VERSION 5.8 ;
BUSBITCHARS "[]" ;
DIVIDERCHAR "/" ;
UNITS
    DATABASE MICRONS 1000 ;
END UNITS

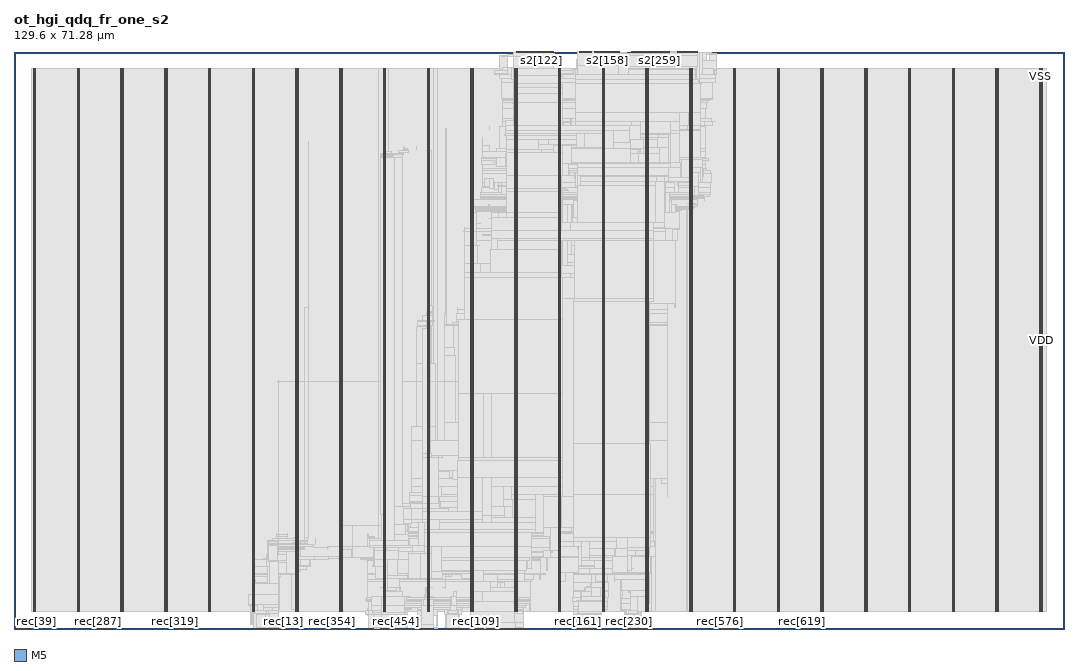
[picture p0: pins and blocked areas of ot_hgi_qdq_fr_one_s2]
MACRO ot_hgi_qdq_fr_one_s2
  FOREIGN ot_hgi_qdq_fr_one_s2 0 0 ;
  CLASS BLOCK ;
  SIZE 129.6 BY 71.28 ;
  PIN clk
    DIRECTION INPUT ;
    USE SIGNAL ;
    PORT
      LAYER M5 ;
        RECT  32.592 0 32.616 0.084 ;
    END
  END clk
  PIN nfault
    DIRECTION OUTPUT ;
    USE SIGNAL ;
    PORT
      LAYER M5 ;
        RECT  62.064 71.196 62.088 71.28 ;
    END
  END nfault
  PIN one
    DIRECTION OUTPUT ;
    USE SIGNAL ;
    PORT
      LAYER M5 ;
        RECT  62.112 71.196 62.136 71.28 ;
    END
  END one
  PIN one_s1
    DIRECTION OUTPUT ;
    USE SIGNAL ;
    PORT
      LAYER M5 ;
        RECT  62.16 71.196 62.184 71.28 ;
    END
  END one_s1
  PIN rec[0]
    DIRECTION INPUT ;
    USE SIGNAL ;
    PORT
      LAYER M5 ;
        RECT  32.64 0 32.664 0.084 ;
    END
  END rec[0]
  PIN rec[100]
    DIRECTION INPUT ;
    USE SIGNAL ;
    PORT
      LAYER M5 ;
        RECT  56.64 0 56.664 0.084 ;
    END
  END rec[100]
  PIN rec[101]
    DIRECTION INPUT ;
    USE SIGNAL ;
    PORT
      LAYER M5 ;
        RECT  56.688 0 56.712 0.084 ;
    END
  END rec[101]
  PIN rec[102]
    DIRECTION INPUT ;
    USE SIGNAL ;
    PORT
      LAYER M5 ;
        RECT  56.736 0 56.76 0.084 ;
    END
  END rec[102]
  PIN rec[103]
    DIRECTION INPUT ;
    USE SIGNAL ;
    PORT
      LAYER M5 ;
        RECT  56.784 0 56.808 0.084 ;
    END
  END rec[103]
  PIN rec[104]
    DIRECTION INPUT ;
    USE SIGNAL ;
    PORT
      LAYER M5 ;
        RECT  56.832 0 56.856 0.084 ;
    END
  END rec[104]
  PIN rec[105]
    DIRECTION INPUT ;
    USE SIGNAL ;
    PORT
      LAYER M5 ;
        RECT  56.88 0 56.904 0.084 ;
    END
  END rec[105]
  PIN rec[106]
    DIRECTION INPUT ;
    USE SIGNAL ;
    PORT
      LAYER M5 ;
        RECT  56.928 0 56.952 0.084 ;
    END
  END rec[106]
  PIN rec[107]
    DIRECTION INPUT ;
    USE SIGNAL ;
    PORT
      LAYER M5 ;
        RECT  56.976 0 57 0.084 ;
    END
  END rec[107]
  PIN rec[108]
    DIRECTION INPUT ;
    USE SIGNAL ;
    PORT
      LAYER M5 ;
        RECT  57.024 0 57.048 0.084 ;
    END
  END rec[108]
  PIN rec[109]
    DIRECTION INPUT ;
    USE SIGNAL ;
    PORT
      LAYER M5 ;
        RECT  57.072 0 57.096 0.084 ;
    END
  END rec[109]
  PIN rec[10]
    DIRECTION INPUT ;
    USE SIGNAL ;
    PORT
      LAYER M5 ;
        RECT  33.12 0 33.144 0.084 ;
    END
  END rec[10]
  PIN rec[110]
    DIRECTION INPUT ;
    USE SIGNAL ;
    PORT
      LAYER M5 ;
        RECT  57.12 0 57.144 0.084 ;
    END
  END rec[110]
  PIN rec[111]
    DIRECTION INPUT ;
    USE SIGNAL ;
    PORT
      LAYER M5 ;
        RECT  57.168 0 57.192 0.084 ;
    END
  END rec[111]
  PIN rec[112]
    DIRECTION INPUT ;
    USE SIGNAL ;
    PORT
      LAYER M5 ;
        RECT  57.216 0 57.24 0.084 ;
    END
  END rec[112]
  PIN rec[113]
    DIRECTION INPUT ;
    USE SIGNAL ;
    PORT
      LAYER M5 ;
        RECT  57.264 0 57.288 0.084 ;
    END
  END rec[113]
  PIN rec[114]
    DIRECTION INPUT ;
    USE SIGNAL ;
    PORT
      LAYER M5 ;
        RECT  57.312 0 57.336 0.084 ;
    END
  END rec[114]
  PIN rec[115]
    DIRECTION INPUT ;
    USE SIGNAL ;
    PORT
      LAYER M5 ;
        RECT  57.36 0 57.384 0.084 ;
    END
  END rec[115]
  PIN rec[116]
    DIRECTION INPUT ;
    USE SIGNAL ;
    PORT
      LAYER M5 ;
        RECT  57.408 0 57.432 0.084 ;
    END
  END rec[116]
  PIN rec[117]
    DIRECTION INPUT ;
    USE SIGNAL ;
    PORT
      LAYER M5 ;
        RECT  57.456 0 57.48 0.084 ;
    END
  END rec[117]
  PIN rec[118]
    DIRECTION INPUT ;
    USE SIGNAL ;
    PORT
      LAYER M5 ;
        RECT  57.504 0 57.528 0.084 ;
    END
  END rec[118]
  PIN rec[119]
    DIRECTION INPUT ;
    USE SIGNAL ;
    PORT
      LAYER M5 ;
        RECT  57.552 0 57.576 0.084 ;
    END
  END rec[119]
  PIN rec[11]
    DIRECTION INPUT ;
    USE SIGNAL ;
    PORT
      LAYER M5 ;
        RECT  33.168 0 33.192 0.084 ;
    END
  END rec[11]
  PIN rec[120]
    DIRECTION INPUT ;
    USE SIGNAL ;
    PORT
      LAYER M5 ;
        RECT  57.6 0 57.624 0.084 ;
    END
  END rec[120]
  PIN rec[121]
    DIRECTION INPUT ;
    USE SIGNAL ;
    PORT
      LAYER M5 ;
        RECT  57.648 0 57.672 0.084 ;
    END
  END rec[121]
  PIN rec[122]
    DIRECTION INPUT ;
    USE SIGNAL ;
    PORT
      LAYER M5 ;
        RECT  57.696 0 57.72 0.084 ;
    END
  END rec[122]
  PIN rec[123]
    DIRECTION INPUT ;
    USE SIGNAL ;
    PORT
      LAYER M5 ;
        RECT  57.744 0 57.768 0.084 ;
    END
  END rec[123]
  PIN rec[124]
    DIRECTION INPUT ;
    USE SIGNAL ;
    PORT
      LAYER M5 ;
        RECT  57.792 0 57.816 0.084 ;
    END
  END rec[124]
  PIN rec[125]
    DIRECTION INPUT ;
    USE SIGNAL ;
    PORT
      LAYER M5 ;
        RECT  57.84 0 57.864 0.084 ;
    END
  END rec[125]
  PIN rec[126]
    DIRECTION INPUT ;
    USE SIGNAL ;
    PORT
      LAYER M5 ;
        RECT  57.888 0 57.912 0.084 ;
    END
  END rec[126]
  PIN rec[127]
    DIRECTION INPUT ;
    USE SIGNAL ;
    PORT
      LAYER M5 ;
        RECT  59.856 0 59.88 0.084 ;
    END
  END rec[127]
  PIN rec[128]
    DIRECTION INPUT ;
    USE SIGNAL ;
    PORT
      LAYER M5 ;
        RECT  59.904 0 59.928 0.084 ;
    END
  END rec[128]
  PIN rec[129]
    DIRECTION INPUT ;
    USE SIGNAL ;
    PORT
      LAYER M5 ;
        RECT  59.952 0 59.976 0.084 ;
    END
  END rec[129]
  PIN rec[12]
    DIRECTION INPUT ;
    USE SIGNAL ;
    PORT
      LAYER M5 ;
        RECT  33.216 0 33.24 0.084 ;
    END
  END rec[12]
  PIN rec[130]
    DIRECTION INPUT ;
    USE SIGNAL ;
    PORT
      LAYER M5 ;
        RECT  60 0 60.024 0.084 ;
    END
  END rec[130]
  PIN rec[131]
    DIRECTION INPUT ;
    USE SIGNAL ;
    PORT
      LAYER M5 ;
        RECT  60.048 0 60.072 0.084 ;
    END
  END rec[131]
  PIN rec[132]
    DIRECTION INPUT ;
    USE SIGNAL ;
    PORT
      LAYER M5 ;
        RECT  60.096 0 60.12 0.084 ;
    END
  END rec[132]
  PIN rec[133]
    DIRECTION INPUT ;
    USE SIGNAL ;
    PORT
      LAYER M5 ;
        RECT  60.144 0 60.168 0.084 ;
    END
  END rec[133]
  PIN rec[134]
    DIRECTION INPUT ;
    USE SIGNAL ;
    PORT
      LAYER M5 ;
        RECT  60.192 0 60.216 0.084 ;
    END
  END rec[134]
  PIN rec[135]
    DIRECTION INPUT ;
    USE SIGNAL ;
    PORT
      LAYER M5 ;
        RECT  60.24 0 60.264 0.084 ;
    END
  END rec[135]
  PIN rec[136]
    DIRECTION INPUT ;
    USE SIGNAL ;
    PORT
      LAYER M5 ;
        RECT  60.288 0 60.312 0.084 ;
    END
  END rec[136]
  PIN rec[137]
    DIRECTION INPUT ;
    USE SIGNAL ;
    PORT
      LAYER M5 ;
        RECT  60.336 0 60.36 0.084 ;
    END
  END rec[137]
  PIN rec[138]
    DIRECTION INPUT ;
    USE SIGNAL ;
    PORT
      LAYER M5 ;
        RECT  60.384 0 60.408 0.084 ;
    END
  END rec[138]
  PIN rec[139]
    DIRECTION INPUT ;
    USE SIGNAL ;
    PORT
      LAYER M5 ;
        RECT  60.432 0 60.456 0.084 ;
    END
  END rec[139]
  PIN rec[13]
    DIRECTION INPUT ;
    USE SIGNAL ;
    PORT
      LAYER M5 ;
        RECT  33.264 0 33.288 0.084 ;
    END
  END rec[13]
  PIN rec[140]
    DIRECTION INPUT ;
    USE SIGNAL ;
    PORT
      LAYER M5 ;
        RECT  60.48 0 60.504 0.084 ;
    END
  END rec[140]
  PIN rec[141]
    DIRECTION INPUT ;
    USE SIGNAL ;
    PORT
      LAYER M5 ;
        RECT  60.528 0 60.552 0.084 ;
    END
  END rec[141]
  PIN rec[142]
    DIRECTION INPUT ;
    USE SIGNAL ;
    PORT
      LAYER M5 ;
        RECT  60.576 0 60.6 0.084 ;
    END
  END rec[142]
  PIN rec[143]
    DIRECTION INPUT ;
    USE SIGNAL ;
    PORT
      LAYER M5 ;
        RECT  60.624 0 60.648 0.084 ;
    END
  END rec[143]
  PIN rec[144]
    DIRECTION INPUT ;
    USE SIGNAL ;
    PORT
      LAYER M5 ;
        RECT  60.672 0 60.696 0.084 ;
    END
  END rec[144]
  PIN rec[145]
    DIRECTION INPUT ;
    USE SIGNAL ;
    PORT
      LAYER M5 ;
        RECT  60.72 0 60.744 0.084 ;
    END
  END rec[145]
  PIN rec[146]
    DIRECTION INPUT ;
    USE SIGNAL ;
    PORT
      LAYER M5 ;
        RECT  60.768 0 60.792 0.084 ;
    END
  END rec[146]
  PIN rec[147]
    DIRECTION INPUT ;
    USE SIGNAL ;
    PORT
      LAYER M5 ;
        RECT  60.816 0 60.84 0.084 ;
    END
  END rec[147]
  PIN rec[148]
    DIRECTION INPUT ;
    USE SIGNAL ;
    PORT
      LAYER M5 ;
        RECT  60.864 0 60.888 0.084 ;
    END
  END rec[148]
  PIN rec[149]
    DIRECTION INPUT ;
    USE SIGNAL ;
    PORT
      LAYER M5 ;
        RECT  60.912 0 60.936 0.084 ;
    END
  END rec[149]
  PIN rec[14]
    DIRECTION INPUT ;
    USE SIGNAL ;
    PORT
      LAYER M5 ;
        RECT  33.312 0 33.336 0.084 ;
    END
  END rec[14]
  PIN rec[150]
    DIRECTION INPUT ;
    USE SIGNAL ;
    PORT
      LAYER M5 ;
        RECT  60.96 0 60.984 0.084 ;
    END
  END rec[150]
  PIN rec[151]
    DIRECTION INPUT ;
    USE SIGNAL ;
    PORT
      LAYER M5 ;
        RECT  61.008 0 61.032 0.084 ;
    END
  END rec[151]
  PIN rec[152]
    DIRECTION INPUT ;
    USE SIGNAL ;
    PORT
      LAYER M5 ;
        RECT  61.056 0 61.08 0.084 ;
    END
  END rec[152]
  PIN rec[153]
    DIRECTION INPUT ;
    USE SIGNAL ;
    PORT
      LAYER M5 ;
        RECT  61.104 0 61.128 0.084 ;
    END
  END rec[153]
  PIN rec[154]
    DIRECTION INPUT ;
    USE SIGNAL ;
    PORT
      LAYER M5 ;
        RECT  61.152 0 61.176 0.084 ;
    END
  END rec[154]
  PIN rec[155]
    DIRECTION INPUT ;
    USE SIGNAL ;
    PORT
      LAYER M5 ;
        RECT  61.2 0 61.224 0.084 ;
    END
  END rec[155]
  PIN rec[156]
    DIRECTION INPUT ;
    USE SIGNAL ;
    PORT
      LAYER M5 ;
        RECT  61.248 0 61.272 0.084 ;
    END
  END rec[156]
  PIN rec[157]
    DIRECTION INPUT ;
    USE SIGNAL ;
    PORT
      LAYER M5 ;
        RECT  61.296 0 61.32 0.084 ;
    END
  END rec[157]
  PIN rec[158]
    DIRECTION INPUT ;
    USE SIGNAL ;
    PORT
      LAYER M5 ;
        RECT  61.344 0 61.368 0.084 ;
    END
  END rec[158]
  PIN rec[159]
    DIRECTION INPUT ;
    USE SIGNAL ;
    PORT
      LAYER M5 ;
        RECT  69.456 0 69.48 0.084 ;
    END
  END rec[159]
  PIN rec[15]
    DIRECTION INPUT ;
    USE SIGNAL ;
    PORT
      LAYER M5 ;
        RECT  33.36 0 33.384 0.084 ;
    END
  END rec[15]
  PIN rec[160]
    DIRECTION INPUT ;
    USE SIGNAL ;
    PORT
      LAYER M5 ;
        RECT  69.504 0 69.528 0.084 ;
    END
  END rec[160]
  PIN rec[161]
    DIRECTION INPUT ;
    USE SIGNAL ;
    PORT
      LAYER M5 ;
        RECT  69.552 0 69.576 0.084 ;
    END
  END rec[161]
  PIN rec[162]
    DIRECTION INPUT ;
    USE SIGNAL ;
    PORT
      LAYER M5 ;
        RECT  69.6 0 69.624 0.084 ;
    END
  END rec[162]
  PIN rec[163]
    DIRECTION INPUT ;
    USE SIGNAL ;
    PORT
      LAYER M5 ;
        RECT  69.648 0 69.672 0.084 ;
    END
  END rec[163]
  PIN rec[164]
    DIRECTION INPUT ;
    USE SIGNAL ;
    PORT
      LAYER M5 ;
        RECT  69.696 0 69.72 0.084 ;
    END
  END rec[164]
  PIN rec[165]
    DIRECTION INPUT ;
    USE SIGNAL ;
    PORT
      LAYER M5 ;
        RECT  69.744 0 69.768 0.084 ;
    END
  END rec[165]
  PIN rec[166]
    DIRECTION INPUT ;
    USE SIGNAL ;
    PORT
      LAYER M5 ;
        RECT  69.792 0 69.816 0.084 ;
    END
  END rec[166]
  PIN rec[167]
    DIRECTION INPUT ;
    USE SIGNAL ;
    PORT
      LAYER M5 ;
        RECT  69.84 0 69.864 0.084 ;
    END
  END rec[167]
  PIN rec[168]
    DIRECTION INPUT ;
    USE SIGNAL ;
    PORT
      LAYER M5 ;
        RECT  69.888 0 69.912 0.084 ;
    END
  END rec[168]
  PIN rec[169]
    DIRECTION INPUT ;
    USE SIGNAL ;
    PORT
      LAYER M5 ;
        RECT  69.936 0 69.96 0.084 ;
    END
  END rec[169]
  PIN rec[16]
    DIRECTION INPUT ;
    USE SIGNAL ;
    PORT
      LAYER M5 ;
        RECT  33.408 0 33.432 0.084 ;
    END
  END rec[16]
  PIN rec[170]
    DIRECTION INPUT ;
    USE SIGNAL ;
    PORT
      LAYER M5 ;
        RECT  69.984 0 70.008 0.084 ;
    END
  END rec[170]
  PIN rec[171]
    DIRECTION INPUT ;
    USE SIGNAL ;
    PORT
      LAYER M5 ;
        RECT  70.032 0 70.056 0.084 ;
    END
  END rec[171]
  PIN rec[172]
    DIRECTION INPUT ;
    USE SIGNAL ;
    PORT
      LAYER M5 ;
        RECT  70.08 0 70.104 0.084 ;
    END
  END rec[172]
  PIN rec[173]
    DIRECTION INPUT ;
    USE SIGNAL ;
    PORT
      LAYER M5 ;
        RECT  70.128 0 70.152 0.084 ;
    END
  END rec[173]
  PIN rec[174]
    DIRECTION INPUT ;
    USE SIGNAL ;
    PORT
      LAYER M5 ;
        RECT  70.176 0 70.2 0.084 ;
    END
  END rec[174]
  PIN rec[175]
    DIRECTION INPUT ;
    USE SIGNAL ;
    PORT
      LAYER M5 ;
        RECT  70.224 0 70.248 0.084 ;
    END
  END rec[175]
  PIN rec[176]
    DIRECTION INPUT ;
    USE SIGNAL ;
    PORT
      LAYER M5 ;
        RECT  70.272 0 70.296 0.084 ;
    END
  END rec[176]
  PIN rec[177]
    DIRECTION INPUT ;
    USE SIGNAL ;
    PORT
      LAYER M5 ;
        RECT  70.32 0 70.344 0.084 ;
    END
  END rec[177]
  PIN rec[178]
    DIRECTION INPUT ;
    USE SIGNAL ;
    PORT
      LAYER M5 ;
        RECT  70.368 0 70.392 0.084 ;
    END
  END rec[178]
  PIN rec[179]
    DIRECTION INPUT ;
    USE SIGNAL ;
    PORT
      LAYER M5 ;
        RECT  70.416 0 70.44 0.084 ;
    END
  END rec[179]
  PIN rec[17]
    DIRECTION INPUT ;
    USE SIGNAL ;
    PORT
      LAYER M5 ;
        RECT  33.456 0 33.48 0.084 ;
    END
  END rec[17]
  PIN rec[180]
    DIRECTION INPUT ;
    USE SIGNAL ;
    PORT
      LAYER M5 ;
        RECT  70.464 0 70.488 0.084 ;
    END
  END rec[180]
  PIN rec[181]
    DIRECTION INPUT ;
    USE SIGNAL ;
    PORT
      LAYER M5 ;
        RECT  70.512 0 70.536 0.084 ;
    END
  END rec[181]
  PIN rec[182]
    DIRECTION INPUT ;
    USE SIGNAL ;
    PORT
      LAYER M5 ;
        RECT  70.56 0 70.584 0.084 ;
    END
  END rec[182]
  PIN rec[183]
    DIRECTION INPUT ;
    USE SIGNAL ;
    PORT
      LAYER M5 ;
        RECT  70.608 0 70.632 0.084 ;
    END
  END rec[183]
  PIN rec[184]
    DIRECTION INPUT ;
    USE SIGNAL ;
    PORT
      LAYER M5 ;
        RECT  70.656 0 70.68 0.084 ;
    END
  END rec[184]
  PIN rec[185]
    DIRECTION INPUT ;
    USE SIGNAL ;
    PORT
      LAYER M5 ;
        RECT  70.704 0 70.728 0.084 ;
    END
  END rec[185]
  PIN rec[186]
    DIRECTION INPUT ;
    USE SIGNAL ;
    PORT
      LAYER M5 ;
        RECT  70.752 0 70.776 0.084 ;
    END
  END rec[186]
  PIN rec[187]
    DIRECTION INPUT ;
    USE SIGNAL ;
    PORT
      LAYER M5 ;
        RECT  70.8 0 70.824 0.084 ;
    END
  END rec[187]
  PIN rec[188]
    DIRECTION INPUT ;
    USE SIGNAL ;
    PORT
      LAYER M5 ;
        RECT  70.848 0 70.872 0.084 ;
    END
  END rec[188]
  PIN rec[189]
    DIRECTION INPUT ;
    USE SIGNAL ;
    PORT
      LAYER M5 ;
        RECT  70.896 0 70.92 0.084 ;
    END
  END rec[189]
  PIN rec[18]
    DIRECTION INPUT ;
    USE SIGNAL ;
    PORT
      LAYER M5 ;
        RECT  33.504 0 33.528 0.084 ;
    END
  END rec[18]
  PIN rec[190]
    DIRECTION INPUT ;
    USE SIGNAL ;
    PORT
      LAYER M5 ;
        RECT  70.944 0 70.968 0.084 ;
    END
  END rec[190]
  PIN rec[191]
    DIRECTION INPUT ;
    USE SIGNAL ;
    PORT
      LAYER M5 ;
        RECT  50.256 0 50.28 0.084 ;
    END
  END rec[191]
  PIN rec[192]
    DIRECTION INPUT ;
    USE SIGNAL ;
    PORT
      LAYER M5 ;
        RECT  50.304 0 50.328 0.084 ;
    END
  END rec[192]
  PIN rec[193]
    DIRECTION INPUT ;
    USE SIGNAL ;
    PORT
      LAYER M5 ;
        RECT  50.352 0 50.376 0.084 ;
    END
  END rec[193]
  PIN rec[194]
    DIRECTION INPUT ;
    USE SIGNAL ;
    PORT
      LAYER M5 ;
        RECT  50.4 0 50.424 0.084 ;
    END
  END rec[194]
  PIN rec[195]
    DIRECTION INPUT ;
    USE SIGNAL ;
    PORT
      LAYER M5 ;
        RECT  50.448 0 50.472 0.084 ;
    END
  END rec[195]
  PIN rec[196]
    DIRECTION INPUT ;
    USE SIGNAL ;
    PORT
      LAYER M5 ;
        RECT  50.496 0 50.52 0.084 ;
    END
  END rec[196]
  PIN rec[197]
    DIRECTION INPUT ;
    USE SIGNAL ;
    PORT
      LAYER M5 ;
        RECT  50.544 0 50.568 0.084 ;
    END
  END rec[197]
  PIN rec[198]
    DIRECTION INPUT ;
    USE SIGNAL ;
    PORT
      LAYER M5 ;
        RECT  50.592 0 50.616 0.084 ;
    END
  END rec[198]
  PIN rec[199]
    DIRECTION INPUT ;
    USE SIGNAL ;
    PORT
      LAYER M5 ;
        RECT  50.64 0 50.664 0.084 ;
    END
  END rec[199]
  PIN rec[19]
    DIRECTION INPUT ;
    USE SIGNAL ;
    PORT
      LAYER M5 ;
        RECT  33.552 0 33.576 0.084 ;
    END
  END rec[19]
  PIN rec[1]
    DIRECTION INPUT ;
    USE SIGNAL ;
    PORT
      LAYER M5 ;
        RECT  32.688 0 32.712 0.084 ;
    END
  END rec[1]
  PIN rec[200]
    DIRECTION INPUT ;
    USE SIGNAL ;
    PORT
      LAYER M5 ;
        RECT  50.688 0 50.712 0.084 ;
    END
  END rec[200]
  PIN rec[201]
    DIRECTION INPUT ;
    USE SIGNAL ;
    PORT
      LAYER M5 ;
        RECT  50.736 0 50.76 0.084 ;
    END
  END rec[201]
  PIN rec[202]
    DIRECTION INPUT ;
    USE SIGNAL ;
    PORT
      LAYER M5 ;
        RECT  50.784 0 50.808 0.084 ;
    END
  END rec[202]
  PIN rec[203]
    DIRECTION INPUT ;
    USE SIGNAL ;
    PORT
      LAYER M5 ;
        RECT  50.832 0 50.856 0.084 ;
    END
  END rec[203]
  PIN rec[204]
    DIRECTION INPUT ;
    USE SIGNAL ;
    PORT
      LAYER M5 ;
        RECT  50.88 0 50.904 0.084 ;
    END
  END rec[204]
  PIN rec[205]
    DIRECTION INPUT ;
    USE SIGNAL ;
    PORT
      LAYER M5 ;
        RECT  50.928 0 50.952 0.084 ;
    END
  END rec[205]
  PIN rec[206]
    DIRECTION INPUT ;
    USE SIGNAL ;
    PORT
      LAYER M5 ;
        RECT  50.976 0 51 0.084 ;
    END
  END rec[206]
  PIN rec[207]
    DIRECTION INPUT ;
    USE SIGNAL ;
    PORT
      LAYER M5 ;
        RECT  51.024 0 51.048 0.084 ;
    END
  END rec[207]
  PIN rec[208]
    DIRECTION INPUT ;
    USE SIGNAL ;
    PORT
      LAYER M5 ;
        RECT  51.072 0 51.096 0.084 ;
    END
  END rec[208]
  PIN rec[209]
    DIRECTION INPUT ;
    USE SIGNAL ;
    PORT
      LAYER M5 ;
        RECT  51.12 0 51.144 0.084 ;
    END
  END rec[209]
  PIN rec[20]
    DIRECTION INPUT ;
    USE SIGNAL ;
    PORT
      LAYER M5 ;
        RECT  33.6 0 33.624 0.084 ;
    END
  END rec[20]
  PIN rec[210]
    DIRECTION INPUT ;
    USE SIGNAL ;
    PORT
      LAYER M5 ;
        RECT  51.168 0 51.192 0.084 ;
    END
  END rec[210]
  PIN rec[211]
    DIRECTION INPUT ;
    USE SIGNAL ;
    PORT
      LAYER M5 ;
        RECT  51.216 0 51.24 0.084 ;
    END
  END rec[211]
  PIN rec[212]
    DIRECTION INPUT ;
    USE SIGNAL ;
    PORT
      LAYER M5 ;
        RECT  51.264 0 51.288 0.084 ;
    END
  END rec[212]
  PIN rec[213]
    DIRECTION INPUT ;
    USE SIGNAL ;
    PORT
      LAYER M5 ;
        RECT  51.312 0 51.336 0.084 ;
    END
  END rec[213]
  PIN rec[214]
    DIRECTION INPUT ;
    USE SIGNAL ;
    PORT
      LAYER M5 ;
        RECT  51.36 0 51.384 0.084 ;
    END
  END rec[214]
  PIN rec[215]
    DIRECTION INPUT ;
    USE SIGNAL ;
    PORT
      LAYER M5 ;
        RECT  51.408 0 51.432 0.084 ;
    END
  END rec[215]
  PIN rec[216]
    DIRECTION INPUT ;
    USE SIGNAL ;
    PORT
      LAYER M5 ;
        RECT  51.456 0 51.48 0.084 ;
    END
  END rec[216]
  PIN rec[217]
    DIRECTION INPUT ;
    USE SIGNAL ;
    PORT
      LAYER M5 ;
        RECT  51.504 0 51.528 0.084 ;
    END
  END rec[217]
  PIN rec[218]
    DIRECTION INPUT ;
    USE SIGNAL ;
    PORT
      LAYER M5 ;
        RECT  51.552 0 51.576 0.084 ;
    END
  END rec[218]
  PIN rec[219]
    DIRECTION INPUT ;
    USE SIGNAL ;
    PORT
      LAYER M5 ;
        RECT  51.6 0 51.624 0.084 ;
    END
  END rec[219]
  PIN rec[21]
    DIRECTION INPUT ;
    USE SIGNAL ;
    PORT
      LAYER M5 ;
        RECT  33.648 0 33.672 0.084 ;
    END
  END rec[21]
  PIN rec[220]
    DIRECTION INPUT ;
    USE SIGNAL ;
    PORT
      LAYER M5 ;
        RECT  51.648 0 51.672 0.084 ;
    END
  END rec[220]
  PIN rec[221]
    DIRECTION INPUT ;
    USE SIGNAL ;
    PORT
      LAYER M5 ;
        RECT  51.696 0 51.72 0.084 ;
    END
  END rec[221]
  PIN rec[222]
    DIRECTION INPUT ;
    USE SIGNAL ;
    PORT
      LAYER M5 ;
        RECT  51.744 0 51.768 0.084 ;
    END
  END rec[222]
  PIN rec[223]
    DIRECTION INPUT ;
    USE SIGNAL ;
    PORT
      LAYER M5 ;
        RECT  75.6 0 75.624 0.084 ;
    END
  END rec[223]
  PIN rec[224]
    DIRECTION INPUT ;
    USE SIGNAL ;
    PORT
      LAYER M5 ;
        RECT  75.648 0 75.672 0.084 ;
    END
  END rec[224]
  PIN rec[225]
    DIRECTION INPUT ;
    USE SIGNAL ;
    PORT
      LAYER M5 ;
        RECT  75.696 0 75.72 0.084 ;
    END
  END rec[225]
  PIN rec[226]
    DIRECTION INPUT ;
    USE SIGNAL ;
    PORT
      LAYER M5 ;
        RECT  75.744 0 75.768 0.084 ;
    END
  END rec[226]
  PIN rec[227]
    DIRECTION INPUT ;
    USE SIGNAL ;
    PORT
      LAYER M5 ;
        RECT  75.792 0 75.816 0.084 ;
    END
  END rec[227]
  PIN rec[228]
    DIRECTION INPUT ;
    USE SIGNAL ;
    PORT
      LAYER M5 ;
        RECT  75.84 0 75.864 0.084 ;
    END
  END rec[228]
  PIN rec[229]
    DIRECTION INPUT ;
    USE SIGNAL ;
    PORT
      LAYER M5 ;
        RECT  75.888 0 75.912 0.084 ;
    END
  END rec[229]
  PIN rec[22]
    DIRECTION INPUT ;
    USE SIGNAL ;
    PORT
      LAYER M5 ;
        RECT  33.696 0 33.72 0.084 ;
    END
  END rec[22]
  PIN rec[230]
    DIRECTION INPUT ;
    USE SIGNAL ;
    PORT
      LAYER M5 ;
        RECT  75.936 0 75.96 0.084 ;
    END
  END rec[230]
  PIN rec[231]
    DIRECTION INPUT ;
    USE SIGNAL ;
    PORT
      LAYER M5 ;
        RECT  75.984 0 76.008 0.084 ;
    END
  END rec[231]
  PIN rec[232]
    DIRECTION INPUT ;
    USE SIGNAL ;
    PORT
      LAYER M5 ;
        RECT  76.032 0 76.056 0.084 ;
    END
  END rec[232]
  PIN rec[233]
    DIRECTION INPUT ;
    USE SIGNAL ;
    PORT
      LAYER M5 ;
        RECT  76.08 0 76.104 0.084 ;
    END
  END rec[233]
  PIN rec[234]
    DIRECTION INPUT ;
    USE SIGNAL ;
    PORT
      LAYER M5 ;
        RECT  76.128 0 76.152 0.084 ;
    END
  END rec[234]
  PIN rec[235]
    DIRECTION INPUT ;
    USE SIGNAL ;
    PORT
      LAYER M5 ;
        RECT  76.176 0 76.2 0.084 ;
    END
  END rec[235]
  PIN rec[236]
    DIRECTION INPUT ;
    USE SIGNAL ;
    PORT
      LAYER M5 ;
        RECT  76.224 0 76.248 0.084 ;
    END
  END rec[236]
  PIN rec[237]
    DIRECTION INPUT ;
    USE SIGNAL ;
    PORT
      LAYER M5 ;
        RECT  76.272 0 76.296 0.084 ;
    END
  END rec[237]
  PIN rec[238]
    DIRECTION INPUT ;
    USE SIGNAL ;
    PORT
      LAYER M5 ;
        RECT  76.32 0 76.344 0.084 ;
    END
  END rec[238]
  PIN rec[239]
    DIRECTION INPUT ;
    USE SIGNAL ;
    PORT
      LAYER M5 ;
        RECT  76.368 0 76.392 0.084 ;
    END
  END rec[239]
  PIN rec[23]
    DIRECTION INPUT ;
    USE SIGNAL ;
    PORT
      LAYER M5 ;
        RECT  33.744 0 33.768 0.084 ;
    END
  END rec[23]
  PIN rec[240]
    DIRECTION INPUT ;
    USE SIGNAL ;
    PORT
      LAYER M5 ;
        RECT  76.416 0 76.44 0.084 ;
    END
  END rec[240]
  PIN rec[241]
    DIRECTION INPUT ;
    USE SIGNAL ;
    PORT
      LAYER M5 ;
        RECT  76.464 0 76.488 0.084 ;
    END
  END rec[241]
  PIN rec[242]
    DIRECTION INPUT ;
    USE SIGNAL ;
    PORT
      LAYER M5 ;
        RECT  76.512 0 76.536 0.084 ;
    END
  END rec[242]
  PIN rec[243]
    DIRECTION INPUT ;
    USE SIGNAL ;
    PORT
      LAYER M5 ;
        RECT  76.56 0 76.584 0.084 ;
    END
  END rec[243]
  PIN rec[244]
    DIRECTION INPUT ;
    USE SIGNAL ;
    PORT
      LAYER M5 ;
        RECT  76.608 0 76.632 0.084 ;
    END
  END rec[244]
  PIN rec[245]
    DIRECTION INPUT ;
    USE SIGNAL ;
    PORT
      LAYER M5 ;
        RECT  76.656 0 76.68 0.084 ;
    END
  END rec[245]
  PIN rec[246]
    DIRECTION INPUT ;
    USE SIGNAL ;
    PORT
      LAYER M5 ;
        RECT  76.704 0 76.728 0.084 ;
    END
  END rec[246]
  PIN rec[247]
    DIRECTION INPUT ;
    USE SIGNAL ;
    PORT
      LAYER M5 ;
        RECT  76.752 0 76.776 0.084 ;
    END
  END rec[247]
  PIN rec[248]
    DIRECTION INPUT ;
    USE SIGNAL ;
    PORT
      LAYER M5 ;
        RECT  76.8 0 76.824 0.084 ;
    END
  END rec[248]
  PIN rec[249]
    DIRECTION INPUT ;
    USE SIGNAL ;
    PORT
      LAYER M5 ;
        RECT  76.848 0 76.872 0.084 ;
    END
  END rec[249]
  PIN rec[24]
    DIRECTION INPUT ;
    USE SIGNAL ;
    PORT
      LAYER M5 ;
        RECT  33.792 0 33.816 0.084 ;
    END
  END rec[24]
  PIN rec[250]
    DIRECTION INPUT ;
    USE SIGNAL ;
    PORT
      LAYER M5 ;
        RECT  76.896 0 76.92 0.084 ;
    END
  END rec[250]
  PIN rec[251]
    DIRECTION INPUT ;
    USE SIGNAL ;
    PORT
      LAYER M5 ;
        RECT  76.944 0 76.968 0.084 ;
    END
  END rec[251]
  PIN rec[252]
    DIRECTION INPUT ;
    USE SIGNAL ;
    PORT
      LAYER M5 ;
        RECT  76.992 0 77.016 0.084 ;
    END
  END rec[252]
  PIN rec[253]
    DIRECTION INPUT ;
    USE SIGNAL ;
    PORT
      LAYER M5 ;
        RECT  77.04 0 77.064 0.084 ;
    END
  END rec[253]
  PIN rec[254]
    DIRECTION INPUT ;
    USE SIGNAL ;
    PORT
      LAYER M5 ;
        RECT  77.088 0 77.112 0.084 ;
    END
  END rec[254]
  PIN rec[255]
    DIRECTION INPUT ;
    USE SIGNAL ;
    PORT
      LAYER M5 ;
        RECT  29.52 0 29.544 0.084 ;
    END
  END rec[255]
  PIN rec[256]
    DIRECTION INPUT ;
    USE SIGNAL ;
    PORT
      LAYER M5 ;
        RECT  29.568 0 29.592 0.084 ;
    END
  END rec[256]
  PIN rec[257]
    DIRECTION INPUT ;
    USE SIGNAL ;
    PORT
      LAYER M5 ;
        RECT  29.616 0 29.64 0.084 ;
    END
  END rec[257]
  PIN rec[258]
    DIRECTION INPUT ;
    USE SIGNAL ;
    PORT
      LAYER M5 ;
        RECT  29.664 0 29.688 0.084 ;
    END
  END rec[258]
  PIN rec[259]
    DIRECTION INPUT ;
    USE SIGNAL ;
    PORT
      LAYER M5 ;
        RECT  29.712 0 29.736 0.084 ;
    END
  END rec[259]
  PIN rec[25]
    DIRECTION INPUT ;
    USE SIGNAL ;
    PORT
      LAYER M5 ;
        RECT  33.84 0 33.864 0.084 ;
    END
  END rec[25]
  PIN rec[260]
    DIRECTION INPUT ;
    USE SIGNAL ;
    PORT
      LAYER M5 ;
        RECT  29.76 0 29.784 0.084 ;
    END
  END rec[260]
  PIN rec[261]
    DIRECTION INPUT ;
    USE SIGNAL ;
    PORT
      LAYER M5 ;
        RECT  29.808 0 29.832 0.084 ;
    END
  END rec[261]
  PIN rec[262]
    DIRECTION INPUT ;
    USE SIGNAL ;
    PORT
      LAYER M5 ;
        RECT  29.856 0 29.88 0.084 ;
    END
  END rec[262]
  PIN rec[263]
    DIRECTION INPUT ;
    USE SIGNAL ;
    PORT
      LAYER M5 ;
        RECT  29.904 0 29.928 0.084 ;
    END
  END rec[263]
  PIN rec[264]
    DIRECTION INPUT ;
    USE SIGNAL ;
    PORT
      LAYER M5 ;
        RECT  29.952 0 29.976 0.084 ;
    END
  END rec[264]
  PIN rec[265]
    DIRECTION INPUT ;
    USE SIGNAL ;
    PORT
      LAYER M5 ;
        RECT  30 0 30.024 0.084 ;
    END
  END rec[265]
  PIN rec[266]
    DIRECTION INPUT ;
    USE SIGNAL ;
    PORT
      LAYER M5 ;
        RECT  30.048 0 30.072 0.084 ;
    END
  END rec[266]
  PIN rec[267]
    DIRECTION INPUT ;
    USE SIGNAL ;
    PORT
      LAYER M5 ;
        RECT  30.096 0 30.12 0.084 ;
    END
  END rec[267]
  PIN rec[268]
    DIRECTION INPUT ;
    USE SIGNAL ;
    PORT
      LAYER M5 ;
        RECT  30.144 0 30.168 0.084 ;
    END
  END rec[268]
  PIN rec[269]
    DIRECTION INPUT ;
    USE SIGNAL ;
    PORT
      LAYER M5 ;
        RECT  30.192 0 30.216 0.084 ;
    END
  END rec[269]
  PIN rec[26]
    DIRECTION INPUT ;
    USE SIGNAL ;
    PORT
      LAYER M5 ;
        RECT  33.888 0 33.912 0.084 ;
    END
  END rec[26]
  PIN rec[270]
    DIRECTION INPUT ;
    USE SIGNAL ;
    PORT
      LAYER M5 ;
        RECT  30.24 0 30.264 0.084 ;
    END
  END rec[270]
  PIN rec[271]
    DIRECTION INPUT ;
    USE SIGNAL ;
    PORT
      LAYER M5 ;
        RECT  30.288 0 30.312 0.084 ;
    END
  END rec[271]
  PIN rec[272]
    DIRECTION INPUT ;
    USE SIGNAL ;
    PORT
      LAYER M5 ;
        RECT  30.336 0 30.36 0.084 ;
    END
  END rec[272]
  PIN rec[273]
    DIRECTION INPUT ;
    USE SIGNAL ;
    PORT
      LAYER M5 ;
        RECT  30.384 0 30.408 0.084 ;
    END
  END rec[273]
  PIN rec[274]
    DIRECTION INPUT ;
    USE SIGNAL ;
    PORT
      LAYER M5 ;
        RECT  30.432 0 30.456 0.084 ;
    END
  END rec[274]
  PIN rec[275]
    DIRECTION INPUT ;
    USE SIGNAL ;
    PORT
      LAYER M5 ;
        RECT  30.48 0 30.504 0.084 ;
    END
  END rec[275]
  PIN rec[276]
    DIRECTION INPUT ;
    USE SIGNAL ;
    PORT
      LAYER M5 ;
        RECT  30.528 0 30.552 0.084 ;
    END
  END rec[276]
  PIN rec[277]
    DIRECTION INPUT ;
    USE SIGNAL ;
    PORT
      LAYER M5 ;
        RECT  30.576 0 30.6 0.084 ;
    END
  END rec[277]
  PIN rec[278]
    DIRECTION INPUT ;
    USE SIGNAL ;
    PORT
      LAYER M5 ;
        RECT  30.624 0 30.648 0.084 ;
    END
  END rec[278]
  PIN rec[279]
    DIRECTION INPUT ;
    USE SIGNAL ;
    PORT
      LAYER M5 ;
        RECT  30.672 0 30.696 0.084 ;
    END
  END rec[279]
  PIN rec[27]
    DIRECTION INPUT ;
    USE SIGNAL ;
    PORT
      LAYER M5 ;
        RECT  33.936 0 33.96 0.084 ;
    END
  END rec[27]
  PIN rec[280]
    DIRECTION INPUT ;
    USE SIGNAL ;
    PORT
      LAYER M5 ;
        RECT  30.72 0 30.744 0.084 ;
    END
  END rec[280]
  PIN rec[281]
    DIRECTION INPUT ;
    USE SIGNAL ;
    PORT
      LAYER M5 ;
        RECT  30.768 0 30.792 0.084 ;
    END
  END rec[281]
  PIN rec[282]
    DIRECTION INPUT ;
    USE SIGNAL ;
    PORT
      LAYER M5 ;
        RECT  30.816 0 30.84 0.084 ;
    END
  END rec[282]
  PIN rec[283]
    DIRECTION INPUT ;
    USE SIGNAL ;
    PORT
      LAYER M5 ;
        RECT  30.864 0 30.888 0.084 ;
    END
  END rec[283]
  PIN rec[284]
    DIRECTION INPUT ;
    USE SIGNAL ;
    PORT
      LAYER M5 ;
        RECT  30.912 0 30.936 0.084 ;
    END
  END rec[284]
  PIN rec[285]
    DIRECTION INPUT ;
    USE SIGNAL ;
    PORT
      LAYER M5 ;
        RECT  30.96 0 30.984 0.084 ;
    END
  END rec[285]
  PIN rec[286]
    DIRECTION INPUT ;
    USE SIGNAL ;
    PORT
      LAYER M5 ;
        RECT  31.008 0 31.032 0.084 ;
    END
  END rec[286]
  PIN rec[287]
    DIRECTION INPUT ;
    USE SIGNAL ;
    PORT
      LAYER M5 ;
        RECT  10.32 0 10.344 0.084 ;
    END
  END rec[287]
  PIN rec[288]
    DIRECTION INPUT ;
    USE SIGNAL ;
    PORT
      LAYER M5 ;
        RECT  10.368 0 10.392 0.084 ;
    END
  END rec[288]
  PIN rec[289]
    DIRECTION INPUT ;
    USE SIGNAL ;
    PORT
      LAYER M5 ;
        RECT  10.416 0 10.44 0.084 ;
    END
  END rec[289]
  PIN rec[28]
    DIRECTION INPUT ;
    USE SIGNAL ;
    PORT
      LAYER M5 ;
        RECT  33.984 0 34.008 0.084 ;
    END
  END rec[28]
  PIN rec[290]
    DIRECTION INPUT ;
    USE SIGNAL ;
    PORT
      LAYER M5 ;
        RECT  10.464 0 10.488 0.084 ;
    END
  END rec[290]
  PIN rec[291]
    DIRECTION INPUT ;
    USE SIGNAL ;
    PORT
      LAYER M5 ;
        RECT  10.512 0 10.536 0.084 ;
    END
  END rec[291]
  PIN rec[292]
    DIRECTION INPUT ;
    USE SIGNAL ;
    PORT
      LAYER M5 ;
        RECT  10.56 0 10.584 0.084 ;
    END
  END rec[292]
  PIN rec[293]
    DIRECTION INPUT ;
    USE SIGNAL ;
    PORT
      LAYER M5 ;
        RECT  10.608 0 10.632 0.084 ;
    END
  END rec[293]
  PIN rec[294]
    DIRECTION INPUT ;
    USE SIGNAL ;
    PORT
      LAYER M5 ;
        RECT  10.656 0 10.68 0.084 ;
    END
  END rec[294]
  PIN rec[295]
    DIRECTION INPUT ;
    USE SIGNAL ;
    PORT
      LAYER M5 ;
        RECT  10.704 0 10.728 0.084 ;
    END
  END rec[295]
  PIN rec[296]
    DIRECTION INPUT ;
    USE SIGNAL ;
    PORT
      LAYER M5 ;
        RECT  10.752 0 10.776 0.084 ;
    END
  END rec[296]
  PIN rec[297]
    DIRECTION INPUT ;
    USE SIGNAL ;
    PORT
      LAYER M5 ;
        RECT  10.8 0 10.824 0.084 ;
    END
  END rec[297]
  PIN rec[298]
    DIRECTION INPUT ;
    USE SIGNAL ;
    PORT
      LAYER M5 ;
        RECT  10.848 0 10.872 0.084 ;
    END
  END rec[298]
  PIN rec[299]
    DIRECTION INPUT ;
    USE SIGNAL ;
    PORT
      LAYER M5 ;
        RECT  10.896 0 10.92 0.084 ;
    END
  END rec[299]
  PIN rec[29]
    DIRECTION INPUT ;
    USE SIGNAL ;
    PORT
      LAYER M5 ;
        RECT  34.032 0 34.056 0.084 ;
    END
  END rec[29]
  PIN rec[2]
    DIRECTION INPUT ;
    USE SIGNAL ;
    PORT
      LAYER M5 ;
        RECT  32.736 0 32.76 0.084 ;
    END
  END rec[2]
  PIN rec[300]
    DIRECTION INPUT ;
    USE SIGNAL ;
    PORT
      LAYER M5 ;
        RECT  10.944 0 10.968 0.084 ;
    END
  END rec[300]
  PIN rec[301]
    DIRECTION INPUT ;
    USE SIGNAL ;
    PORT
      LAYER M5 ;
        RECT  10.992 0 11.016 0.084 ;
    END
  END rec[301]
  PIN rec[302]
    DIRECTION INPUT ;
    USE SIGNAL ;
    PORT
      LAYER M5 ;
        RECT  11.04 0 11.064 0.084 ;
    END
  END rec[302]
  PIN rec[303]
    DIRECTION INPUT ;
    USE SIGNAL ;
    PORT
      LAYER M5 ;
        RECT  11.088 0 11.112 0.084 ;
    END
  END rec[303]
  PIN rec[304]
    DIRECTION INPUT ;
    USE SIGNAL ;
    PORT
      LAYER M5 ;
        RECT  11.136 0 11.16 0.084 ;
    END
  END rec[304]
  PIN rec[305]
    DIRECTION INPUT ;
    USE SIGNAL ;
    PORT
      LAYER M5 ;
        RECT  11.184 0 11.208 0.084 ;
    END
  END rec[305]
  PIN rec[306]
    DIRECTION INPUT ;
    USE SIGNAL ;
    PORT
      LAYER M5 ;
        RECT  11.232 0 11.256 0.084 ;
    END
  END rec[306]
  PIN rec[307]
    DIRECTION INPUT ;
    USE SIGNAL ;
    PORT
      LAYER M5 ;
        RECT  11.28 0 11.304 0.084 ;
    END
  END rec[307]
  PIN rec[308]
    DIRECTION INPUT ;
    USE SIGNAL ;
    PORT
      LAYER M5 ;
        RECT  11.328 0 11.352 0.084 ;
    END
  END rec[308]
  PIN rec[309]
    DIRECTION INPUT ;
    USE SIGNAL ;
    PORT
      LAYER M5 ;
        RECT  11.376 0 11.4 0.084 ;
    END
  END rec[309]
  PIN rec[30]
    DIRECTION INPUT ;
    USE SIGNAL ;
    PORT
      LAYER M5 ;
        RECT  34.08 0 34.104 0.084 ;
    END
  END rec[30]
  PIN rec[310]
    DIRECTION INPUT ;
    USE SIGNAL ;
    PORT
      LAYER M5 ;
        RECT  11.424 0 11.448 0.084 ;
    END
  END rec[310]
  PIN rec[311]
    DIRECTION INPUT ;
    USE SIGNAL ;
    PORT
      LAYER M5 ;
        RECT  11.472 0 11.496 0.084 ;
    END
  END rec[311]
  PIN rec[312]
    DIRECTION INPUT ;
    USE SIGNAL ;
    PORT
      LAYER M5 ;
        RECT  11.52 0 11.544 0.084 ;
    END
  END rec[312]
  PIN rec[313]
    DIRECTION INPUT ;
    USE SIGNAL ;
    PORT
      LAYER M5 ;
        RECT  11.568 0 11.592 0.084 ;
    END
  END rec[313]
  PIN rec[314]
    DIRECTION INPUT ;
    USE SIGNAL ;
    PORT
      LAYER M5 ;
        RECT  11.616 0 11.64 0.084 ;
    END
  END rec[314]
  PIN rec[315]
    DIRECTION INPUT ;
    USE SIGNAL ;
    PORT
      LAYER M5 ;
        RECT  11.664 0 11.688 0.084 ;
    END
  END rec[315]
  PIN rec[316]
    DIRECTION INPUT ;
    USE SIGNAL ;
    PORT
      LAYER M5 ;
        RECT  11.712 0 11.736 0.084 ;
    END
  END rec[316]
  PIN rec[317]
    DIRECTION INPUT ;
    USE SIGNAL ;
    PORT
      LAYER M5 ;
        RECT  11.76 0 11.784 0.084 ;
    END
  END rec[317]
  PIN rec[318]
    DIRECTION INPUT ;
    USE SIGNAL ;
    PORT
      LAYER M5 ;
        RECT  11.808 0 11.832 0.084 ;
    END
  END rec[318]
  PIN rec[319]
    DIRECTION INPUT ;
    USE SIGNAL ;
    PORT
      LAYER M5 ;
        RECT  19.92 0 19.944 0.084 ;
    END
  END rec[319]
  PIN rec[31]
    DIRECTION INPUT ;
    USE SIGNAL ;
    PORT
      LAYER M5 ;
        RECT  0.72 0 0.744 0.084 ;
    END
  END rec[31]
  PIN rec[320]
    DIRECTION INPUT ;
    USE SIGNAL ;
    PORT
      LAYER M5 ;
        RECT  19.968 0 19.992 0.084 ;
    END
  END rec[320]
  PIN rec[321]
    DIRECTION INPUT ;
    USE SIGNAL ;
    PORT
      LAYER M5 ;
        RECT  20.016 0 20.04 0.084 ;
    END
  END rec[321]
  PIN rec[322]
    DIRECTION INPUT ;
    USE SIGNAL ;
    PORT
      LAYER M5 ;
        RECT  20.064 0 20.088 0.084 ;
    END
  END rec[322]
  PIN rec[323]
    DIRECTION INPUT ;
    USE SIGNAL ;
    PORT
      LAYER M5 ;
        RECT  20.112 0 20.136 0.084 ;
    END
  END rec[323]
  PIN rec[324]
    DIRECTION INPUT ;
    USE SIGNAL ;
    PORT
      LAYER M5 ;
        RECT  20.16 0 20.184 0.084 ;
    END
  END rec[324]
  PIN rec[325]
    DIRECTION INPUT ;
    USE SIGNAL ;
    PORT
      LAYER M5 ;
        RECT  20.208 0 20.232 0.084 ;
    END
  END rec[325]
  PIN rec[326]
    DIRECTION INPUT ;
    USE SIGNAL ;
    PORT
      LAYER M5 ;
        RECT  20.256 0 20.28 0.084 ;
    END
  END rec[326]
  PIN rec[327]
    DIRECTION INPUT ;
    USE SIGNAL ;
    PORT
      LAYER M5 ;
        RECT  20.304 0 20.328 0.084 ;
    END
  END rec[327]
  PIN rec[328]
    DIRECTION INPUT ;
    USE SIGNAL ;
    PORT
      LAYER M5 ;
        RECT  20.352 0 20.376 0.084 ;
    END
  END rec[328]
  PIN rec[329]
    DIRECTION INPUT ;
    USE SIGNAL ;
    PORT
      LAYER M5 ;
        RECT  20.4 0 20.424 0.084 ;
    END
  END rec[329]
  PIN rec[32]
    DIRECTION INPUT ;
    USE SIGNAL ;
    PORT
      LAYER M5 ;
        RECT  0.768 0 0.792 0.084 ;
    END
  END rec[32]
  PIN rec[330]
    DIRECTION INPUT ;
    USE SIGNAL ;
    PORT
      LAYER M5 ;
        RECT  20.448 0 20.472 0.084 ;
    END
  END rec[330]
  PIN rec[331]
    DIRECTION INPUT ;
    USE SIGNAL ;
    PORT
      LAYER M5 ;
        RECT  20.496 0 20.52 0.084 ;
    END
  END rec[331]
  PIN rec[332]
    DIRECTION INPUT ;
    USE SIGNAL ;
    PORT
      LAYER M5 ;
        RECT  20.544 0 20.568 0.084 ;
    END
  END rec[332]
  PIN rec[333]
    DIRECTION INPUT ;
    USE SIGNAL ;
    PORT
      LAYER M5 ;
        RECT  20.592 0 20.616 0.084 ;
    END
  END rec[333]
  PIN rec[334]
    DIRECTION INPUT ;
    USE SIGNAL ;
    PORT
      LAYER M5 ;
        RECT  20.64 0 20.664 0.084 ;
    END
  END rec[334]
  PIN rec[335]
    DIRECTION INPUT ;
    USE SIGNAL ;
    PORT
      LAYER M5 ;
        RECT  20.688 0 20.712 0.084 ;
    END
  END rec[335]
  PIN rec[336]
    DIRECTION INPUT ;
    USE SIGNAL ;
    PORT
      LAYER M5 ;
        RECT  20.736 0 20.76 0.084 ;
    END
  END rec[336]
  PIN rec[337]
    DIRECTION INPUT ;
    USE SIGNAL ;
    PORT
      LAYER M5 ;
        RECT  20.784 0 20.808 0.084 ;
    END
  END rec[337]
  PIN rec[338]
    DIRECTION INPUT ;
    USE SIGNAL ;
    PORT
      LAYER M5 ;
        RECT  20.832 0 20.856 0.084 ;
    END
  END rec[338]
  PIN rec[339]
    DIRECTION INPUT ;
    USE SIGNAL ;
    PORT
      LAYER M5 ;
        RECT  20.88 0 20.904 0.084 ;
    END
  END rec[339]
  PIN rec[33]
    DIRECTION INPUT ;
    USE SIGNAL ;
    PORT
      LAYER M5 ;
        RECT  0.816 0 0.84 0.084 ;
    END
  END rec[33]
  PIN rec[340]
    DIRECTION INPUT ;
    USE SIGNAL ;
    PORT
      LAYER M5 ;
        RECT  20.928 0 20.952 0.084 ;
    END
  END rec[340]
  PIN rec[341]
    DIRECTION INPUT ;
    USE SIGNAL ;
    PORT
      LAYER M5 ;
        RECT  20.976 0 21 0.084 ;
    END
  END rec[341]
  PIN rec[342]
    DIRECTION INPUT ;
    USE SIGNAL ;
    PORT
      LAYER M5 ;
        RECT  21.024 0 21.048 0.084 ;
    END
  END rec[342]
  PIN rec[343]
    DIRECTION INPUT ;
    USE SIGNAL ;
    PORT
      LAYER M5 ;
        RECT  21.072 0 21.096 0.084 ;
    END
  END rec[343]
  PIN rec[344]
    DIRECTION INPUT ;
    USE SIGNAL ;
    PORT
      LAYER M5 ;
        RECT  21.12 0 21.144 0.084 ;
    END
  END rec[344]
  PIN rec[345]
    DIRECTION INPUT ;
    USE SIGNAL ;
    PORT
      LAYER M5 ;
        RECT  21.168 0 21.192 0.084 ;
    END
  END rec[345]
  PIN rec[346]
    DIRECTION INPUT ;
    USE SIGNAL ;
    PORT
      LAYER M5 ;
        RECT  21.216 0 21.24 0.084 ;
    END
  END rec[346]
  PIN rec[347]
    DIRECTION INPUT ;
    USE SIGNAL ;
    PORT
      LAYER M5 ;
        RECT  21.264 0 21.288 0.084 ;
    END
  END rec[347]
  PIN rec[348]
    DIRECTION INPUT ;
    USE SIGNAL ;
    PORT
      LAYER M5 ;
        RECT  21.312 0 21.336 0.084 ;
    END
  END rec[348]
  PIN rec[349]
    DIRECTION INPUT ;
    USE SIGNAL ;
    PORT
      LAYER M5 ;
        RECT  21.36 0 21.384 0.084 ;
    END
  END rec[349]
  PIN rec[34]
    DIRECTION INPUT ;
    USE SIGNAL ;
    PORT
      LAYER M5 ;
        RECT  0.864 0 0.888 0.084 ;
    END
  END rec[34]
  PIN rec[350]
    DIRECTION INPUT ;
    USE SIGNAL ;
    PORT
      LAYER M5 ;
        RECT  21.408 0 21.432 0.084 ;
    END
  END rec[350]
  PIN rec[351]
    DIRECTION INPUT ;
    USE SIGNAL ;
    PORT
      LAYER M5 ;
        RECT  39.12 0 39.144 0.084 ;
    END
  END rec[351]
  PIN rec[352]
    DIRECTION INPUT ;
    USE SIGNAL ;
    PORT
      LAYER M5 ;
        RECT  39.168 0 39.192 0.084 ;
    END
  END rec[352]
  PIN rec[353]
    DIRECTION INPUT ;
    USE SIGNAL ;
    PORT
      LAYER M5 ;
        RECT  39.216 0 39.24 0.084 ;
    END
  END rec[353]
  PIN rec[354]
    DIRECTION INPUT ;
    USE SIGNAL ;
    PORT
      LAYER M5 ;
        RECT  39.264 0 39.288 0.084 ;
    END
  END rec[354]
  PIN rec[355]
    DIRECTION INPUT ;
    USE SIGNAL ;
    PORT
      LAYER M5 ;
        RECT  39.312 0 39.336 0.084 ;
    END
  END rec[355]
  PIN rec[356]
    DIRECTION INPUT ;
    USE SIGNAL ;
    PORT
      LAYER M5 ;
        RECT  39.36 0 39.384 0.084 ;
    END
  END rec[356]
  PIN rec[357]
    DIRECTION INPUT ;
    USE SIGNAL ;
    PORT
      LAYER M5 ;
        RECT  39.408 0 39.432 0.084 ;
    END
  END rec[357]
  PIN rec[358]
    DIRECTION INPUT ;
    USE SIGNAL ;
    PORT
      LAYER M5 ;
        RECT  39.456 0 39.48 0.084 ;
    END
  END rec[358]
  PIN rec[359]
    DIRECTION INPUT ;
    USE SIGNAL ;
    PORT
      LAYER M5 ;
        RECT  39.504 0 39.528 0.084 ;
    END
  END rec[359]
  PIN rec[35]
    DIRECTION INPUT ;
    USE SIGNAL ;
    PORT
      LAYER M5 ;
        RECT  0.912 0 0.936 0.084 ;
    END
  END rec[35]
  PIN rec[360]
    DIRECTION INPUT ;
    USE SIGNAL ;
    PORT
      LAYER M5 ;
        RECT  39.552 0 39.576 0.084 ;
    END
  END rec[360]
  PIN rec[361]
    DIRECTION INPUT ;
    USE SIGNAL ;
    PORT
      LAYER M5 ;
        RECT  39.6 0 39.624 0.084 ;
    END
  END rec[361]
  PIN rec[362]
    DIRECTION INPUT ;
    USE SIGNAL ;
    PORT
      LAYER M5 ;
        RECT  39.648 0 39.672 0.084 ;
    END
  END rec[362]
  PIN rec[363]
    DIRECTION INPUT ;
    USE SIGNAL ;
    PORT
      LAYER M5 ;
        RECT  39.696 0 39.72 0.084 ;
    END
  END rec[363]
  PIN rec[364]
    DIRECTION INPUT ;
    USE SIGNAL ;
    PORT
      LAYER M5 ;
        RECT  39.744 0 39.768 0.084 ;
    END
  END rec[364]
  PIN rec[365]
    DIRECTION INPUT ;
    USE SIGNAL ;
    PORT
      LAYER M5 ;
        RECT  39.792 0 39.816 0.084 ;
    END
  END rec[365]
  PIN rec[366]
    DIRECTION INPUT ;
    USE SIGNAL ;
    PORT
      LAYER M5 ;
        RECT  39.84 0 39.864 0.084 ;
    END
  END rec[366]
  PIN rec[367]
    DIRECTION INPUT ;
    USE SIGNAL ;
    PORT
      LAYER M5 ;
        RECT  39.888 0 39.912 0.084 ;
    END
  END rec[367]
  PIN rec[368]
    DIRECTION INPUT ;
    USE SIGNAL ;
    PORT
      LAYER M5 ;
        RECT  39.936 0 39.96 0.084 ;
    END
  END rec[368]
  PIN rec[369]
    DIRECTION INPUT ;
    USE SIGNAL ;
    PORT
      LAYER M5 ;
        RECT  39.984 0 40.008 0.084 ;
    END
  END rec[369]
  PIN rec[36]
    DIRECTION INPUT ;
    USE SIGNAL ;
    PORT
      LAYER M5 ;
        RECT  0.96 0 0.984 0.084 ;
    END
  END rec[36]
  PIN rec[370]
    DIRECTION INPUT ;
    USE SIGNAL ;
    PORT
      LAYER M5 ;
        RECT  40.032 0 40.056 0.084 ;
    END
  END rec[370]
  PIN rec[371]
    DIRECTION INPUT ;
    USE SIGNAL ;
    PORT
      LAYER M5 ;
        RECT  40.08 0 40.104 0.084 ;
    END
  END rec[371]
  PIN rec[372]
    DIRECTION INPUT ;
    USE SIGNAL ;
    PORT
      LAYER M5 ;
        RECT  40.128 0 40.152 0.084 ;
    END
  END rec[372]
  PIN rec[373]
    DIRECTION INPUT ;
    USE SIGNAL ;
    PORT
      LAYER M5 ;
        RECT  40.176 0 40.2 0.084 ;
    END
  END rec[373]
  PIN rec[374]
    DIRECTION INPUT ;
    USE SIGNAL ;
    PORT
      LAYER M5 ;
        RECT  40.224 0 40.248 0.084 ;
    END
  END rec[374]
  PIN rec[375]
    DIRECTION INPUT ;
    USE SIGNAL ;
    PORT
      LAYER M5 ;
        RECT  40.272 0 40.296 0.084 ;
    END
  END rec[375]
  PIN rec[376]
    DIRECTION INPUT ;
    USE SIGNAL ;
    PORT
      LAYER M5 ;
        RECT  40.32 0 40.344 0.084 ;
    END
  END rec[376]
  PIN rec[377]
    DIRECTION INPUT ;
    USE SIGNAL ;
    PORT
      LAYER M5 ;
        RECT  40.368 0 40.392 0.084 ;
    END
  END rec[377]
  PIN rec[378]
    DIRECTION INPUT ;
    USE SIGNAL ;
    PORT
      LAYER M5 ;
        RECT  40.416 0 40.44 0.084 ;
    END
  END rec[378]
  PIN rec[379]
    DIRECTION INPUT ;
    USE SIGNAL ;
    PORT
      LAYER M5 ;
        RECT  40.464 0 40.488 0.084 ;
    END
  END rec[379]
  PIN rec[37]
    DIRECTION INPUT ;
    USE SIGNAL ;
    PORT
      LAYER M5 ;
        RECT  1.008 0 1.032 0.084 ;
    END
  END rec[37]
  PIN rec[380]
    DIRECTION INPUT ;
    USE SIGNAL ;
    PORT
      LAYER M5 ;
        RECT  40.512 0 40.536 0.084 ;
    END
  END rec[380]
  PIN rec[381]
    DIRECTION INPUT ;
    USE SIGNAL ;
    PORT
      LAYER M5 ;
        RECT  40.56 0 40.584 0.084 ;
    END
  END rec[381]
  PIN rec[382]
    DIRECTION INPUT ;
    USE SIGNAL ;
    PORT
      LAYER M5 ;
        RECT  40.608 0 40.632 0.084 ;
    END
  END rec[382]
  PIN rec[383]
    DIRECTION INPUT ;
    USE SIGNAL ;
    PORT
      LAYER M5 ;
        RECT  53.328 0 53.352 0.084 ;
    END
  END rec[383]
  PIN rec[384]
    DIRECTION INPUT ;
    USE SIGNAL ;
    PORT
      LAYER M5 ;
        RECT  53.376 0 53.4 0.084 ;
    END
  END rec[384]
  PIN rec[385]
    DIRECTION INPUT ;
    USE SIGNAL ;
    PORT
      LAYER M5 ;
        RECT  53.424 0 53.448 0.084 ;
    END
  END rec[385]
  PIN rec[386]
    DIRECTION INPUT ;
    USE SIGNAL ;
    PORT
      LAYER M5 ;
        RECT  53.472 0 53.496 0.084 ;
    END
  END rec[386]
  PIN rec[387]
    DIRECTION INPUT ;
    USE SIGNAL ;
    PORT
      LAYER M5 ;
        RECT  53.52 0 53.544 0.084 ;
    END
  END rec[387]
  PIN rec[388]
    DIRECTION INPUT ;
    USE SIGNAL ;
    PORT
      LAYER M5 ;
        RECT  53.568 0 53.592 0.084 ;
    END
  END rec[388]
  PIN rec[389]
    DIRECTION INPUT ;
    USE SIGNAL ;
    PORT
      LAYER M5 ;
        RECT  53.616 0 53.64 0.084 ;
    END
  END rec[389]
  PIN rec[38]
    DIRECTION INPUT ;
    USE SIGNAL ;
    PORT
      LAYER M5 ;
        RECT  1.056 0 1.08 0.084 ;
    END
  END rec[38]
  PIN rec[390]
    DIRECTION INPUT ;
    USE SIGNAL ;
    PORT
      LAYER M5 ;
        RECT  53.664 0 53.688 0.084 ;
    END
  END rec[390]
  PIN rec[391]
    DIRECTION INPUT ;
    USE SIGNAL ;
    PORT
      LAYER M5 ;
        RECT  53.712 0 53.736 0.084 ;
    END
  END rec[391]
  PIN rec[392]
    DIRECTION INPUT ;
    USE SIGNAL ;
    PORT
      LAYER M5 ;
        RECT  53.76 0 53.784 0.084 ;
    END
  END rec[392]
  PIN rec[393]
    DIRECTION INPUT ;
    USE SIGNAL ;
    PORT
      LAYER M5 ;
        RECT  53.808 0 53.832 0.084 ;
    END
  END rec[393]
  PIN rec[394]
    DIRECTION INPUT ;
    USE SIGNAL ;
    PORT
      LAYER M5 ;
        RECT  53.856 0 53.88 0.084 ;
    END
  END rec[394]
  PIN rec[395]
    DIRECTION INPUT ;
    USE SIGNAL ;
    PORT
      LAYER M5 ;
        RECT  53.904 0 53.928 0.084 ;
    END
  END rec[395]
  PIN rec[396]
    DIRECTION INPUT ;
    USE SIGNAL ;
    PORT
      LAYER M5 ;
        RECT  53.952 0 53.976 0.084 ;
    END
  END rec[396]
  PIN rec[397]
    DIRECTION INPUT ;
    USE SIGNAL ;
    PORT
      LAYER M5 ;
        RECT  54 0 54.024 0.084 ;
    END
  END rec[397]
  PIN rec[398]
    DIRECTION INPUT ;
    USE SIGNAL ;
    PORT
      LAYER M5 ;
        RECT  54.048 0 54.072 0.084 ;
    END
  END rec[398]
  PIN rec[399]
    DIRECTION INPUT ;
    USE SIGNAL ;
    PORT
      LAYER M5 ;
        RECT  54.096 0 54.12 0.084 ;
    END
  END rec[399]
  PIN rec[39]
    DIRECTION INPUT ;
    USE SIGNAL ;
    PORT
      LAYER M5 ;
        RECT  1.104 0 1.128 0.084 ;
    END
  END rec[39]
  PIN rec[3]
    DIRECTION INPUT ;
    USE SIGNAL ;
    PORT
      LAYER M5 ;
        RECT  32.784 0 32.808 0.084 ;
    END
  END rec[3]
  PIN rec[400]
    DIRECTION INPUT ;
    USE SIGNAL ;
    PORT
      LAYER M5 ;
        RECT  54.144 0 54.168 0.084 ;
    END
  END rec[400]
  PIN rec[401]
    DIRECTION INPUT ;
    USE SIGNAL ;
    PORT
      LAYER M5 ;
        RECT  54.192 0 54.216 0.084 ;
    END
  END rec[401]
  PIN rec[402]
    DIRECTION INPUT ;
    USE SIGNAL ;
    PORT
      LAYER M5 ;
        RECT  54.24 0 54.264 0.084 ;
    END
  END rec[402]
  PIN rec[403]
    DIRECTION INPUT ;
    USE SIGNAL ;
    PORT
      LAYER M5 ;
        RECT  54.288 0 54.312 0.084 ;
    END
  END rec[403]
  PIN rec[404]
    DIRECTION INPUT ;
    USE SIGNAL ;
    PORT
      LAYER M5 ;
        RECT  54.336 0 54.36 0.084 ;
    END
  END rec[404]
  PIN rec[405]
    DIRECTION INPUT ;
    USE SIGNAL ;
    PORT
      LAYER M5 ;
        RECT  54.384 0 54.408 0.084 ;
    END
  END rec[405]
  PIN rec[406]
    DIRECTION INPUT ;
    USE SIGNAL ;
    PORT
      LAYER M5 ;
        RECT  54.432 0 54.456 0.084 ;
    END
  END rec[406]
  PIN rec[407]
    DIRECTION INPUT ;
    USE SIGNAL ;
    PORT
      LAYER M5 ;
        RECT  54.48 0 54.504 0.084 ;
    END
  END rec[407]
  PIN rec[408]
    DIRECTION INPUT ;
    USE SIGNAL ;
    PORT
      LAYER M5 ;
        RECT  54.528 0 54.552 0.084 ;
    END
  END rec[408]
  PIN rec[409]
    DIRECTION INPUT ;
    USE SIGNAL ;
    PORT
      LAYER M5 ;
        RECT  54.576 0 54.6 0.084 ;
    END
  END rec[409]
  PIN rec[40]
    DIRECTION INPUT ;
    USE SIGNAL ;
    PORT
      LAYER M5 ;
        RECT  1.152 0 1.176 0.084 ;
    END
  END rec[40]
  PIN rec[410]
    DIRECTION INPUT ;
    USE SIGNAL ;
    PORT
      LAYER M5 ;
        RECT  54.624 0 54.648 0.084 ;
    END
  END rec[410]
  PIN rec[411]
    DIRECTION INPUT ;
    USE SIGNAL ;
    PORT
      LAYER M5 ;
        RECT  54.672 0 54.696 0.084 ;
    END
  END rec[411]
  PIN rec[412]
    DIRECTION INPUT ;
    USE SIGNAL ;
    PORT
      LAYER M5 ;
        RECT  54.72 0 54.744 0.084 ;
    END
  END rec[412]
  PIN rec[413]
    DIRECTION INPUT ;
    USE SIGNAL ;
    PORT
      LAYER M5 ;
        RECT  54.768 0 54.792 0.084 ;
    END
  END rec[413]
  PIN rec[414]
    DIRECTION INPUT ;
    USE SIGNAL ;
    PORT
      LAYER M5 ;
        RECT  54.816 0 54.84 0.084 ;
    END
  END rec[414]
  PIN rec[415]
    DIRECTION INPUT ;
    USE SIGNAL ;
    PORT
      LAYER M5 ;
        RECT  58.32 0 58.344 0.084 ;
    END
  END rec[415]
  PIN rec[416]
    DIRECTION INPUT ;
    USE SIGNAL ;
    PORT
      LAYER M5 ;
        RECT  58.368 0 58.392 0.084 ;
    END
  END rec[416]
  PIN rec[417]
    DIRECTION INPUT ;
    USE SIGNAL ;
    PORT
      LAYER M5 ;
        RECT  58.416 0 58.44 0.084 ;
    END
  END rec[417]
  PIN rec[418]
    DIRECTION INPUT ;
    USE SIGNAL ;
    PORT
      LAYER M5 ;
        RECT  58.464 0 58.488 0.084 ;
    END
  END rec[418]
  PIN rec[419]
    DIRECTION INPUT ;
    USE SIGNAL ;
    PORT
      LAYER M5 ;
        RECT  58.512 0 58.536 0.084 ;
    END
  END rec[419]
  PIN rec[41]
    DIRECTION INPUT ;
    USE SIGNAL ;
    PORT
      LAYER M5 ;
        RECT  1.2 0 1.224 0.084 ;
    END
  END rec[41]
  PIN rec[420]
    DIRECTION INPUT ;
    USE SIGNAL ;
    PORT
      LAYER M5 ;
        RECT  58.56 0 58.584 0.084 ;
    END
  END rec[420]
  PIN rec[421]
    DIRECTION INPUT ;
    USE SIGNAL ;
    PORT
      LAYER M5 ;
        RECT  58.608 0 58.632 0.084 ;
    END
  END rec[421]
  PIN rec[422]
    DIRECTION INPUT ;
    USE SIGNAL ;
    PORT
      LAYER M5 ;
        RECT  58.656 0 58.68 0.084 ;
    END
  END rec[422]
  PIN rec[423]
    DIRECTION INPUT ;
    USE SIGNAL ;
    PORT
      LAYER M5 ;
        RECT  58.704 0 58.728 0.084 ;
    END
  END rec[423]
  PIN rec[424]
    DIRECTION INPUT ;
    USE SIGNAL ;
    PORT
      LAYER M5 ;
        RECT  58.752 0 58.776 0.084 ;
    END
  END rec[424]
  PIN rec[425]
    DIRECTION INPUT ;
    USE SIGNAL ;
    PORT
      LAYER M5 ;
        RECT  58.8 0 58.824 0.084 ;
    END
  END rec[425]
  PIN rec[426]
    DIRECTION INPUT ;
    USE SIGNAL ;
    PORT
      LAYER M5 ;
        RECT  58.848 0 58.872 0.084 ;
    END
  END rec[426]
  PIN rec[427]
    DIRECTION INPUT ;
    USE SIGNAL ;
    PORT
      LAYER M5 ;
        RECT  58.896 0 58.92 0.084 ;
    END
  END rec[427]
  PIN rec[428]
    DIRECTION INPUT ;
    USE SIGNAL ;
    PORT
      LAYER M5 ;
        RECT  58.944 0 58.968 0.084 ;
    END
  END rec[428]
  PIN rec[429]
    DIRECTION INPUT ;
    USE SIGNAL ;
    PORT
      LAYER M5 ;
        RECT  58.992 0 59.016 0.084 ;
    END
  END rec[429]
  PIN rec[42]
    DIRECTION INPUT ;
    USE SIGNAL ;
    PORT
      LAYER M5 ;
        RECT  1.248 0 1.272 0.084 ;
    END
  END rec[42]
  PIN rec[430]
    DIRECTION INPUT ;
    USE SIGNAL ;
    PORT
      LAYER M5 ;
        RECT  59.04 0 59.064 0.084 ;
    END
  END rec[430]
  PIN rec[431]
    DIRECTION INPUT ;
    USE SIGNAL ;
    PORT
      LAYER M5 ;
        RECT  59.088 0 59.112 0.084 ;
    END
  END rec[431]
  PIN rec[432]
    DIRECTION INPUT ;
    USE SIGNAL ;
    PORT
      LAYER M5 ;
        RECT  59.136 0 59.16 0.084 ;
    END
  END rec[432]
  PIN rec[433]
    DIRECTION INPUT ;
    USE SIGNAL ;
    PORT
      LAYER M5 ;
        RECT  59.184 0 59.208 0.084 ;
    END
  END rec[433]
  PIN rec[434]
    DIRECTION INPUT ;
    USE SIGNAL ;
    PORT
      LAYER M5 ;
        RECT  59.232 0 59.256 0.084 ;
    END
  END rec[434]
  PIN rec[435]
    DIRECTION INPUT ;
    USE SIGNAL ;
    PORT
      LAYER M5 ;
        RECT  59.28 0 59.304 0.084 ;
    END
  END rec[435]
  PIN rec[436]
    DIRECTION INPUT ;
    USE SIGNAL ;
    PORT
      LAYER M5 ;
        RECT  59.328 0 59.352 0.084 ;
    END
  END rec[436]
  PIN rec[437]
    DIRECTION INPUT ;
    USE SIGNAL ;
    PORT
      LAYER M5 ;
        RECT  59.376 0 59.4 0.084 ;
    END
  END rec[437]
  PIN rec[438]
    DIRECTION INPUT ;
    USE SIGNAL ;
    PORT
      LAYER M5 ;
        RECT  59.424 0 59.448 0.084 ;
    END
  END rec[438]
  PIN rec[439]
    DIRECTION INPUT ;
    USE SIGNAL ;
    PORT
      LAYER M5 ;
        RECT  59.472 0 59.496 0.084 ;
    END
  END rec[439]
  PIN rec[43]
    DIRECTION INPUT ;
    USE SIGNAL ;
    PORT
      LAYER M5 ;
        RECT  1.296 0 1.32 0.084 ;
    END
  END rec[43]
  PIN rec[440]
    DIRECTION INPUT ;
    USE SIGNAL ;
    PORT
      LAYER M5 ;
        RECT  59.52 0 59.544 0.084 ;
    END
  END rec[440]
  PIN rec[441]
    DIRECTION INPUT ;
    USE SIGNAL ;
    PORT
      LAYER M5 ;
        RECT  59.568 0 59.592 0.084 ;
    END
  END rec[441]
  PIN rec[442]
    DIRECTION INPUT ;
    USE SIGNAL ;
    PORT
      LAYER M5 ;
        RECT  59.616 0 59.64 0.084 ;
    END
  END rec[442]
  PIN rec[443]
    DIRECTION INPUT ;
    USE SIGNAL ;
    PORT
      LAYER M5 ;
        RECT  59.664 0 59.688 0.084 ;
    END
  END rec[443]
  PIN rec[444]
    DIRECTION INPUT ;
    USE SIGNAL ;
    PORT
      LAYER M5 ;
        RECT  59.712 0 59.736 0.084 ;
    END
  END rec[444]
  PIN rec[445]
    DIRECTION INPUT ;
    USE SIGNAL ;
    PORT
      LAYER M5 ;
        RECT  59.76 0 59.784 0.084 ;
    END
  END rec[445]
  PIN rec[446]
    DIRECTION INPUT ;
    USE SIGNAL ;
    PORT
      LAYER M5 ;
        RECT  59.808 0 59.832 0.084 ;
    END
  END rec[446]
  PIN rec[447]
    DIRECTION INPUT ;
    USE SIGNAL ;
    PORT
      LAYER M5 ;
        RECT  46.8 0 46.824 0.084 ;
    END
  END rec[447]
  PIN rec[448]
    DIRECTION INPUT ;
    USE SIGNAL ;
    PORT
      LAYER M5 ;
        RECT  46.848 0 46.872 0.084 ;
    END
  END rec[448]
  PIN rec[449]
    DIRECTION INPUT ;
    USE SIGNAL ;
    PORT
      LAYER M5 ;
        RECT  46.896 0 46.92 0.084 ;
    END
  END rec[449]
  PIN rec[44]
    DIRECTION INPUT ;
    USE SIGNAL ;
    PORT
      LAYER M5 ;
        RECT  1.344 0 1.368 0.084 ;
    END
  END rec[44]
  PIN rec[450]
    DIRECTION INPUT ;
    USE SIGNAL ;
    PORT
      LAYER M5 ;
        RECT  46.944 0 46.968 0.084 ;
    END
  END rec[450]
  PIN rec[451]
    DIRECTION INPUT ;
    USE SIGNAL ;
    PORT
      LAYER M5 ;
        RECT  46.992 0 47.016 0.084 ;
    END
  END rec[451]
  PIN rec[452]
    DIRECTION INPUT ;
    USE SIGNAL ;
    PORT
      LAYER M5 ;
        RECT  47.04 0 47.064 0.084 ;
    END
  END rec[452]
  PIN rec[453]
    DIRECTION INPUT ;
    USE SIGNAL ;
    PORT
      LAYER M5 ;
        RECT  47.088 0 47.112 0.084 ;
    END
  END rec[453]
  PIN rec[454]
    DIRECTION INPUT ;
    USE SIGNAL ;
    PORT
      LAYER M5 ;
        RECT  47.136 0 47.16 0.084 ;
    END
  END rec[454]
  PIN rec[455]
    DIRECTION INPUT ;
    USE SIGNAL ;
    PORT
      LAYER M5 ;
        RECT  47.184 0 47.208 0.084 ;
    END
  END rec[455]
  PIN rec[456]
    DIRECTION INPUT ;
    USE SIGNAL ;
    PORT
      LAYER M5 ;
        RECT  47.232 0 47.256 0.084 ;
    END
  END rec[456]
  PIN rec[457]
    DIRECTION INPUT ;
    USE SIGNAL ;
    PORT
      LAYER M5 ;
        RECT  47.28 0 47.304 0.084 ;
    END
  END rec[457]
  PIN rec[458]
    DIRECTION INPUT ;
    USE SIGNAL ;
    PORT
      LAYER M5 ;
        RECT  47.328 0 47.352 0.084 ;
    END
  END rec[458]
  PIN rec[459]
    DIRECTION INPUT ;
    USE SIGNAL ;
    PORT
      LAYER M5 ;
        RECT  47.376 0 47.4 0.084 ;
    END
  END rec[459]
  PIN rec[45]
    DIRECTION INPUT ;
    USE SIGNAL ;
    PORT
      LAYER M5 ;
        RECT  1.392 0 1.416 0.084 ;
    END
  END rec[45]
  PIN rec[460]
    DIRECTION INPUT ;
    USE SIGNAL ;
    PORT
      LAYER M5 ;
        RECT  47.424 0 47.448 0.084 ;
    END
  END rec[460]
  PIN rec[461]
    DIRECTION INPUT ;
    USE SIGNAL ;
    PORT
      LAYER M5 ;
        RECT  47.472 0 47.496 0.084 ;
    END
  END rec[461]
  PIN rec[462]
    DIRECTION INPUT ;
    USE SIGNAL ;
    PORT
      LAYER M5 ;
        RECT  47.52 0 47.544 0.084 ;
    END
  END rec[462]
  PIN rec[463]
    DIRECTION INPUT ;
    USE SIGNAL ;
    PORT
      LAYER M5 ;
        RECT  47.568 0 47.592 0.084 ;
    END
  END rec[463]
  PIN rec[464]
    DIRECTION INPUT ;
    USE SIGNAL ;
    PORT
      LAYER M5 ;
        RECT  47.616 0 47.64 0.084 ;
    END
  END rec[464]
  PIN rec[465]
    DIRECTION INPUT ;
    USE SIGNAL ;
    PORT
      LAYER M5 ;
        RECT  47.664 0 47.688 0.084 ;
    END
  END rec[465]
  PIN rec[466]
    DIRECTION INPUT ;
    USE SIGNAL ;
    PORT
      LAYER M5 ;
        RECT  47.712 0 47.736 0.084 ;
    END
  END rec[466]
  PIN rec[467]
    DIRECTION INPUT ;
    USE SIGNAL ;
    PORT
      LAYER M5 ;
        RECT  47.76 0 47.784 0.084 ;
    END
  END rec[467]
  PIN rec[468]
    DIRECTION INPUT ;
    USE SIGNAL ;
    PORT
      LAYER M5 ;
        RECT  47.808 0 47.832 0.084 ;
    END
  END rec[468]
  PIN rec[469]
    DIRECTION INPUT ;
    USE SIGNAL ;
    PORT
      LAYER M5 ;
        RECT  47.856 0 47.88 0.084 ;
    END
  END rec[469]
  PIN rec[46]
    DIRECTION INPUT ;
    USE SIGNAL ;
    PORT
      LAYER M5 ;
        RECT  1.44 0 1.464 0.084 ;
    END
  END rec[46]
  PIN rec[470]
    DIRECTION INPUT ;
    USE SIGNAL ;
    PORT
      LAYER M5 ;
        RECT  47.904 0 47.928 0.084 ;
    END
  END rec[470]
  PIN rec[471]
    DIRECTION INPUT ;
    USE SIGNAL ;
    PORT
      LAYER M5 ;
        RECT  47.952 0 47.976 0.084 ;
    END
  END rec[471]
  PIN rec[472]
    DIRECTION INPUT ;
    USE SIGNAL ;
    PORT
      LAYER M5 ;
        RECT  48 0 48.024 0.084 ;
    END
  END rec[472]
  PIN rec[473]
    DIRECTION INPUT ;
    USE SIGNAL ;
    PORT
      LAYER M5 ;
        RECT  48.048 0 48.072 0.084 ;
    END
  END rec[473]
  PIN rec[474]
    DIRECTION INPUT ;
    USE SIGNAL ;
    PORT
      LAYER M5 ;
        RECT  48.096 0 48.12 0.084 ;
    END
  END rec[474]
  PIN rec[475]
    DIRECTION INPUT ;
    USE SIGNAL ;
    PORT
      LAYER M5 ;
        RECT  48.144 0 48.168 0.084 ;
    END
  END rec[475]
  PIN rec[476]
    DIRECTION INPUT ;
    USE SIGNAL ;
    PORT
      LAYER M5 ;
        RECT  48.192 0 48.216 0.084 ;
    END
  END rec[476]
  PIN rec[477]
    DIRECTION INPUT ;
    USE SIGNAL ;
    PORT
      LAYER M5 ;
        RECT  48.24 0 48.264 0.084 ;
    END
  END rec[477]
  PIN rec[478]
    DIRECTION INPUT ;
    USE SIGNAL ;
    PORT
      LAYER M5 ;
        RECT  48.288 0 48.312 0.084 ;
    END
  END rec[478]
  PIN rec[479]
    DIRECTION INPUT ;
    USE SIGNAL ;
    PORT
      LAYER M5 ;
        RECT  70.992 0 71.016 0.084 ;
    END
  END rec[479]
  PIN rec[47]
    DIRECTION INPUT ;
    USE SIGNAL ;
    PORT
      LAYER M5 ;
        RECT  1.488 0 1.512 0.084 ;
    END
  END rec[47]
  PIN rec[480]
    DIRECTION INPUT ;
    USE SIGNAL ;
    PORT
      LAYER M5 ;
        RECT  71.04 0 71.064 0.084 ;
    END
  END rec[480]
  PIN rec[481]
    DIRECTION INPUT ;
    USE SIGNAL ;
    PORT
      LAYER M5 ;
        RECT  71.088 0 71.112 0.084 ;
    END
  END rec[481]
  PIN rec[482]
    DIRECTION INPUT ;
    USE SIGNAL ;
    PORT
      LAYER M5 ;
        RECT  71.136 0 71.16 0.084 ;
    END
  END rec[482]
  PIN rec[483]
    DIRECTION INPUT ;
    USE SIGNAL ;
    PORT
      LAYER M5 ;
        RECT  71.184 0 71.208 0.084 ;
    END
  END rec[483]
  PIN rec[484]
    DIRECTION INPUT ;
    USE SIGNAL ;
    PORT
      LAYER M5 ;
        RECT  71.232 0 71.256 0.084 ;
    END
  END rec[484]
  PIN rec[485]
    DIRECTION INPUT ;
    USE SIGNAL ;
    PORT
      LAYER M5 ;
        RECT  71.28 0 71.304 0.084 ;
    END
  END rec[485]
  PIN rec[486]
    DIRECTION INPUT ;
    USE SIGNAL ;
    PORT
      LAYER M5 ;
        RECT  71.328 0 71.352 0.084 ;
    END
  END rec[486]
  PIN rec[487]
    DIRECTION INPUT ;
    USE SIGNAL ;
    PORT
      LAYER M5 ;
        RECT  71.376 0 71.4 0.084 ;
    END
  END rec[487]
  PIN rec[488]
    DIRECTION INPUT ;
    USE SIGNAL ;
    PORT
      LAYER M5 ;
        RECT  71.424 0 71.448 0.084 ;
    END
  END rec[488]
  PIN rec[489]
    DIRECTION INPUT ;
    USE SIGNAL ;
    PORT
      LAYER M5 ;
        RECT  71.472 0 71.496 0.084 ;
    END
  END rec[489]
  PIN rec[48]
    DIRECTION INPUT ;
    USE SIGNAL ;
    PORT
      LAYER M5 ;
        RECT  1.536 0 1.56 0.084 ;
    END
  END rec[48]
  PIN rec[490]
    DIRECTION INPUT ;
    USE SIGNAL ;
    PORT
      LAYER M5 ;
        RECT  71.52 0 71.544 0.084 ;
    END
  END rec[490]
  PIN rec[491]
    DIRECTION INPUT ;
    USE SIGNAL ;
    PORT
      LAYER M5 ;
        RECT  71.568 0 71.592 0.084 ;
    END
  END rec[491]
  PIN rec[492]
    DIRECTION INPUT ;
    USE SIGNAL ;
    PORT
      LAYER M5 ;
        RECT  71.616 0 71.64 0.084 ;
    END
  END rec[492]
  PIN rec[493]
    DIRECTION INPUT ;
    USE SIGNAL ;
    PORT
      LAYER M5 ;
        RECT  71.664 0 71.688 0.084 ;
    END
  END rec[493]
  PIN rec[494]
    DIRECTION INPUT ;
    USE SIGNAL ;
    PORT
      LAYER M5 ;
        RECT  71.712 0 71.736 0.084 ;
    END
  END rec[494]
  PIN rec[495]
    DIRECTION INPUT ;
    USE SIGNAL ;
    PORT
      LAYER M5 ;
        RECT  71.76 0 71.784 0.084 ;
    END
  END rec[495]
  PIN rec[496]
    DIRECTION INPUT ;
    USE SIGNAL ;
    PORT
      LAYER M5 ;
        RECT  71.808 0 71.832 0.084 ;
    END
  END rec[496]
  PIN rec[497]
    DIRECTION INPUT ;
    USE SIGNAL ;
    PORT
      LAYER M5 ;
        RECT  71.856 0 71.88 0.084 ;
    END
  END rec[497]
  PIN rec[498]
    DIRECTION INPUT ;
    USE SIGNAL ;
    PORT
      LAYER M5 ;
        RECT  71.904 0 71.928 0.084 ;
    END
  END rec[498]
  PIN rec[499]
    DIRECTION INPUT ;
    USE SIGNAL ;
    PORT
      LAYER M5 ;
        RECT  71.952 0 71.976 0.084 ;
    END
  END rec[499]
  PIN rec[49]
    DIRECTION INPUT ;
    USE SIGNAL ;
    PORT
      LAYER M5 ;
        RECT  1.584 0 1.608 0.084 ;
    END
  END rec[49]
  PIN rec[4]
    DIRECTION INPUT ;
    USE SIGNAL ;
    PORT
      LAYER M5 ;
        RECT  32.832 0 32.856 0.084 ;
    END
  END rec[4]
  PIN rec[500]
    DIRECTION INPUT ;
    USE SIGNAL ;
    PORT
      LAYER M5 ;
        RECT  72 0 72.024 0.084 ;
    END
  END rec[500]
  PIN rec[501]
    DIRECTION INPUT ;
    USE SIGNAL ;
    PORT
      LAYER M5 ;
        RECT  72.048 0 72.072 0.084 ;
    END
  END rec[501]
  PIN rec[502]
    DIRECTION INPUT ;
    USE SIGNAL ;
    PORT
      LAYER M5 ;
        RECT  72.096 0 72.12 0.084 ;
    END
  END rec[502]
  PIN rec[503]
    DIRECTION INPUT ;
    USE SIGNAL ;
    PORT
      LAYER M5 ;
        RECT  72.144 0 72.168 0.084 ;
    END
  END rec[503]
  PIN rec[504]
    DIRECTION INPUT ;
    USE SIGNAL ;
    PORT
      LAYER M5 ;
        RECT  72.192 0 72.216 0.084 ;
    END
  END rec[504]
  PIN rec[505]
    DIRECTION INPUT ;
    USE SIGNAL ;
    PORT
      LAYER M5 ;
        RECT  72.24 0 72.264 0.084 ;
    END
  END rec[505]
  PIN rec[506]
    DIRECTION INPUT ;
    USE SIGNAL ;
    PORT
      LAYER M5 ;
        RECT  72.288 0 72.312 0.084 ;
    END
  END rec[506]
  PIN rec[507]
    DIRECTION INPUT ;
    USE SIGNAL ;
    PORT
      LAYER M5 ;
        RECT  72.336 0 72.36 0.084 ;
    END
  END rec[507]
  PIN rec[508]
    DIRECTION INPUT ;
    USE SIGNAL ;
    PORT
      LAYER M5 ;
        RECT  72.384 0 72.408 0.084 ;
    END
  END rec[508]
  PIN rec[509]
    DIRECTION INPUT ;
    USE SIGNAL ;
    PORT
      LAYER M5 ;
        RECT  72.432 0 72.456 0.084 ;
    END
  END rec[509]
  PIN rec[50]
    DIRECTION INPUT ;
    USE SIGNAL ;
    PORT
      LAYER M5 ;
        RECT  1.632 0 1.656 0.084 ;
    END
  END rec[50]
  PIN rec[510]
    DIRECTION INPUT ;
    USE SIGNAL ;
    PORT
      LAYER M5 ;
        RECT  72.48 0 72.504 0.084 ;
    END
  END rec[510]
  PIN rec[511]
    DIRECTION INPUT ;
    USE SIGNAL ;
    PORT
      LAYER M5 ;
        RECT  31.056 0 31.08 0.084 ;
    END
  END rec[511]
  PIN rec[512]
    DIRECTION INPUT ;
    USE SIGNAL ;
    PORT
      LAYER M5 ;
        RECT  31.104 0 31.128 0.084 ;
    END
  END rec[512]
  PIN rec[513]
    DIRECTION INPUT ;
    USE SIGNAL ;
    PORT
      LAYER M5 ;
        RECT  31.152 0 31.176 0.084 ;
    END
  END rec[513]
  PIN rec[514]
    DIRECTION INPUT ;
    USE SIGNAL ;
    PORT
      LAYER M5 ;
        RECT  31.2 0 31.224 0.084 ;
    END
  END rec[514]
  PIN rec[515]
    DIRECTION INPUT ;
    USE SIGNAL ;
    PORT
      LAYER M5 ;
        RECT  31.248 0 31.272 0.084 ;
    END
  END rec[515]
  PIN rec[516]
    DIRECTION INPUT ;
    USE SIGNAL ;
    PORT
      LAYER M5 ;
        RECT  31.296 0 31.32 0.084 ;
    END
  END rec[516]
  PIN rec[517]
    DIRECTION INPUT ;
    USE SIGNAL ;
    PORT
      LAYER M5 ;
        RECT  31.344 0 31.368 0.084 ;
    END
  END rec[517]
  PIN rec[518]
    DIRECTION INPUT ;
    USE SIGNAL ;
    PORT
      LAYER M5 ;
        RECT  31.392 0 31.416 0.084 ;
    END
  END rec[518]
  PIN rec[519]
    DIRECTION INPUT ;
    USE SIGNAL ;
    PORT
      LAYER M5 ;
        RECT  31.44 0 31.464 0.084 ;
    END
  END rec[519]
  PIN rec[51]
    DIRECTION INPUT ;
    USE SIGNAL ;
    PORT
      LAYER M5 ;
        RECT  1.68 0 1.704 0.084 ;
    END
  END rec[51]
  PIN rec[520]
    DIRECTION INPUT ;
    USE SIGNAL ;
    PORT
      LAYER M5 ;
        RECT  31.488 0 31.512 0.084 ;
    END
  END rec[520]
  PIN rec[521]
    DIRECTION INPUT ;
    USE SIGNAL ;
    PORT
      LAYER M5 ;
        RECT  31.536 0 31.56 0.084 ;
    END
  END rec[521]
  PIN rec[522]
    DIRECTION INPUT ;
    USE SIGNAL ;
    PORT
      LAYER M5 ;
        RECT  31.584 0 31.608 0.084 ;
    END
  END rec[522]
  PIN rec[523]
    DIRECTION INPUT ;
    USE SIGNAL ;
    PORT
      LAYER M5 ;
        RECT  31.632 0 31.656 0.084 ;
    END
  END rec[523]
  PIN rec[524]
    DIRECTION INPUT ;
    USE SIGNAL ;
    PORT
      LAYER M5 ;
        RECT  31.68 0 31.704 0.084 ;
    END
  END rec[524]
  PIN rec[525]
    DIRECTION INPUT ;
    USE SIGNAL ;
    PORT
      LAYER M5 ;
        RECT  31.728 0 31.752 0.084 ;
    END
  END rec[525]
  PIN rec[526]
    DIRECTION INPUT ;
    USE SIGNAL ;
    PORT
      LAYER M5 ;
        RECT  31.776 0 31.8 0.084 ;
    END
  END rec[526]
  PIN rec[527]
    DIRECTION INPUT ;
    USE SIGNAL ;
    PORT
      LAYER M5 ;
        RECT  31.824 0 31.848 0.084 ;
    END
  END rec[527]
  PIN rec[528]
    DIRECTION INPUT ;
    USE SIGNAL ;
    PORT
      LAYER M5 ;
        RECT  31.872 0 31.896 0.084 ;
    END
  END rec[528]
  PIN rec[529]
    DIRECTION INPUT ;
    USE SIGNAL ;
    PORT
      LAYER M5 ;
        RECT  31.92 0 31.944 0.084 ;
    END
  END rec[529]
  PIN rec[52]
    DIRECTION INPUT ;
    USE SIGNAL ;
    PORT
      LAYER M5 ;
        RECT  1.728 0 1.752 0.084 ;
    END
  END rec[52]
  PIN rec[530]
    DIRECTION INPUT ;
    USE SIGNAL ;
    PORT
      LAYER M5 ;
        RECT  31.968 0 31.992 0.084 ;
    END
  END rec[530]
  PIN rec[531]
    DIRECTION INPUT ;
    USE SIGNAL ;
    PORT
      LAYER M5 ;
        RECT  32.016 0 32.04 0.084 ;
    END
  END rec[531]
  PIN rec[532]
    DIRECTION INPUT ;
    USE SIGNAL ;
    PORT
      LAYER M5 ;
        RECT  32.064 0 32.088 0.084 ;
    END
  END rec[532]
  PIN rec[533]
    DIRECTION INPUT ;
    USE SIGNAL ;
    PORT
      LAYER M5 ;
        RECT  32.112 0 32.136 0.084 ;
    END
  END rec[533]
  PIN rec[534]
    DIRECTION INPUT ;
    USE SIGNAL ;
    PORT
      LAYER M5 ;
        RECT  32.16 0 32.184 0.084 ;
    END
  END rec[534]
  PIN rec[535]
    DIRECTION INPUT ;
    USE SIGNAL ;
    PORT
      LAYER M5 ;
        RECT  32.208 0 32.232 0.084 ;
    END
  END rec[535]
  PIN rec[536]
    DIRECTION INPUT ;
    USE SIGNAL ;
    PORT
      LAYER M5 ;
        RECT  32.256 0 32.28 0.084 ;
    END
  END rec[536]
  PIN rec[537]
    DIRECTION INPUT ;
    USE SIGNAL ;
    PORT
      LAYER M5 ;
        RECT  32.304 0 32.328 0.084 ;
    END
  END rec[537]
  PIN rec[538]
    DIRECTION INPUT ;
    USE SIGNAL ;
    PORT
      LAYER M5 ;
        RECT  32.352 0 32.376 0.084 ;
    END
  END rec[538]
  PIN rec[539]
    DIRECTION INPUT ;
    USE SIGNAL ;
    PORT
      LAYER M5 ;
        RECT  32.4 0 32.424 0.084 ;
    END
  END rec[539]
  PIN rec[53]
    DIRECTION INPUT ;
    USE SIGNAL ;
    PORT
      LAYER M5 ;
        RECT  1.776 0 1.8 0.084 ;
    END
  END rec[53]
  PIN rec[540]
    DIRECTION INPUT ;
    USE SIGNAL ;
    PORT
      LAYER M5 ;
        RECT  32.448 0 32.472 0.084 ;
    END
  END rec[540]
  PIN rec[541]
    DIRECTION INPUT ;
    USE SIGNAL ;
    PORT
      LAYER M5 ;
        RECT  32.496 0 32.52 0.084 ;
    END
  END rec[541]
  PIN rec[542]
    DIRECTION INPUT ;
    USE SIGNAL ;
    PORT
      LAYER M5 ;
        RECT  32.544 0 32.568 0.084 ;
    END
  END rec[542]
  PIN rec[543]
    DIRECTION INPUT ;
    USE SIGNAL ;
    PORT
      LAYER M5 ;
        RECT  77.52 0 77.544 0.084 ;
    END
  END rec[543]
  PIN rec[544]
    DIRECTION INPUT ;
    USE SIGNAL ;
    PORT
      LAYER M5 ;
        RECT  77.568 0 77.592 0.084 ;
    END
  END rec[544]
  PIN rec[545]
    DIRECTION INPUT ;
    USE SIGNAL ;
    PORT
      LAYER M5 ;
        RECT  77.616 0 77.64 0.084 ;
    END
  END rec[545]
  PIN rec[546]
    DIRECTION INPUT ;
    USE SIGNAL ;
    PORT
      LAYER M5 ;
        RECT  77.664 0 77.688 0.084 ;
    END
  END rec[546]
  PIN rec[547]
    DIRECTION INPUT ;
    USE SIGNAL ;
    PORT
      LAYER M5 ;
        RECT  77.712 0 77.736 0.084 ;
    END
  END rec[547]
  PIN rec[548]
    DIRECTION INPUT ;
    USE SIGNAL ;
    PORT
      LAYER M5 ;
        RECT  77.76 0 77.784 0.084 ;
    END
  END rec[548]
  PIN rec[549]
    DIRECTION INPUT ;
    USE SIGNAL ;
    PORT
      LAYER M5 ;
        RECT  77.808 0 77.832 0.084 ;
    END
  END rec[549]
  PIN rec[54]
    DIRECTION INPUT ;
    USE SIGNAL ;
    PORT
      LAYER M5 ;
        RECT  1.824 0 1.848 0.084 ;
    END
  END rec[54]
  PIN rec[550]
    DIRECTION INPUT ;
    USE SIGNAL ;
    PORT
      LAYER M5 ;
        RECT  77.856 0 77.88 0.084 ;
    END
  END rec[550]
  PIN rec[551]
    DIRECTION INPUT ;
    USE SIGNAL ;
    PORT
      LAYER M5 ;
        RECT  77.904 0 77.928 0.084 ;
    END
  END rec[551]
  PIN rec[552]
    DIRECTION INPUT ;
    USE SIGNAL ;
    PORT
      LAYER M5 ;
        RECT  77.952 0 77.976 0.084 ;
    END
  END rec[552]
  PIN rec[553]
    DIRECTION INPUT ;
    USE SIGNAL ;
    PORT
      LAYER M5 ;
        RECT  78 0 78.024 0.084 ;
    END
  END rec[553]
  PIN rec[554]
    DIRECTION INPUT ;
    USE SIGNAL ;
    PORT
      LAYER M5 ;
        RECT  78.048 0 78.072 0.084 ;
    END
  END rec[554]
  PIN rec[555]
    DIRECTION INPUT ;
    USE SIGNAL ;
    PORT
      LAYER M5 ;
        RECT  78.096 0 78.12 0.084 ;
    END
  END rec[555]
  PIN rec[556]
    DIRECTION INPUT ;
    USE SIGNAL ;
    PORT
      LAYER M5 ;
        RECT  78.144 0 78.168 0.084 ;
    END
  END rec[556]
  PIN rec[557]
    DIRECTION INPUT ;
    USE SIGNAL ;
    PORT
      LAYER M5 ;
        RECT  78.192 0 78.216 0.084 ;
    END
  END rec[557]
  PIN rec[558]
    DIRECTION INPUT ;
    USE SIGNAL ;
    PORT
      LAYER M5 ;
        RECT  78.24 0 78.264 0.084 ;
    END
  END rec[558]
  PIN rec[559]
    DIRECTION INPUT ;
    USE SIGNAL ;
    PORT
      LAYER M5 ;
        RECT  78.288 0 78.312 0.084 ;
    END
  END rec[559]
  PIN rec[55]
    DIRECTION INPUT ;
    USE SIGNAL ;
    PORT
      LAYER M5 ;
        RECT  1.872 0 1.896 0.084 ;
    END
  END rec[55]
  PIN rec[560]
    DIRECTION INPUT ;
    USE SIGNAL ;
    PORT
      LAYER M5 ;
        RECT  78.336 0 78.36 0.084 ;
    END
  END rec[560]
  PIN rec[561]
    DIRECTION INPUT ;
    USE SIGNAL ;
    PORT
      LAYER M5 ;
        RECT  78.384 0 78.408 0.084 ;
    END
  END rec[561]
  PIN rec[562]
    DIRECTION INPUT ;
    USE SIGNAL ;
    PORT
      LAYER M5 ;
        RECT  78.432 0 78.456 0.084 ;
    END
  END rec[562]
  PIN rec[563]
    DIRECTION INPUT ;
    USE SIGNAL ;
    PORT
      LAYER M5 ;
        RECT  78.48 0 78.504 0.084 ;
    END
  END rec[563]
  PIN rec[564]
    DIRECTION INPUT ;
    USE SIGNAL ;
    PORT
      LAYER M5 ;
        RECT  78.528 0 78.552 0.084 ;
    END
  END rec[564]
  PIN rec[565]
    DIRECTION INPUT ;
    USE SIGNAL ;
    PORT
      LAYER M5 ;
        RECT  78.576 0 78.6 0.084 ;
    END
  END rec[565]
  PIN rec[566]
    DIRECTION INPUT ;
    USE SIGNAL ;
    PORT
      LAYER M5 ;
        RECT  78.624 0 78.648 0.084 ;
    END
  END rec[566]
  PIN rec[567]
    DIRECTION INPUT ;
    USE SIGNAL ;
    PORT
      LAYER M5 ;
        RECT  78.672 0 78.696 0.084 ;
    END
  END rec[567]
  PIN rec[568]
    DIRECTION INPUT ;
    USE SIGNAL ;
    PORT
      LAYER M5 ;
        RECT  78.72 0 78.744 0.084 ;
    END
  END rec[568]
  PIN rec[569]
    DIRECTION INPUT ;
    USE SIGNAL ;
    PORT
      LAYER M5 ;
        RECT  78.768 0 78.792 0.084 ;
    END
  END rec[569]
  PIN rec[56]
    DIRECTION INPUT ;
    USE SIGNAL ;
    PORT
      LAYER M5 ;
        RECT  1.92 0 1.944 0.084 ;
    END
  END rec[56]
  PIN rec[570]
    DIRECTION INPUT ;
    USE SIGNAL ;
    PORT
      LAYER M5 ;
        RECT  78.816 0 78.84 0.084 ;
    END
  END rec[570]
  PIN rec[571]
    DIRECTION INPUT ;
    USE SIGNAL ;
    PORT
      LAYER M5 ;
        RECT  78.864 0 78.888 0.084 ;
    END
  END rec[571]
  PIN rec[572]
    DIRECTION INPUT ;
    USE SIGNAL ;
    PORT
      LAYER M5 ;
        RECT  78.912 0 78.936 0.084 ;
    END
  END rec[572]
  PIN rec[573]
    DIRECTION INPUT ;
    USE SIGNAL ;
    PORT
      LAYER M5 ;
        RECT  78.96 0 78.984 0.084 ;
    END
  END rec[573]
  PIN rec[574]
    DIRECTION INPUT ;
    USE SIGNAL ;
    PORT
      LAYER M5 ;
        RECT  79.008 0 79.032 0.084 ;
    END
  END rec[574]
  PIN rec[575]
    DIRECTION INPUT ;
    USE SIGNAL ;
    PORT
      LAYER M5 ;
        RECT  87.12 0 87.144 0.084 ;
    END
  END rec[575]
  PIN rec[576]
    DIRECTION INPUT ;
    USE SIGNAL ;
    PORT
      LAYER M5 ;
        RECT  87.168 0 87.192 0.084 ;
    END
  END rec[576]
  PIN rec[577]
    DIRECTION INPUT ;
    USE SIGNAL ;
    PORT
      LAYER M5 ;
        RECT  87.216 0 87.24 0.084 ;
    END
  END rec[577]
  PIN rec[578]
    DIRECTION INPUT ;
    USE SIGNAL ;
    PORT
      LAYER M5 ;
        RECT  87.264 0 87.288 0.084 ;
    END
  END rec[578]
  PIN rec[579]
    DIRECTION INPUT ;
    USE SIGNAL ;
    PORT
      LAYER M5 ;
        RECT  87.312 0 87.336 0.084 ;
    END
  END rec[579]
  PIN rec[57]
    DIRECTION INPUT ;
    USE SIGNAL ;
    PORT
      LAYER M5 ;
        RECT  1.968 0 1.992 0.084 ;
    END
  END rec[57]
  PIN rec[580]
    DIRECTION INPUT ;
    USE SIGNAL ;
    PORT
      LAYER M5 ;
        RECT  87.36 0 87.384 0.084 ;
    END
  END rec[580]
  PIN rec[581]
    DIRECTION INPUT ;
    USE SIGNAL ;
    PORT
      LAYER M5 ;
        RECT  87.408 0 87.432 0.084 ;
    END
  END rec[581]
  PIN rec[582]
    DIRECTION INPUT ;
    USE SIGNAL ;
    PORT
      LAYER M5 ;
        RECT  87.456 0 87.48 0.084 ;
    END
  END rec[582]
  PIN rec[583]
    DIRECTION INPUT ;
    USE SIGNAL ;
    PORT
      LAYER M5 ;
        RECT  87.504 0 87.528 0.084 ;
    END
  END rec[583]
  PIN rec[584]
    DIRECTION INPUT ;
    USE SIGNAL ;
    PORT
      LAYER M5 ;
        RECT  87.552 0 87.576 0.084 ;
    END
  END rec[584]
  PIN rec[585]
    DIRECTION INPUT ;
    USE SIGNAL ;
    PORT
      LAYER M5 ;
        RECT  87.6 0 87.624 0.084 ;
    END
  END rec[585]
  PIN rec[586]
    DIRECTION INPUT ;
    USE SIGNAL ;
    PORT
      LAYER M5 ;
        RECT  87.648 0 87.672 0.084 ;
    END
  END rec[586]
  PIN rec[587]
    DIRECTION INPUT ;
    USE SIGNAL ;
    PORT
      LAYER M5 ;
        RECT  87.696 0 87.72 0.084 ;
    END
  END rec[587]
  PIN rec[588]
    DIRECTION INPUT ;
    USE SIGNAL ;
    PORT
      LAYER M5 ;
        RECT  87.744 0 87.768 0.084 ;
    END
  END rec[588]
  PIN rec[589]
    DIRECTION INPUT ;
    USE SIGNAL ;
    PORT
      LAYER M5 ;
        RECT  87.792 0 87.816 0.084 ;
    END
  END rec[589]
  PIN rec[58]
    DIRECTION INPUT ;
    USE SIGNAL ;
    PORT
      LAYER M5 ;
        RECT  2.016 0 2.04 0.084 ;
    END
  END rec[58]
  PIN rec[590]
    DIRECTION INPUT ;
    USE SIGNAL ;
    PORT
      LAYER M5 ;
        RECT  87.84 0 87.864 0.084 ;
    END
  END rec[590]
  PIN rec[591]
    DIRECTION INPUT ;
    USE SIGNAL ;
    PORT
      LAYER M5 ;
        RECT  87.888 0 87.912 0.084 ;
    END
  END rec[591]
  PIN rec[592]
    DIRECTION INPUT ;
    USE SIGNAL ;
    PORT
      LAYER M5 ;
        RECT  87.936 0 87.96 0.084 ;
    END
  END rec[592]
  PIN rec[593]
    DIRECTION INPUT ;
    USE SIGNAL ;
    PORT
      LAYER M5 ;
        RECT  87.984 0 88.008 0.084 ;
    END
  END rec[593]
  PIN rec[594]
    DIRECTION INPUT ;
    USE SIGNAL ;
    PORT
      LAYER M5 ;
        RECT  88.032 0 88.056 0.084 ;
    END
  END rec[594]
  PIN rec[595]
    DIRECTION INPUT ;
    USE SIGNAL ;
    PORT
      LAYER M5 ;
        RECT  88.08 0 88.104 0.084 ;
    END
  END rec[595]
  PIN rec[596]
    DIRECTION INPUT ;
    USE SIGNAL ;
    PORT
      LAYER M5 ;
        RECT  88.128 0 88.152 0.084 ;
    END
  END rec[596]
  PIN rec[597]
    DIRECTION INPUT ;
    USE SIGNAL ;
    PORT
      LAYER M5 ;
        RECT  88.176 0 88.2 0.084 ;
    END
  END rec[597]
  PIN rec[598]
    DIRECTION INPUT ;
    USE SIGNAL ;
    PORT
      LAYER M5 ;
        RECT  88.224 0 88.248 0.084 ;
    END
  END rec[598]
  PIN rec[599]
    DIRECTION INPUT ;
    USE SIGNAL ;
    PORT
      LAYER M5 ;
        RECT  88.272 0 88.296 0.084 ;
    END
  END rec[599]
  PIN rec[59]
    DIRECTION INPUT ;
    USE SIGNAL ;
    PORT
      LAYER M5 ;
        RECT  2.064 0 2.088 0.084 ;
    END
  END rec[59]
  PIN rec[5]
    DIRECTION INPUT ;
    USE SIGNAL ;
    PORT
      LAYER M5 ;
        RECT  32.88 0 32.904 0.084 ;
    END
  END rec[5]
  PIN rec[600]
    DIRECTION INPUT ;
    USE SIGNAL ;
    PORT
      LAYER M5 ;
        RECT  88.32 0 88.344 0.084 ;
    END
  END rec[600]
  PIN rec[601]
    DIRECTION INPUT ;
    USE SIGNAL ;
    PORT
      LAYER M5 ;
        RECT  88.368 0 88.392 0.084 ;
    END
  END rec[601]
  PIN rec[602]
    DIRECTION INPUT ;
    USE SIGNAL ;
    PORT
      LAYER M5 ;
        RECT  88.416 0 88.44 0.084 ;
    END
  END rec[602]
  PIN rec[603]
    DIRECTION INPUT ;
    USE SIGNAL ;
    PORT
      LAYER M5 ;
        RECT  88.464 0 88.488 0.084 ;
    END
  END rec[603]
  PIN rec[604]
    DIRECTION INPUT ;
    USE SIGNAL ;
    PORT
      LAYER M5 ;
        RECT  88.512 0 88.536 0.084 ;
    END
  END rec[604]
  PIN rec[605]
    DIRECTION INPUT ;
    USE SIGNAL ;
    PORT
      LAYER M5 ;
        RECT  88.56 0 88.584 0.084 ;
    END
  END rec[605]
  PIN rec[606]
    DIRECTION INPUT ;
    USE SIGNAL ;
    PORT
      LAYER M5 ;
        RECT  88.608 0 88.632 0.084 ;
    END
  END rec[606]
  PIN rec[607]
    DIRECTION INPUT ;
    USE SIGNAL ;
    PORT
      LAYER M5 ;
        RECT  96.72 0 96.744 0.084 ;
    END
  END rec[607]
  PIN rec[608]
    DIRECTION INPUT ;
    USE SIGNAL ;
    PORT
      LAYER M5 ;
        RECT  96.768 0 96.792 0.084 ;
    END
  END rec[608]
  PIN rec[609]
    DIRECTION INPUT ;
    USE SIGNAL ;
    PORT
      LAYER M5 ;
        RECT  96.816 0 96.84 0.084 ;
    END
  END rec[609]
  PIN rec[60]
    DIRECTION INPUT ;
    USE SIGNAL ;
    PORT
      LAYER M5 ;
        RECT  2.112 0 2.136 0.084 ;
    END
  END rec[60]
  PIN rec[610]
    DIRECTION INPUT ;
    USE SIGNAL ;
    PORT
      LAYER M5 ;
        RECT  96.864 0 96.888 0.084 ;
    END
  END rec[610]
  PIN rec[611]
    DIRECTION INPUT ;
    USE SIGNAL ;
    PORT
      LAYER M5 ;
        RECT  96.912 0 96.936 0.084 ;
    END
  END rec[611]
  PIN rec[612]
    DIRECTION INPUT ;
    USE SIGNAL ;
    PORT
      LAYER M5 ;
        RECT  96.96 0 96.984 0.084 ;
    END
  END rec[612]
  PIN rec[613]
    DIRECTION INPUT ;
    USE SIGNAL ;
    PORT
      LAYER M5 ;
        RECT  97.008 0 97.032 0.084 ;
    END
  END rec[613]
  PIN rec[614]
    DIRECTION INPUT ;
    USE SIGNAL ;
    PORT
      LAYER M5 ;
        RECT  97.056 0 97.08 0.084 ;
    END
  END rec[614]
  PIN rec[615]
    DIRECTION INPUT ;
    USE SIGNAL ;
    PORT
      LAYER M5 ;
        RECT  97.104 0 97.128 0.084 ;
    END
  END rec[615]
  PIN rec[616]
    DIRECTION INPUT ;
    USE SIGNAL ;
    PORT
      LAYER M5 ;
        RECT  97.152 0 97.176 0.084 ;
    END
  END rec[616]
  PIN rec[617]
    DIRECTION INPUT ;
    USE SIGNAL ;
    PORT
      LAYER M5 ;
        RECT  97.2 0 97.224 0.084 ;
    END
  END rec[617]
  PIN rec[618]
    DIRECTION INPUT ;
    USE SIGNAL ;
    PORT
      LAYER M5 ;
        RECT  97.248 0 97.272 0.084 ;
    END
  END rec[618]
  PIN rec[619]
    DIRECTION INPUT ;
    USE SIGNAL ;
    PORT
      LAYER M5 ;
        RECT  97.296 0 97.32 0.084 ;
    END
  END rec[619]
  PIN rec[61]
    DIRECTION INPUT ;
    USE SIGNAL ;
    PORT
      LAYER M5 ;
        RECT  2.16 0 2.184 0.084 ;
    END
  END rec[61]
  PIN rec[620]
    DIRECTION INPUT ;
    USE SIGNAL ;
    PORT
      LAYER M5 ;
        RECT  97.344 0 97.368 0.084 ;
    END
  END rec[620]
  PIN rec[621]
    DIRECTION INPUT ;
    USE SIGNAL ;
    PORT
      LAYER M5 ;
        RECT  97.392 0 97.416 0.084 ;
    END
  END rec[621]
  PIN rec[622]
    DIRECTION INPUT ;
    USE SIGNAL ;
    PORT
      LAYER M5 ;
        RECT  97.44 0 97.464 0.084 ;
    END
  END rec[622]
  PIN rec[623]
    DIRECTION INPUT ;
    USE SIGNAL ;
    PORT
      LAYER M5 ;
        RECT  97.488 0 97.512 0.084 ;
    END
  END rec[623]
  PIN rec[624]
    DIRECTION INPUT ;
    USE SIGNAL ;
    PORT
      LAYER M5 ;
        RECT  97.536 0 97.56 0.084 ;
    END
  END rec[624]
  PIN rec[625]
    DIRECTION INPUT ;
    USE SIGNAL ;
    PORT
      LAYER M5 ;
        RECT  97.584 0 97.608 0.084 ;
    END
  END rec[625]
  PIN rec[626]
    DIRECTION INPUT ;
    USE SIGNAL ;
    PORT
      LAYER M5 ;
        RECT  97.632 0 97.656 0.084 ;
    END
  END rec[626]
  PIN rec[627]
    DIRECTION INPUT ;
    USE SIGNAL ;
    PORT
      LAYER M5 ;
        RECT  97.68 0 97.704 0.084 ;
    END
  END rec[627]
  PIN rec[628]
    DIRECTION INPUT ;
    USE SIGNAL ;
    PORT
      LAYER M5 ;
        RECT  97.728 0 97.752 0.084 ;
    END
  END rec[628]
  PIN rec[629]
    DIRECTION INPUT ;
    USE SIGNAL ;
    PORT
      LAYER M5 ;
        RECT  97.776 0 97.8 0.084 ;
    END
  END rec[629]
  PIN rec[62]
    DIRECTION INPUT ;
    USE SIGNAL ;
    PORT
      LAYER M5 ;
        RECT  2.208 0 2.232 0.084 ;
    END
  END rec[62]
  PIN rec[630]
    DIRECTION INPUT ;
    USE SIGNAL ;
    PORT
      LAYER M5 ;
        RECT  97.824 0 97.848 0.084 ;
    END
  END rec[630]
  PIN rec[631]
    DIRECTION INPUT ;
    USE SIGNAL ;
    PORT
      LAYER M5 ;
        RECT  97.872 0 97.896 0.084 ;
    END
  END rec[631]
  PIN rec[632]
    DIRECTION INPUT ;
    USE SIGNAL ;
    PORT
      LAYER M5 ;
        RECT  97.92 0 97.944 0.084 ;
    END
  END rec[632]
  PIN rec[633]
    DIRECTION INPUT ;
    USE SIGNAL ;
    PORT
      LAYER M5 ;
        RECT  97.968 0 97.992 0.084 ;
    END
  END rec[633]
  PIN rec[634]
    DIRECTION INPUT ;
    USE SIGNAL ;
    PORT
      LAYER M5 ;
        RECT  98.016 0 98.04 0.084 ;
    END
  END rec[634]
  PIN rec[635]
    DIRECTION INPUT ;
    USE SIGNAL ;
    PORT
      LAYER M5 ;
        RECT  98.064 0 98.088 0.084 ;
    END
  END rec[635]
  PIN rec[636]
    DIRECTION INPUT ;
    USE SIGNAL ;
    PORT
      LAYER M5 ;
        RECT  98.112 0 98.136 0.084 ;
    END
  END rec[636]
  PIN rec[637]
    DIRECTION INPUT ;
    USE SIGNAL ;
    PORT
      LAYER M5 ;
        RECT  98.16 0 98.184 0.084 ;
    END
  END rec[637]
  PIN rec[638]
    DIRECTION INPUT ;
    USE SIGNAL ;
    PORT
      LAYER M5 ;
        RECT  98.208 0 98.232 0.084 ;
    END
  END rec[638]
  PIN rec[639]
    DIRECTION INPUT ;
    USE SIGNAL ;
    PORT
      LAYER M5 ;
        RECT  45.264 0 45.288 0.084 ;
    END
  END rec[639]
  PIN rec[63]
    DIRECTION INPUT ;
    USE SIGNAL ;
    PORT
      LAYER M5 ;
        RECT  61.392 0 61.416 0.084 ;
    END
  END rec[63]
  PIN rec[640]
    DIRECTION INPUT ;
    USE SIGNAL ;
    PORT
      LAYER M5 ;
        RECT  45.312 0 45.336 0.084 ;
    END
  END rec[640]
  PIN rec[641]
    DIRECTION INPUT ;
    USE SIGNAL ;
    PORT
      LAYER M5 ;
        RECT  45.36 0 45.384 0.084 ;
    END
  END rec[641]
  PIN rec[642]
    DIRECTION INPUT ;
    USE SIGNAL ;
    PORT
      LAYER M5 ;
        RECT  45.408 0 45.432 0.084 ;
    END
  END rec[642]
  PIN rec[643]
    DIRECTION INPUT ;
    USE SIGNAL ;
    PORT
      LAYER M5 ;
        RECT  45.456 0 45.48 0.084 ;
    END
  END rec[643]
  PIN rec[644]
    DIRECTION INPUT ;
    USE SIGNAL ;
    PORT
      LAYER M5 ;
        RECT  45.504 0 45.528 0.084 ;
    END
  END rec[644]
  PIN rec[645]
    DIRECTION INPUT ;
    USE SIGNAL ;
    PORT
      LAYER M5 ;
        RECT  45.552 0 45.576 0.084 ;
    END
  END rec[645]
  PIN rec[646]
    DIRECTION INPUT ;
    USE SIGNAL ;
    PORT
      LAYER M5 ;
        RECT  45.6 0 45.624 0.084 ;
    END
  END rec[646]
  PIN rec[647]
    DIRECTION INPUT ;
    USE SIGNAL ;
    PORT
      LAYER M5 ;
        RECT  45.648 0 45.672 0.084 ;
    END
  END rec[647]
  PIN rec[648]
    DIRECTION INPUT ;
    USE SIGNAL ;
    PORT
      LAYER M5 ;
        RECT  45.696 0 45.72 0.084 ;
    END
  END rec[648]
  PIN rec[649]
    DIRECTION INPUT ;
    USE SIGNAL ;
    PORT
      LAYER M5 ;
        RECT  45.744 0 45.768 0.084 ;
    END
  END rec[649]
  PIN rec[64]
    DIRECTION INPUT ;
    USE SIGNAL ;
    PORT
      LAYER M5 ;
        RECT  61.44 0 61.464 0.084 ;
    END
  END rec[64]
  PIN rec[650]
    DIRECTION INPUT ;
    USE SIGNAL ;
    PORT
      LAYER M5 ;
        RECT  45.792 0 45.816 0.084 ;
    END
  END rec[650]
  PIN rec[651]
    DIRECTION INPUT ;
    USE SIGNAL ;
    PORT
      LAYER M5 ;
        RECT  45.84 0 45.864 0.084 ;
    END
  END rec[651]
  PIN rec[652]
    DIRECTION INPUT ;
    USE SIGNAL ;
    PORT
      LAYER M5 ;
        RECT  45.888 0 45.912 0.084 ;
    END
  END rec[652]
  PIN rec[653]
    DIRECTION INPUT ;
    USE SIGNAL ;
    PORT
      LAYER M5 ;
        RECT  45.936 0 45.96 0.084 ;
    END
  END rec[653]
  PIN rec[654]
    DIRECTION INPUT ;
    USE SIGNAL ;
    PORT
      LAYER M5 ;
        RECT  45.984 0 46.008 0.084 ;
    END
  END rec[654]
  PIN rec[655]
    DIRECTION INPUT ;
    USE SIGNAL ;
    PORT
      LAYER M5 ;
        RECT  46.032 0 46.056 0.084 ;
    END
  END rec[655]
  PIN rec[656]
    DIRECTION INPUT ;
    USE SIGNAL ;
    PORT
      LAYER M5 ;
        RECT  46.08 0 46.104 0.084 ;
    END
  END rec[656]
  PIN rec[657]
    DIRECTION INPUT ;
    USE SIGNAL ;
    PORT
      LAYER M5 ;
        RECT  46.128 0 46.152 0.084 ;
    END
  END rec[657]
  PIN rec[658]
    DIRECTION INPUT ;
    USE SIGNAL ;
    PORT
      LAYER M5 ;
        RECT  46.176 0 46.2 0.084 ;
    END
  END rec[658]
  PIN rec[659]
    DIRECTION INPUT ;
    USE SIGNAL ;
    PORT
      LAYER M5 ;
        RECT  46.224 0 46.248 0.084 ;
    END
  END rec[659]
  PIN rec[65]
    DIRECTION INPUT ;
    USE SIGNAL ;
    PORT
      LAYER M5 ;
        RECT  61.488 0 61.512 0.084 ;
    END
  END rec[65]
  PIN rec[660]
    DIRECTION INPUT ;
    USE SIGNAL ;
    PORT
      LAYER M5 ;
        RECT  46.272 0 46.296 0.084 ;
    END
  END rec[660]
  PIN rec[661]
    DIRECTION INPUT ;
    USE SIGNAL ;
    PORT
      LAYER M5 ;
        RECT  46.32 0 46.344 0.084 ;
    END
  END rec[661]
  PIN rec[662]
    DIRECTION INPUT ;
    USE SIGNAL ;
    PORT
      LAYER M5 ;
        RECT  46.368 0 46.392 0.084 ;
    END
  END rec[662]
  PIN rec[663]
    DIRECTION INPUT ;
    USE SIGNAL ;
    PORT
      LAYER M5 ;
        RECT  46.416 0 46.44 0.084 ;
    END
  END rec[663]
  PIN rec[664]
    DIRECTION INPUT ;
    USE SIGNAL ;
    PORT
      LAYER M5 ;
        RECT  46.464 0 46.488 0.084 ;
    END
  END rec[664]
  PIN rec[665]
    DIRECTION INPUT ;
    USE SIGNAL ;
    PORT
      LAYER M5 ;
        RECT  46.512 0 46.536 0.084 ;
    END
  END rec[665]
  PIN rec[666]
    DIRECTION INPUT ;
    USE SIGNAL ;
    PORT
      LAYER M5 ;
        RECT  46.56 0 46.584 0.084 ;
    END
  END rec[666]
  PIN rec[667]
    DIRECTION INPUT ;
    USE SIGNAL ;
    PORT
      LAYER M5 ;
        RECT  46.608 0 46.632 0.084 ;
    END
  END rec[667]
  PIN rec[668]
    DIRECTION INPUT ;
    USE SIGNAL ;
    PORT
      LAYER M5 ;
        RECT  46.656 0 46.68 0.084 ;
    END
  END rec[668]
  PIN rec[669]
    DIRECTION INPUT ;
    USE SIGNAL ;
    PORT
      LAYER M5 ;
        RECT  46.704 0 46.728 0.084 ;
    END
  END rec[669]
  PIN rec[66]
    DIRECTION INPUT ;
    USE SIGNAL ;
    PORT
      LAYER M5 ;
        RECT  61.536 0 61.56 0.084 ;
    END
  END rec[66]
  PIN rec[670]
    DIRECTION INPUT ;
    USE SIGNAL ;
    PORT
      LAYER M5 ;
        RECT  46.752 0 46.776 0.084 ;
    END
  END rec[670]
  PIN rec[671]
    DIRECTION INPUT ;
    USE SIGNAL ;
    PORT
      LAYER M5 ;
        RECT  43.728 0 43.752 0.084 ;
    END
  END rec[671]
  PIN rec[672]
    DIRECTION INPUT ;
    USE SIGNAL ;
    PORT
      LAYER M5 ;
        RECT  43.776 0 43.8 0.084 ;
    END
  END rec[672]
  PIN rec[673]
    DIRECTION INPUT ;
    USE SIGNAL ;
    PORT
      LAYER M5 ;
        RECT  43.824 0 43.848 0.084 ;
    END
  END rec[673]
  PIN rec[674]
    DIRECTION INPUT ;
    USE SIGNAL ;
    PORT
      LAYER M5 ;
        RECT  43.872 0 43.896 0.084 ;
    END
  END rec[674]
  PIN rec[675]
    DIRECTION INPUT ;
    USE SIGNAL ;
    PORT
      LAYER M5 ;
        RECT  43.92 0 43.944 0.084 ;
    END
  END rec[675]
  PIN rec[676]
    DIRECTION INPUT ;
    USE SIGNAL ;
    PORT
      LAYER M5 ;
        RECT  43.968 0 43.992 0.084 ;
    END
  END rec[676]
  PIN rec[677]
    DIRECTION INPUT ;
    USE SIGNAL ;
    PORT
      LAYER M5 ;
        RECT  44.016 0 44.04 0.084 ;
    END
  END rec[677]
  PIN rec[678]
    DIRECTION INPUT ;
    USE SIGNAL ;
    PORT
      LAYER M5 ;
        RECT  44.064 0 44.088 0.084 ;
    END
  END rec[678]
  PIN rec[679]
    DIRECTION INPUT ;
    USE SIGNAL ;
    PORT
      LAYER M5 ;
        RECT  44.112 0 44.136 0.084 ;
    END
  END rec[679]
  PIN rec[67]
    DIRECTION INPUT ;
    USE SIGNAL ;
    PORT
      LAYER M5 ;
        RECT  61.584 0 61.608 0.084 ;
    END
  END rec[67]
  PIN rec[680]
    DIRECTION INPUT ;
    USE SIGNAL ;
    PORT
      LAYER M5 ;
        RECT  44.16 0 44.184 0.084 ;
    END
  END rec[680]
  PIN rec[681]
    DIRECTION INPUT ;
    USE SIGNAL ;
    PORT
      LAYER M5 ;
        RECT  44.208 0 44.232 0.084 ;
    END
  END rec[681]
  PIN rec[682]
    DIRECTION INPUT ;
    USE SIGNAL ;
    PORT
      LAYER M5 ;
        RECT  44.256 0 44.28 0.084 ;
    END
  END rec[682]
  PIN rec[68]
    DIRECTION INPUT ;
    USE SIGNAL ;
    PORT
      LAYER M5 ;
        RECT  61.632 0 61.656 0.084 ;
    END
  END rec[68]
  PIN rec[69]
    DIRECTION INPUT ;
    USE SIGNAL ;
    PORT
      LAYER M5 ;
        RECT  61.68 0 61.704 0.084 ;
    END
  END rec[69]
  PIN rec[6]
    DIRECTION INPUT ;
    USE SIGNAL ;
    PORT
      LAYER M5 ;
        RECT  32.928 0 32.952 0.084 ;
    END
  END rec[6]
  PIN rec[70]
    DIRECTION INPUT ;
    USE SIGNAL ;
    PORT
      LAYER M5 ;
        RECT  61.728 0 61.752 0.084 ;
    END
  END rec[70]
  PIN rec[71]
    DIRECTION INPUT ;
    USE SIGNAL ;
    PORT
      LAYER M5 ;
        RECT  61.776 0 61.8 0.084 ;
    END
  END rec[71]
  PIN rec[72]
    DIRECTION INPUT ;
    USE SIGNAL ;
    PORT
      LAYER M5 ;
        RECT  61.824 0 61.848 0.084 ;
    END
  END rec[72]
  PIN rec[73]
    DIRECTION INPUT ;
    USE SIGNAL ;
    PORT
      LAYER M5 ;
        RECT  61.872 0 61.896 0.084 ;
    END
  END rec[73]
  PIN rec[74]
    DIRECTION INPUT ;
    USE SIGNAL ;
    PORT
      LAYER M5 ;
        RECT  61.92 0 61.944 0.084 ;
    END
  END rec[74]
  PIN rec[75]
    DIRECTION INPUT ;
    USE SIGNAL ;
    PORT
      LAYER M5 ;
        RECT  61.968 0 61.992 0.084 ;
    END
  END rec[75]
  PIN rec[76]
    DIRECTION INPUT ;
    USE SIGNAL ;
    PORT
      LAYER M5 ;
        RECT  62.016 0 62.04 0.084 ;
    END
  END rec[76]
  PIN rec[77]
    DIRECTION INPUT ;
    USE SIGNAL ;
    PORT
      LAYER M5 ;
        RECT  62.064 0 62.088 0.084 ;
    END
  END rec[77]
  PIN rec[78]
    DIRECTION INPUT ;
    USE SIGNAL ;
    PORT
      LAYER M5 ;
        RECT  62.112 0 62.136 0.084 ;
    END
  END rec[78]
  PIN rec[79]
    DIRECTION INPUT ;
    USE SIGNAL ;
    PORT
      LAYER M5 ;
        RECT  62.16 0 62.184 0.084 ;
    END
  END rec[79]
  PIN rec[7]
    DIRECTION INPUT ;
    USE SIGNAL ;
    PORT
      LAYER M5 ;
        RECT  32.976 0 33 0.084 ;
    END
  END rec[7]
  PIN rec[80]
    DIRECTION INPUT ;
    USE SIGNAL ;
    PORT
      LAYER M5 ;
        RECT  62.208 0 62.232 0.084 ;
    END
  END rec[80]
  PIN rec[81]
    DIRECTION INPUT ;
    USE SIGNAL ;
    PORT
      LAYER M5 ;
        RECT  62.256 0 62.28 0.084 ;
    END
  END rec[81]
  PIN rec[82]
    DIRECTION INPUT ;
    USE SIGNAL ;
    PORT
      LAYER M5 ;
        RECT  62.304 0 62.328 0.084 ;
    END
  END rec[82]
  PIN rec[83]
    DIRECTION INPUT ;
    USE SIGNAL ;
    PORT
      LAYER M5 ;
        RECT  62.352 0 62.376 0.084 ;
    END
  END rec[83]
  PIN rec[84]
    DIRECTION INPUT ;
    USE SIGNAL ;
    PORT
      LAYER M5 ;
        RECT  62.4 0 62.424 0.084 ;
    END
  END rec[84]
  PIN rec[85]
    DIRECTION INPUT ;
    USE SIGNAL ;
    PORT
      LAYER M5 ;
        RECT  62.448 0 62.472 0.084 ;
    END
  END rec[85]
  PIN rec[86]
    DIRECTION INPUT ;
    USE SIGNAL ;
    PORT
      LAYER M5 ;
        RECT  62.496 0 62.52 0.084 ;
    END
  END rec[86]
  PIN rec[87]
    DIRECTION INPUT ;
    USE SIGNAL ;
    PORT
      LAYER M5 ;
        RECT  62.544 0 62.568 0.084 ;
    END
  END rec[87]
  PIN rec[88]
    DIRECTION INPUT ;
    USE SIGNAL ;
    PORT
      LAYER M5 ;
        RECT  62.592 0 62.616 0.084 ;
    END
  END rec[88]
  PIN rec[89]
    DIRECTION INPUT ;
    USE SIGNAL ;
    PORT
      LAYER M5 ;
        RECT  62.64 0 62.664 0.084 ;
    END
  END rec[89]
  PIN rec[8]
    DIRECTION INPUT ;
    USE SIGNAL ;
    PORT
      LAYER M5 ;
        RECT  33.024 0 33.048 0.084 ;
    END
  END rec[8]
  PIN rec[90]
    DIRECTION INPUT ;
    USE SIGNAL ;
    PORT
      LAYER M5 ;
        RECT  62.688 0 62.712 0.084 ;
    END
  END rec[90]
  PIN rec[91]
    DIRECTION INPUT ;
    USE SIGNAL ;
    PORT
      LAYER M5 ;
        RECT  62.736 0 62.76 0.084 ;
    END
  END rec[91]
  PIN rec[92]
    DIRECTION INPUT ;
    USE SIGNAL ;
    PORT
      LAYER M5 ;
        RECT  62.784 0 62.808 0.084 ;
    END
  END rec[92]
  PIN rec[93]
    DIRECTION INPUT ;
    USE SIGNAL ;
    PORT
      LAYER M5 ;
        RECT  62.832 0 62.856 0.084 ;
    END
  END rec[93]
  PIN rec[94]
    DIRECTION INPUT ;
    USE SIGNAL ;
    PORT
      LAYER M5 ;
        RECT  62.88 0 62.904 0.084 ;
    END
  END rec[94]
  PIN rec[95]
    DIRECTION INPUT ;
    USE SIGNAL ;
    PORT
      LAYER M5 ;
        RECT  56.4 0 56.424 0.084 ;
    END
  END rec[95]
  PIN rec[96]
    DIRECTION INPUT ;
    USE SIGNAL ;
    PORT
      LAYER M5 ;
        RECT  56.448 0 56.472 0.084 ;
    END
  END rec[96]
  PIN rec[97]
    DIRECTION INPUT ;
    USE SIGNAL ;
    PORT
      LAYER M5 ;
        RECT  56.496 0 56.52 0.084 ;
    END
  END rec[97]
  PIN rec[98]
    DIRECTION INPUT ;
    USE SIGNAL ;
    PORT
      LAYER M5 ;
        RECT  56.544 0 56.568 0.084 ;
    END
  END rec[98]
  PIN rec[99]
    DIRECTION INPUT ;
    USE SIGNAL ;
    PORT
      LAYER M5 ;
        RECT  56.592 0 56.616 0.084 ;
    END
  END rec[99]
  PIN rec[9]
    DIRECTION INPUT ;
    USE SIGNAL ;
    PORT
      LAYER M5 ;
        RECT  33.072 0 33.096 0.084 ;
    END
  END rec[9]
  PIN rst_n
    DIRECTION INPUT ;
    USE SIGNAL ;
    PORT
      LAYER M5 ;
        RECT  44.304 0 44.328 0.084 ;
    END
  END rst_n
  PIN s1_v
    DIRECTION OUTPUT ;
    USE SIGNAL ;
    PORT
      LAYER M5 ;
        RECT  62.208 71.196 62.232 71.28 ;
    END
  END s1_v
  PIN s2[0]
    DIRECTION OUTPUT ;
    USE SIGNAL ;
    PORT
      LAYER M5 ;
        RECT  62.256 71.196 62.28 71.28 ;
    END
  END s2[0]
  PIN s2[100]
    DIRECTION OUTPUT ;
    USE SIGNAL ;
    PORT
      LAYER M5 ;
        RECT  63.984 71.196 64.008 71.28 ;
    END
  END s2[100]
  PIN s2[101]
    DIRECTION OUTPUT ;
    USE SIGNAL ;
    PORT
      LAYER M5 ;
        RECT  64.032 71.196 64.056 71.28 ;
    END
  END s2[101]
  PIN s2[102]
    DIRECTION OUTPUT ;
    USE SIGNAL ;
    PORT
      LAYER M5 ;
        RECT  64.08 71.196 64.104 71.28 ;
    END
  END s2[102]
  PIN s2[103]
    DIRECTION OUTPUT ;
    USE SIGNAL ;
    PORT
      LAYER M5 ;
        RECT  64.128 71.196 64.152 71.28 ;
    END
  END s2[103]
  PIN s2[104]
    DIRECTION OUTPUT ;
    USE SIGNAL ;
    PORT
      LAYER M5 ;
        RECT  64.176 71.196 64.2 71.28 ;
    END
  END s2[104]
  PIN s2[105]
    DIRECTION OUTPUT ;
    USE SIGNAL ;
    PORT
      LAYER M5 ;
        RECT  64.224 71.196 64.248 71.28 ;
    END
  END s2[105]
  PIN s2[106]
    DIRECTION OUTPUT ;
    USE SIGNAL ;
    PORT
      LAYER M5 ;
        RECT  64.272 71.196 64.296 71.28 ;
    END
  END s2[106]
  PIN s2[107]
    DIRECTION OUTPUT ;
    USE SIGNAL ;
    PORT
      LAYER M5 ;
        RECT  64.32 71.196 64.344 71.28 ;
    END
  END s2[107]
  PIN s2[108]
    DIRECTION OUTPUT ;
    USE SIGNAL ;
    PORT
      LAYER M5 ;
        RECT  64.368 71.196 64.392 71.28 ;
    END
  END s2[108]
  PIN s2[109]
    DIRECTION OUTPUT ;
    USE SIGNAL ;
    PORT
      LAYER M5 ;
        RECT  64.416 71.196 64.44 71.28 ;
    END
  END s2[109]
  PIN s2[10]
    DIRECTION OUTPUT ;
    USE SIGNAL ;
    PORT
      LAYER M5 ;
        RECT  62.736 71.196 62.76 71.28 ;
    END
  END s2[10]
  PIN s2[110]
    DIRECTION OUTPUT ;
    USE SIGNAL ;
    PORT
      LAYER M5 ;
        RECT  64.464 71.196 64.488 71.28 ;
    END
  END s2[110]
  PIN s2[111]
    DIRECTION OUTPUT ;
    USE SIGNAL ;
    PORT
      LAYER M5 ;
        RECT  64.512 71.196 64.536 71.28 ;
    END
  END s2[111]
  PIN s2[112]
    DIRECTION OUTPUT ;
    USE SIGNAL ;
    PORT
      LAYER M5 ;
        RECT  64.56 71.196 64.584 71.28 ;
    END
  END s2[112]
  PIN s2[113]
    DIRECTION OUTPUT ;
    USE SIGNAL ;
    PORT
      LAYER M5 ;
        RECT  64.608 71.196 64.632 71.28 ;
    END
  END s2[113]
  PIN s2[114]
    DIRECTION OUTPUT ;
    USE SIGNAL ;
    PORT
      LAYER M5 ;
        RECT  64.656 71.196 64.68 71.28 ;
    END
  END s2[114]
  PIN s2[115]
    DIRECTION OUTPUT ;
    USE SIGNAL ;
    PORT
      LAYER M5 ;
        RECT  64.704 71.196 64.728 71.28 ;
    END
  END s2[115]
  PIN s2[116]
    DIRECTION OUTPUT ;
    USE SIGNAL ;
    PORT
      LAYER M5 ;
        RECT  64.752 71.196 64.776 71.28 ;
    END
  END s2[116]
  PIN s2[117]
    DIRECTION OUTPUT ;
    USE SIGNAL ;
    PORT
      LAYER M5 ;
        RECT  64.8 71.196 64.824 71.28 ;
    END
  END s2[117]
  PIN s2[118]
    DIRECTION OUTPUT ;
    USE SIGNAL ;
    PORT
      LAYER M5 ;
        RECT  64.848 71.196 64.872 71.28 ;
    END
  END s2[118]
  PIN s2[119]
    DIRECTION OUTPUT ;
    USE SIGNAL ;
    PORT
      LAYER M5 ;
        RECT  64.896 71.196 64.92 71.28 ;
    END
  END s2[119]
  PIN s2[11]
    DIRECTION OUTPUT ;
    USE SIGNAL ;
    PORT
      LAYER M5 ;
        RECT  62.784 71.196 62.808 71.28 ;
    END
  END s2[11]
  PIN s2[120]
    DIRECTION OUTPUT ;
    USE SIGNAL ;
    PORT
      LAYER M5 ;
        RECT  64.944 71.196 64.968 71.28 ;
    END
  END s2[120]
  PIN s2[121]
    DIRECTION OUTPUT ;
    USE SIGNAL ;
    PORT
      LAYER M5 ;
        RECT  64.992 71.196 65.016 71.28 ;
    END
  END s2[121]
  PIN s2[122]
    DIRECTION OUTPUT ;
    USE SIGNAL ;
    PORT
      LAYER M5 ;
        RECT  65.04 71.196 65.064 71.28 ;
    END
  END s2[122]
  PIN s2[123]
    DIRECTION OUTPUT ;
    USE SIGNAL ;
    PORT
      LAYER M5 ;
        RECT  65.088 71.196 65.112 71.28 ;
    END
  END s2[123]
  PIN s2[124]
    DIRECTION OUTPUT ;
    USE SIGNAL ;
    PORT
      LAYER M5 ;
        RECT  65.136 71.196 65.16 71.28 ;
    END
  END s2[124]
  PIN s2[125]
    DIRECTION OUTPUT ;
    USE SIGNAL ;
    PORT
      LAYER M5 ;
        RECT  65.184 71.196 65.208 71.28 ;
    END
  END s2[125]
  PIN s2[126]
    DIRECTION OUTPUT ;
    USE SIGNAL ;
    PORT
      LAYER M5 ;
        RECT  65.232 71.196 65.256 71.28 ;
    END
  END s2[126]
  PIN s2[127]
    DIRECTION OUTPUT ;
    USE SIGNAL ;
    PORT
      LAYER M5 ;
        RECT  65.28 71.196 65.304 71.28 ;
    END
  END s2[127]
  PIN s2[128]
    DIRECTION OUTPUT ;
    USE SIGNAL ;
    PORT
      LAYER M5 ;
        RECT  65.328 71.196 65.352 71.28 ;
    END
  END s2[128]
  PIN s2[129]
    DIRECTION OUTPUT ;
    USE SIGNAL ;
    PORT
      LAYER M5 ;
        RECT  65.376 71.196 65.4 71.28 ;
    END
  END s2[129]
  PIN s2[12]
    DIRECTION OUTPUT ;
    USE SIGNAL ;
    PORT
      LAYER M5 ;
        RECT  62.832 71.196 62.856 71.28 ;
    END
  END s2[12]
  PIN s2[130]
    DIRECTION OUTPUT ;
    USE SIGNAL ;
    PORT
      LAYER M5 ;
        RECT  65.424 71.196 65.448 71.28 ;
    END
  END s2[130]
  PIN s2[131]
    DIRECTION OUTPUT ;
    USE SIGNAL ;
    PORT
      LAYER M5 ;
        RECT  65.472 71.196 65.496 71.28 ;
    END
  END s2[131]
  PIN s2[132]
    DIRECTION OUTPUT ;
    USE SIGNAL ;
    PORT
      LAYER M5 ;
        RECT  65.52 71.196 65.544 71.28 ;
    END
  END s2[132]
  PIN s2[133]
    DIRECTION OUTPUT ;
    USE SIGNAL ;
    PORT
      LAYER M5 ;
        RECT  65.568 71.196 65.592 71.28 ;
    END
  END s2[133]
  PIN s2[134]
    DIRECTION OUTPUT ;
    USE SIGNAL ;
    PORT
      LAYER M5 ;
        RECT  65.616 71.196 65.64 71.28 ;
    END
  END s2[134]
  PIN s2[135]
    DIRECTION OUTPUT ;
    USE SIGNAL ;
    PORT
      LAYER M5 ;
        RECT  65.664 71.196 65.688 71.28 ;
    END
  END s2[135]
  PIN s2[136]
    DIRECTION OUTPUT ;
    USE SIGNAL ;
    PORT
      LAYER M5 ;
        RECT  65.712 71.196 65.736 71.28 ;
    END
  END s2[136]
  PIN s2[137]
    DIRECTION OUTPUT ;
    USE SIGNAL ;
    PORT
      LAYER M5 ;
        RECT  65.76 71.196 65.784 71.28 ;
    END
  END s2[137]
  PIN s2[138]
    DIRECTION OUTPUT ;
    USE SIGNAL ;
    PORT
      LAYER M5 ;
        RECT  65.808 71.196 65.832 71.28 ;
    END
  END s2[138]
  PIN s2[139]
    DIRECTION OUTPUT ;
    USE SIGNAL ;
    PORT
      LAYER M5 ;
        RECT  65.856 71.196 65.88 71.28 ;
    END
  END s2[139]
  PIN s2[13]
    DIRECTION OUTPUT ;
    USE SIGNAL ;
    PORT
      LAYER M5 ;
        RECT  62.88 71.196 62.904 71.28 ;
    END
  END s2[13]
  PIN s2[140]
    DIRECTION OUTPUT ;
    USE SIGNAL ;
    PORT
      LAYER M5 ;
        RECT  65.904 71.196 65.928 71.28 ;
    END
  END s2[140]
  PIN s2[141]
    DIRECTION OUTPUT ;
    USE SIGNAL ;
    PORT
      LAYER M5 ;
        RECT  65.952 71.196 65.976 71.28 ;
    END
  END s2[141]
  PIN s2[142]
    DIRECTION OUTPUT ;
    USE SIGNAL ;
    PORT
      LAYER M5 ;
        RECT  66 71.196 66.024 71.28 ;
    END
  END s2[142]
  PIN s2[143]
    DIRECTION OUTPUT ;
    USE SIGNAL ;
    PORT
      LAYER M5 ;
        RECT  66.048 71.196 66.072 71.28 ;
    END
  END s2[143]
  PIN s2[144]
    DIRECTION OUTPUT ;
    USE SIGNAL ;
    PORT
      LAYER M5 ;
        RECT  66.096 71.196 66.12 71.28 ;
    END
  END s2[144]
  PIN s2[145]
    DIRECTION OUTPUT ;
    USE SIGNAL ;
    PORT
      LAYER M5 ;
        RECT  66.144 71.196 66.168 71.28 ;
    END
  END s2[145]
  PIN s2[146]
    DIRECTION OUTPUT ;
    USE SIGNAL ;
    PORT
      LAYER M5 ;
        RECT  66.192 71.196 66.216 71.28 ;
    END
  END s2[146]
  PIN s2[147]
    DIRECTION OUTPUT ;
    USE SIGNAL ;
    PORT
      LAYER M5 ;
        RECT  66.24 71.196 66.264 71.28 ;
    END
  END s2[147]
  PIN s2[148]
    DIRECTION OUTPUT ;
    USE SIGNAL ;
    PORT
      LAYER M5 ;
        RECT  66.288 71.196 66.312 71.28 ;
    END
  END s2[148]
  PIN s2[149]
    DIRECTION OUTPUT ;
    USE SIGNAL ;
    PORT
      LAYER M5 ;
        RECT  66.336 71.196 66.36 71.28 ;
    END
  END s2[149]
  PIN s2[14]
    DIRECTION OUTPUT ;
    USE SIGNAL ;
    PORT
      LAYER M5 ;
        RECT  62.928 71.196 62.952 71.28 ;
    END
  END s2[14]
  PIN s2[150]
    DIRECTION OUTPUT ;
    USE SIGNAL ;
    PORT
      LAYER M5 ;
        RECT  66.384 71.196 66.408 71.28 ;
    END
  END s2[150]
  PIN s2[151]
    DIRECTION OUTPUT ;
    USE SIGNAL ;
    PORT
      LAYER M5 ;
        RECT  66.432 71.196 66.456 71.28 ;
    END
  END s2[151]
  PIN s2[152]
    DIRECTION OUTPUT ;
    USE SIGNAL ;
    PORT
      LAYER M5 ;
        RECT  66.48 71.196 66.504 71.28 ;
    END
  END s2[152]
  PIN s2[153]
    DIRECTION OUTPUT ;
    USE SIGNAL ;
    PORT
      LAYER M5 ;
        RECT  66.528 71.196 66.552 71.28 ;
    END
  END s2[153]
  PIN s2[154]
    DIRECTION OUTPUT ;
    USE SIGNAL ;
    PORT
      LAYER M5 ;
        RECT  66.576 71.196 66.6 71.28 ;
    END
  END s2[154]
  PIN s2[155]
    DIRECTION OUTPUT ;
    USE SIGNAL ;
    PORT
      LAYER M5 ;
        RECT  66.624 71.196 66.648 71.28 ;
    END
  END s2[155]
  PIN s2[156]
    DIRECTION OUTPUT ;
    USE SIGNAL ;
    PORT
      LAYER M5 ;
        RECT  73.2 71.196 73.224 71.28 ;
    END
  END s2[156]
  PIN s2[157]
    DIRECTION OUTPUT ;
    USE SIGNAL ;
    PORT
      LAYER M5 ;
        RECT  73.248 71.196 73.272 71.28 ;
    END
  END s2[157]
  PIN s2[158]
    DIRECTION OUTPUT ;
    USE SIGNAL ;
    PORT
      LAYER M5 ;
        RECT  73.296 71.196 73.32 71.28 ;
    END
  END s2[158]
  PIN s2[159]
    DIRECTION OUTPUT ;
    USE SIGNAL ;
    PORT
      LAYER M5 ;
        RECT  73.344 71.196 73.368 71.28 ;
    END
  END s2[159]
  PIN s2[15]
    DIRECTION OUTPUT ;
    USE SIGNAL ;
    PORT
      LAYER M5 ;
        RECT  62.976 71.196 63 71.28 ;
    END
  END s2[15]
  PIN s2[160]
    DIRECTION OUTPUT ;
    USE SIGNAL ;
    PORT
      LAYER M5 ;
        RECT  73.392 71.196 73.416 71.28 ;
    END
  END s2[160]
  PIN s2[161]
    DIRECTION OUTPUT ;
    USE SIGNAL ;
    PORT
      LAYER M5 ;
        RECT  73.44 71.196 73.464 71.28 ;
    END
  END s2[161]
  PIN s2[162]
    DIRECTION OUTPUT ;
    USE SIGNAL ;
    PORT
      LAYER M5 ;
        RECT  73.488 71.196 73.512 71.28 ;
    END
  END s2[162]
  PIN s2[163]
    DIRECTION OUTPUT ;
    USE SIGNAL ;
    PORT
      LAYER M5 ;
        RECT  73.536 71.196 73.56 71.28 ;
    END
  END s2[163]
  PIN s2[164]
    DIRECTION OUTPUT ;
    USE SIGNAL ;
    PORT
      LAYER M5 ;
        RECT  73.584 71.196 73.608 71.28 ;
    END
  END s2[164]
  PIN s2[165]
    DIRECTION OUTPUT ;
    USE SIGNAL ;
    PORT
      LAYER M5 ;
        RECT  73.632 71.196 73.656 71.28 ;
    END
  END s2[165]
  PIN s2[166]
    DIRECTION OUTPUT ;
    USE SIGNAL ;
    PORT
      LAYER M5 ;
        RECT  73.68 71.196 73.704 71.28 ;
    END
  END s2[166]
  PIN s2[167]
    DIRECTION OUTPUT ;
    USE SIGNAL ;
    PORT
      LAYER M5 ;
        RECT  73.728 71.196 73.752 71.28 ;
    END
  END s2[167]
  PIN s2[168]
    DIRECTION OUTPUT ;
    USE SIGNAL ;
    PORT
      LAYER M5 ;
        RECT  73.776 71.196 73.8 71.28 ;
    END
  END s2[168]
  PIN s2[169]
    DIRECTION OUTPUT ;
    USE SIGNAL ;
    PORT
      LAYER M5 ;
        RECT  73.824 71.196 73.848 71.28 ;
    END
  END s2[169]
  PIN s2[16]
    DIRECTION OUTPUT ;
    USE SIGNAL ;
    PORT
      LAYER M5 ;
        RECT  63.024 71.196 63.048 71.28 ;
    END
  END s2[16]
  PIN s2[170]
    DIRECTION OUTPUT ;
    USE SIGNAL ;
    PORT
      LAYER M5 ;
        RECT  73.872 71.196 73.896 71.28 ;
    END
  END s2[170]
  PIN s2[171]
    DIRECTION OUTPUT ;
    USE SIGNAL ;
    PORT
      LAYER M5 ;
        RECT  73.92 71.196 73.944 71.28 ;
    END
  END s2[171]
  PIN s2[172]
    DIRECTION OUTPUT ;
    USE SIGNAL ;
    PORT
      LAYER M5 ;
        RECT  73.968 71.196 73.992 71.28 ;
    END
  END s2[172]
  PIN s2[173]
    DIRECTION OUTPUT ;
    USE SIGNAL ;
    PORT
      LAYER M5 ;
        RECT  74.016 71.196 74.04 71.28 ;
    END
  END s2[173]
  PIN s2[174]
    DIRECTION OUTPUT ;
    USE SIGNAL ;
    PORT
      LAYER M5 ;
        RECT  74.064 71.196 74.088 71.28 ;
    END
  END s2[174]
  PIN s2[175]
    DIRECTION OUTPUT ;
    USE SIGNAL ;
    PORT
      LAYER M5 ;
        RECT  74.112 71.196 74.136 71.28 ;
    END
  END s2[175]
  PIN s2[176]
    DIRECTION OUTPUT ;
    USE SIGNAL ;
    PORT
      LAYER M5 ;
        RECT  74.16 71.196 74.184 71.28 ;
    END
  END s2[176]
  PIN s2[177]
    DIRECTION OUTPUT ;
    USE SIGNAL ;
    PORT
      LAYER M5 ;
        RECT  74.208 71.196 74.232 71.28 ;
    END
  END s2[177]
  PIN s2[178]
    DIRECTION OUTPUT ;
    USE SIGNAL ;
    PORT
      LAYER M5 ;
        RECT  74.256 71.196 74.28 71.28 ;
    END
  END s2[178]
  PIN s2[179]
    DIRECTION OUTPUT ;
    USE SIGNAL ;
    PORT
      LAYER M5 ;
        RECT  74.304 71.196 74.328 71.28 ;
    END
  END s2[179]
  PIN s2[17]
    DIRECTION OUTPUT ;
    USE SIGNAL ;
    PORT
      LAYER M5 ;
        RECT  63.072 71.196 63.096 71.28 ;
    END
  END s2[17]
  PIN s2[180]
    DIRECTION OUTPUT ;
    USE SIGNAL ;
    PORT
      LAYER M5 ;
        RECT  74.352 71.196 74.376 71.28 ;
    END
  END s2[180]
  PIN s2[181]
    DIRECTION OUTPUT ;
    USE SIGNAL ;
    PORT
      LAYER M5 ;
        RECT  74.4 71.196 74.424 71.28 ;
    END
  END s2[181]
  PIN s2[182]
    DIRECTION OUTPUT ;
    USE SIGNAL ;
    PORT
      LAYER M5 ;
        RECT  74.448 71.196 74.472 71.28 ;
    END
  END s2[182]
  PIN s2[183]
    DIRECTION OUTPUT ;
    USE SIGNAL ;
    PORT
      LAYER M5 ;
        RECT  74.496 71.196 74.52 71.28 ;
    END
  END s2[183]
  PIN s2[184]
    DIRECTION OUTPUT ;
    USE SIGNAL ;
    PORT
      LAYER M5 ;
        RECT  74.544 71.196 74.568 71.28 ;
    END
  END s2[184]
  PIN s2[185]
    DIRECTION OUTPUT ;
    USE SIGNAL ;
    PORT
      LAYER M5 ;
        RECT  74.592 71.196 74.616 71.28 ;
    END
  END s2[185]
  PIN s2[186]
    DIRECTION OUTPUT ;
    USE SIGNAL ;
    PORT
      LAYER M5 ;
        RECT  74.64 71.196 74.664 71.28 ;
    END
  END s2[186]
  PIN s2[187]
    DIRECTION OUTPUT ;
    USE SIGNAL ;
    PORT
      LAYER M5 ;
        RECT  74.688 71.196 74.712 71.28 ;
    END
  END s2[187]
  PIN s2[188]
    DIRECTION OUTPUT ;
    USE SIGNAL ;
    PORT
      LAYER M5 ;
        RECT  69.744 71.196 69.768 71.28 ;
    END
  END s2[188]
  PIN s2[189]
    DIRECTION OUTPUT ;
    USE SIGNAL ;
    PORT
      LAYER M5 ;
        RECT  69.792 71.196 69.816 71.28 ;
    END
  END s2[189]
  PIN s2[18]
    DIRECTION OUTPUT ;
    USE SIGNAL ;
    PORT
      LAYER M5 ;
        RECT  63.12 71.196 63.144 71.28 ;
    END
  END s2[18]
  PIN s2[190]
    DIRECTION OUTPUT ;
    USE SIGNAL ;
    PORT
      LAYER M5 ;
        RECT  69.84 71.196 69.864 71.28 ;
    END
  END s2[190]
  PIN s2[191]
    DIRECTION OUTPUT ;
    USE SIGNAL ;
    PORT
      LAYER M5 ;
        RECT  69.888 71.196 69.912 71.28 ;
    END
  END s2[191]
  PIN s2[192]
    DIRECTION OUTPUT ;
    USE SIGNAL ;
    PORT
      LAYER M5 ;
        RECT  69.936 71.196 69.96 71.28 ;
    END
  END s2[192]
  PIN s2[193]
    DIRECTION OUTPUT ;
    USE SIGNAL ;
    PORT
      LAYER M5 ;
        RECT  69.984 71.196 70.008 71.28 ;
    END
  END s2[193]
  PIN s2[194]
    DIRECTION OUTPUT ;
    USE SIGNAL ;
    PORT
      LAYER M5 ;
        RECT  70.032 71.196 70.056 71.28 ;
    END
  END s2[194]
  PIN s2[195]
    DIRECTION OUTPUT ;
    USE SIGNAL ;
    PORT
      LAYER M5 ;
        RECT  70.08 71.196 70.104 71.28 ;
    END
  END s2[195]
  PIN s2[196]
    DIRECTION OUTPUT ;
    USE SIGNAL ;
    PORT
      LAYER M5 ;
        RECT  70.128 71.196 70.152 71.28 ;
    END
  END s2[196]
  PIN s2[197]
    DIRECTION OUTPUT ;
    USE SIGNAL ;
    PORT
      LAYER M5 ;
        RECT  70.176 71.196 70.2 71.28 ;
    END
  END s2[197]
  PIN s2[198]
    DIRECTION OUTPUT ;
    USE SIGNAL ;
    PORT
      LAYER M5 ;
        RECT  70.224 71.196 70.248 71.28 ;
    END
  END s2[198]
  PIN s2[199]
    DIRECTION OUTPUT ;
    USE SIGNAL ;
    PORT
      LAYER M5 ;
        RECT  70.272 71.196 70.296 71.28 ;
    END
  END s2[199]
  PIN s2[19]
    DIRECTION OUTPUT ;
    USE SIGNAL ;
    PORT
      LAYER M5 ;
        RECT  63.168 71.196 63.192 71.28 ;
    END
  END s2[19]
  PIN s2[1]
    DIRECTION OUTPUT ;
    USE SIGNAL ;
    PORT
      LAYER M5 ;
        RECT  62.304 71.196 62.328 71.28 ;
    END
  END s2[1]
  PIN s2[200]
    DIRECTION OUTPUT ;
    USE SIGNAL ;
    PORT
      LAYER M5 ;
        RECT  70.32 71.196 70.344 71.28 ;
    END
  END s2[200]
  PIN s2[201]
    DIRECTION OUTPUT ;
    USE SIGNAL ;
    PORT
      LAYER M5 ;
        RECT  70.368 71.196 70.392 71.28 ;
    END
  END s2[201]
  PIN s2[202]
    DIRECTION OUTPUT ;
    USE SIGNAL ;
    PORT
      LAYER M5 ;
        RECT  70.416 71.196 70.44 71.28 ;
    END
  END s2[202]
  PIN s2[203]
    DIRECTION OUTPUT ;
    USE SIGNAL ;
    PORT
      LAYER M5 ;
        RECT  70.464 71.196 70.488 71.28 ;
    END
  END s2[203]
  PIN s2[204]
    DIRECTION OUTPUT ;
    USE SIGNAL ;
    PORT
      LAYER M5 ;
        RECT  70.512 71.196 70.536 71.28 ;
    END
  END s2[204]
  PIN s2[205]
    DIRECTION OUTPUT ;
    USE SIGNAL ;
    PORT
      LAYER M5 ;
        RECT  70.56 71.196 70.584 71.28 ;
    END
  END s2[205]
  PIN s2[206]
    DIRECTION OUTPUT ;
    USE SIGNAL ;
    PORT
      LAYER M5 ;
        RECT  70.608 71.196 70.632 71.28 ;
    END
  END s2[206]
  PIN s2[207]
    DIRECTION OUTPUT ;
    USE SIGNAL ;
    PORT
      LAYER M5 ;
        RECT  70.656 71.196 70.68 71.28 ;
    END
  END s2[207]
  PIN s2[208]
    DIRECTION OUTPUT ;
    USE SIGNAL ;
    PORT
      LAYER M5 ;
        RECT  70.704 71.196 70.728 71.28 ;
    END
  END s2[208]
  PIN s2[209]
    DIRECTION OUTPUT ;
    USE SIGNAL ;
    PORT
      LAYER M5 ;
        RECT  70.752 71.196 70.776 71.28 ;
    END
  END s2[209]
  PIN s2[20]
    DIRECTION OUTPUT ;
    USE SIGNAL ;
    PORT
      LAYER M5 ;
        RECT  63.216 71.196 63.24 71.28 ;
    END
  END s2[20]
  PIN s2[210]
    DIRECTION OUTPUT ;
    USE SIGNAL ;
    PORT
      LAYER M5 ;
        RECT  70.8 71.196 70.824 71.28 ;
    END
  END s2[210]
  PIN s2[211]
    DIRECTION OUTPUT ;
    USE SIGNAL ;
    PORT
      LAYER M5 ;
        RECT  70.848 71.196 70.872 71.28 ;
    END
  END s2[211]
  PIN s2[212]
    DIRECTION OUTPUT ;
    USE SIGNAL ;
    PORT
      LAYER M5 ;
        RECT  70.896 71.196 70.92 71.28 ;
    END
  END s2[212]
  PIN s2[213]
    DIRECTION OUTPUT ;
    USE SIGNAL ;
    PORT
      LAYER M5 ;
        RECT  70.944 71.196 70.968 71.28 ;
    END
  END s2[213]
  PIN s2[214]
    DIRECTION OUTPUT ;
    USE SIGNAL ;
    PORT
      LAYER M5 ;
        RECT  70.992 71.196 71.016 71.28 ;
    END
  END s2[214]
  PIN s2[215]
    DIRECTION OUTPUT ;
    USE SIGNAL ;
    PORT
      LAYER M5 ;
        RECT  71.04 71.196 71.064 71.28 ;
    END
  END s2[215]
  PIN s2[216]
    DIRECTION OUTPUT ;
    USE SIGNAL ;
    PORT
      LAYER M5 ;
        RECT  71.088 71.196 71.112 71.28 ;
    END
  END s2[216]
  PIN s2[217]
    DIRECTION OUTPUT ;
    USE SIGNAL ;
    PORT
      LAYER M5 ;
        RECT  71.136 71.196 71.16 71.28 ;
    END
  END s2[217]
  PIN s2[218]
    DIRECTION OUTPUT ;
    USE SIGNAL ;
    PORT
      LAYER M5 ;
        RECT  71.184 71.196 71.208 71.28 ;
    END
  END s2[218]
  PIN s2[219]
    DIRECTION OUTPUT ;
    USE SIGNAL ;
    PORT
      LAYER M5 ;
        RECT  71.232 71.196 71.256 71.28 ;
    END
  END s2[219]
  PIN s2[21]
    DIRECTION OUTPUT ;
    USE SIGNAL ;
    PORT
      LAYER M5 ;
        RECT  63.264 71.196 63.288 71.28 ;
    END
  END s2[21]
  PIN s2[220]
    DIRECTION OUTPUT ;
    USE SIGNAL ;
    PORT
      LAYER M5 ;
        RECT  76.272 71.196 76.296 71.28 ;
    END
  END s2[220]
  PIN s2[221]
    DIRECTION OUTPUT ;
    USE SIGNAL ;
    PORT
      LAYER M5 ;
        RECT  76.32 71.196 76.344 71.28 ;
    END
  END s2[221]
  PIN s2[222]
    DIRECTION OUTPUT ;
    USE SIGNAL ;
    PORT
      LAYER M5 ;
        RECT  76.368 71.196 76.392 71.28 ;
    END
  END s2[222]
  PIN s2[223]
    DIRECTION OUTPUT ;
    USE SIGNAL ;
    PORT
      LAYER M5 ;
        RECT  76.416 71.196 76.44 71.28 ;
    END
  END s2[223]
  PIN s2[224]
    DIRECTION OUTPUT ;
    USE SIGNAL ;
    PORT
      LAYER M5 ;
        RECT  76.464 71.196 76.488 71.28 ;
    END
  END s2[224]
  PIN s2[225]
    DIRECTION OUTPUT ;
    USE SIGNAL ;
    PORT
      LAYER M5 ;
        RECT  76.512 71.196 76.536 71.28 ;
    END
  END s2[225]
  PIN s2[226]
    DIRECTION OUTPUT ;
    USE SIGNAL ;
    PORT
      LAYER M5 ;
        RECT  76.56 71.196 76.584 71.28 ;
    END
  END s2[226]
  PIN s2[227]
    DIRECTION OUTPUT ;
    USE SIGNAL ;
    PORT
      LAYER M5 ;
        RECT  76.608 71.196 76.632 71.28 ;
    END
  END s2[227]
  PIN s2[228]
    DIRECTION OUTPUT ;
    USE SIGNAL ;
    PORT
      LAYER M5 ;
        RECT  76.656 71.196 76.68 71.28 ;
    END
  END s2[228]
  PIN s2[229]
    DIRECTION OUTPUT ;
    USE SIGNAL ;
    PORT
      LAYER M5 ;
        RECT  76.704 71.196 76.728 71.28 ;
    END
  END s2[229]
  PIN s2[22]
    DIRECTION OUTPUT ;
    USE SIGNAL ;
    PORT
      LAYER M5 ;
        RECT  63.312 71.196 63.336 71.28 ;
    END
  END s2[22]
  PIN s2[230]
    DIRECTION OUTPUT ;
    USE SIGNAL ;
    PORT
      LAYER M5 ;
        RECT  76.752 71.196 76.776 71.28 ;
    END
  END s2[230]
  PIN s2[231]
    DIRECTION OUTPUT ;
    USE SIGNAL ;
    PORT
      LAYER M5 ;
        RECT  76.8 71.196 76.824 71.28 ;
    END
  END s2[231]
  PIN s2[232]
    DIRECTION OUTPUT ;
    USE SIGNAL ;
    PORT
      LAYER M5 ;
        RECT  76.848 71.196 76.872 71.28 ;
    END
  END s2[232]
  PIN s2[233]
    DIRECTION OUTPUT ;
    USE SIGNAL ;
    PORT
      LAYER M5 ;
        RECT  76.896 71.196 76.92 71.28 ;
    END
  END s2[233]
  PIN s2[234]
    DIRECTION OUTPUT ;
    USE SIGNAL ;
    PORT
      LAYER M5 ;
        RECT  76.944 71.196 76.968 71.28 ;
    END
  END s2[234]
  PIN s2[235]
    DIRECTION OUTPUT ;
    USE SIGNAL ;
    PORT
      LAYER M5 ;
        RECT  76.992 71.196 77.016 71.28 ;
    END
  END s2[235]
  PIN s2[236]
    DIRECTION OUTPUT ;
    USE SIGNAL ;
    PORT
      LAYER M5 ;
        RECT  77.04 71.196 77.064 71.28 ;
    END
  END s2[236]
  PIN s2[237]
    DIRECTION OUTPUT ;
    USE SIGNAL ;
    PORT
      LAYER M5 ;
        RECT  77.088 71.196 77.112 71.28 ;
    END
  END s2[237]
  PIN s2[238]
    DIRECTION OUTPUT ;
    USE SIGNAL ;
    PORT
      LAYER M5 ;
        RECT  77.136 71.196 77.16 71.28 ;
    END
  END s2[238]
  PIN s2[239]
    DIRECTION OUTPUT ;
    USE SIGNAL ;
    PORT
      LAYER M5 ;
        RECT  77.184 71.196 77.208 71.28 ;
    END
  END s2[239]
  PIN s2[23]
    DIRECTION OUTPUT ;
    USE SIGNAL ;
    PORT
      LAYER M5 ;
        RECT  63.36 71.196 63.384 71.28 ;
    END
  END s2[23]
  PIN s2[240]
    DIRECTION OUTPUT ;
    USE SIGNAL ;
    PORT
      LAYER M5 ;
        RECT  77.232 71.196 77.256 71.28 ;
    END
  END s2[240]
  PIN s2[241]
    DIRECTION OUTPUT ;
    USE SIGNAL ;
    PORT
      LAYER M5 ;
        RECT  77.28 71.196 77.304 71.28 ;
    END
  END s2[241]
  PIN s2[242]
    DIRECTION OUTPUT ;
    USE SIGNAL ;
    PORT
      LAYER M5 ;
        RECT  77.328 71.196 77.352 71.28 ;
    END
  END s2[242]
  PIN s2[243]
    DIRECTION OUTPUT ;
    USE SIGNAL ;
    PORT
      LAYER M5 ;
        RECT  77.376 71.196 77.4 71.28 ;
    END
  END s2[243]
  PIN s2[244]
    DIRECTION OUTPUT ;
    USE SIGNAL ;
    PORT
      LAYER M5 ;
        RECT  77.424 71.196 77.448 71.28 ;
    END
  END s2[244]
  PIN s2[245]
    DIRECTION OUTPUT ;
    USE SIGNAL ;
    PORT
      LAYER M5 ;
        RECT  77.472 71.196 77.496 71.28 ;
    END
  END s2[245]
  PIN s2[246]
    DIRECTION OUTPUT ;
    USE SIGNAL ;
    PORT
      LAYER M5 ;
        RECT  77.52 71.196 77.544 71.28 ;
    END
  END s2[246]
  PIN s2[247]
    DIRECTION OUTPUT ;
    USE SIGNAL ;
    PORT
      LAYER M5 ;
        RECT  77.568 71.196 77.592 71.28 ;
    END
  END s2[247]
  PIN s2[248]
    DIRECTION OUTPUT ;
    USE SIGNAL ;
    PORT
      LAYER M5 ;
        RECT  77.616 71.196 77.64 71.28 ;
    END
  END s2[248]
  PIN s2[249]
    DIRECTION OUTPUT ;
    USE SIGNAL ;
    PORT
      LAYER M5 ;
        RECT  77.664 71.196 77.688 71.28 ;
    END
  END s2[249]
  PIN s2[24]
    DIRECTION OUTPUT ;
    USE SIGNAL ;
    PORT
      LAYER M5 ;
        RECT  63.408 71.196 63.432 71.28 ;
    END
  END s2[24]
  PIN s2[250]
    DIRECTION OUTPUT ;
    USE SIGNAL ;
    PORT
      LAYER M5 ;
        RECT  77.712 71.196 77.736 71.28 ;
    END
  END s2[250]
  PIN s2[251]
    DIRECTION OUTPUT ;
    USE SIGNAL ;
    PORT
      LAYER M5 ;
        RECT  77.76 71.196 77.784 71.28 ;
    END
  END s2[251]
  PIN s2[252]
    DIRECTION OUTPUT ;
    USE SIGNAL ;
    PORT
      LAYER M5 ;
        RECT  79.344 71.196 79.368 71.28 ;
    END
  END s2[252]
  PIN s2[253]
    DIRECTION OUTPUT ;
    USE SIGNAL ;
    PORT
      LAYER M5 ;
        RECT  79.392 71.196 79.416 71.28 ;
    END
  END s2[253]
  PIN s2[254]
    DIRECTION OUTPUT ;
    USE SIGNAL ;
    PORT
      LAYER M5 ;
        RECT  79.44 71.196 79.464 71.28 ;
    END
  END s2[254]
  PIN s2[255]
    DIRECTION OUTPUT ;
    USE SIGNAL ;
    PORT
      LAYER M5 ;
        RECT  79.488 71.196 79.512 71.28 ;
    END
  END s2[255]
  PIN s2[256]
    DIRECTION OUTPUT ;
    USE SIGNAL ;
    PORT
      LAYER M5 ;
        RECT  79.536 71.196 79.56 71.28 ;
    END
  END s2[256]
  PIN s2[257]
    DIRECTION OUTPUT ;
    USE SIGNAL ;
    PORT
      LAYER M5 ;
        RECT  79.584 71.196 79.608 71.28 ;
    END
  END s2[257]
  PIN s2[258]
    DIRECTION OUTPUT ;
    USE SIGNAL ;
    PORT
      LAYER M5 ;
        RECT  79.632 71.196 79.656 71.28 ;
    END
  END s2[258]
  PIN s2[259]
    DIRECTION OUTPUT ;
    USE SIGNAL ;
    PORT
      LAYER M5 ;
        RECT  79.68 71.196 79.704 71.28 ;
    END
  END s2[259]
  PIN s2[25]
    DIRECTION OUTPUT ;
    USE SIGNAL ;
    PORT
      LAYER M5 ;
        RECT  63.456 71.196 63.48 71.28 ;
    END
  END s2[25]
  PIN s2[260]
    DIRECTION OUTPUT ;
    USE SIGNAL ;
    PORT
      LAYER M5 ;
        RECT  79.728 71.196 79.752 71.28 ;
    END
  END s2[260]
  PIN s2[261]
    DIRECTION OUTPUT ;
    USE SIGNAL ;
    PORT
      LAYER M5 ;
        RECT  79.776 71.196 79.8 71.28 ;
    END
  END s2[261]
  PIN s2[262]
    DIRECTION OUTPUT ;
    USE SIGNAL ;
    PORT
      LAYER M5 ;
        RECT  79.824 71.196 79.848 71.28 ;
    END
  END s2[262]
  PIN s2[263]
    DIRECTION OUTPUT ;
    USE SIGNAL ;
    PORT
      LAYER M5 ;
        RECT  79.872 71.196 79.896 71.28 ;
    END
  END s2[263]
  PIN s2[264]
    DIRECTION OUTPUT ;
    USE SIGNAL ;
    PORT
      LAYER M5 ;
        RECT  79.92 71.196 79.944 71.28 ;
    END
  END s2[264]
  PIN s2[265]
    DIRECTION OUTPUT ;
    USE SIGNAL ;
    PORT
      LAYER M5 ;
        RECT  79.968 71.196 79.992 71.28 ;
    END
  END s2[265]
  PIN s2[266]
    DIRECTION OUTPUT ;
    USE SIGNAL ;
    PORT
      LAYER M5 ;
        RECT  80.016 71.196 80.04 71.28 ;
    END
  END s2[266]
  PIN s2[267]
    DIRECTION OUTPUT ;
    USE SIGNAL ;
    PORT
      LAYER M5 ;
        RECT  80.064 71.196 80.088 71.28 ;
    END
  END s2[267]
  PIN s2[268]
    DIRECTION OUTPUT ;
    USE SIGNAL ;
    PORT
      LAYER M5 ;
        RECT  80.112 71.196 80.136 71.28 ;
    END
  END s2[268]
  PIN s2[269]
    DIRECTION OUTPUT ;
    USE SIGNAL ;
    PORT
      LAYER M5 ;
        RECT  80.16 71.196 80.184 71.28 ;
    END
  END s2[269]
  PIN s2[26]
    DIRECTION OUTPUT ;
    USE SIGNAL ;
    PORT
      LAYER M5 ;
        RECT  63.504 71.196 63.528 71.28 ;
    END
  END s2[26]
  PIN s2[270]
    DIRECTION OUTPUT ;
    USE SIGNAL ;
    PORT
      LAYER M5 ;
        RECT  80.208 71.196 80.232 71.28 ;
    END
  END s2[270]
  PIN s2[271]
    DIRECTION OUTPUT ;
    USE SIGNAL ;
    PORT
      LAYER M5 ;
        RECT  80.256 71.196 80.28 71.28 ;
    END
  END s2[271]
  PIN s2[272]
    DIRECTION OUTPUT ;
    USE SIGNAL ;
    PORT
      LAYER M5 ;
        RECT  80.304 71.196 80.328 71.28 ;
    END
  END s2[272]
  PIN s2[273]
    DIRECTION OUTPUT ;
    USE SIGNAL ;
    PORT
      LAYER M5 ;
        RECT  80.352 71.196 80.376 71.28 ;
    END
  END s2[273]
  PIN s2[274]
    DIRECTION OUTPUT ;
    USE SIGNAL ;
    PORT
      LAYER M5 ;
        RECT  80.4 71.196 80.424 71.28 ;
    END
  END s2[274]
  PIN s2[275]
    DIRECTION OUTPUT ;
    USE SIGNAL ;
    PORT
      LAYER M5 ;
        RECT  80.448 71.196 80.472 71.28 ;
    END
  END s2[275]
  PIN s2[276]
    DIRECTION OUTPUT ;
    USE SIGNAL ;
    PORT
      LAYER M5 ;
        RECT  80.496 71.196 80.52 71.28 ;
    END
  END s2[276]
  PIN s2[277]
    DIRECTION OUTPUT ;
    USE SIGNAL ;
    PORT
      LAYER M5 ;
        RECT  80.544 71.196 80.568 71.28 ;
    END
  END s2[277]
  PIN s2[278]
    DIRECTION OUTPUT ;
    USE SIGNAL ;
    PORT
      LAYER M5 ;
        RECT  80.592 71.196 80.616 71.28 ;
    END
  END s2[278]
  PIN s2[279]
    DIRECTION OUTPUT ;
    USE SIGNAL ;
    PORT
      LAYER M5 ;
        RECT  80.64 71.196 80.664 71.28 ;
    END
  END s2[279]
  PIN s2[27]
    DIRECTION OUTPUT ;
    USE SIGNAL ;
    PORT
      LAYER M5 ;
        RECT  63.552 71.196 63.576 71.28 ;
    END
  END s2[27]
  PIN s2[280]
    DIRECTION OUTPUT ;
    USE SIGNAL ;
    PORT
      LAYER M5 ;
        RECT  80.688 71.196 80.712 71.28 ;
    END
  END s2[280]
  PIN s2[281]
    DIRECTION OUTPUT ;
    USE SIGNAL ;
    PORT
      LAYER M5 ;
        RECT  80.736 71.196 80.76 71.28 ;
    END
  END s2[281]
  PIN s2[282]
    DIRECTION OUTPUT ;
    USE SIGNAL ;
    PORT
      LAYER M5 ;
        RECT  80.784 71.196 80.808 71.28 ;
    END
  END s2[282]
  PIN s2[283]
    DIRECTION OUTPUT ;
    USE SIGNAL ;
    PORT
      LAYER M5 ;
        RECT  80.832 71.196 80.856 71.28 ;
    END
  END s2[283]
  PIN s2[284]
    DIRECTION OUTPUT ;
    USE SIGNAL ;
    PORT
      LAYER M5 ;
        RECT  82.8 71.196 82.824 71.28 ;
    END
  END s2[284]
  PIN s2[285]
    DIRECTION OUTPUT ;
    USE SIGNAL ;
    PORT
      LAYER M5 ;
        RECT  82.848 71.196 82.872 71.28 ;
    END
  END s2[285]
  PIN s2[286]
    DIRECTION OUTPUT ;
    USE SIGNAL ;
    PORT
      LAYER M5 ;
        RECT  82.896 71.196 82.92 71.28 ;
    END
  END s2[286]
  PIN s2[287]
    DIRECTION OUTPUT ;
    USE SIGNAL ;
    PORT
      LAYER M5 ;
        RECT  82.944 71.196 82.968 71.28 ;
    END
  END s2[287]
  PIN s2[288]
    DIRECTION OUTPUT ;
    USE SIGNAL ;
    PORT
      LAYER M5 ;
        RECT  82.992 71.196 83.016 71.28 ;
    END
  END s2[288]
  PIN s2[289]
    DIRECTION OUTPUT ;
    USE SIGNAL ;
    PORT
      LAYER M5 ;
        RECT  83.04 71.196 83.064 71.28 ;
    END
  END s2[289]
  PIN s2[28]
    DIRECTION OUTPUT ;
    USE SIGNAL ;
    PORT
      LAYER M5 ;
        RECT  71.664 71.196 71.688 71.28 ;
    END
  END s2[28]
  PIN s2[290]
    DIRECTION OUTPUT ;
    USE SIGNAL ;
    PORT
      LAYER M5 ;
        RECT  83.088 71.196 83.112 71.28 ;
    END
  END s2[290]
  PIN s2[291]
    DIRECTION OUTPUT ;
    USE SIGNAL ;
    PORT
      LAYER M5 ;
        RECT  83.136 71.196 83.16 71.28 ;
    END
  END s2[291]
  PIN s2[292]
    DIRECTION OUTPUT ;
    USE SIGNAL ;
    PORT
      LAYER M5 ;
        RECT  83.184 71.196 83.208 71.28 ;
    END
  END s2[292]
  PIN s2[293]
    DIRECTION OUTPUT ;
    USE SIGNAL ;
    PORT
      LAYER M5 ;
        RECT  83.232 71.196 83.256 71.28 ;
    END
  END s2[293]
  PIN s2[294]
    DIRECTION OUTPUT ;
    USE SIGNAL ;
    PORT
      LAYER M5 ;
        RECT  83.28 71.196 83.304 71.28 ;
    END
  END s2[294]
  PIN s2[295]
    DIRECTION OUTPUT ;
    USE SIGNAL ;
    PORT
      LAYER M5 ;
        RECT  83.328 71.196 83.352 71.28 ;
    END
  END s2[295]
  PIN s2[296]
    DIRECTION OUTPUT ;
    USE SIGNAL ;
    PORT
      LAYER M5 ;
        RECT  83.376 71.196 83.4 71.28 ;
    END
  END s2[296]
  PIN s2[297]
    DIRECTION OUTPUT ;
    USE SIGNAL ;
    PORT
      LAYER M5 ;
        RECT  83.424 71.196 83.448 71.28 ;
    END
  END s2[297]
  PIN s2[298]
    DIRECTION OUTPUT ;
    USE SIGNAL ;
    PORT
      LAYER M5 ;
        RECT  83.472 71.196 83.496 71.28 ;
    END
  END s2[298]
  PIN s2[299]
    DIRECTION OUTPUT ;
    USE SIGNAL ;
    PORT
      LAYER M5 ;
        RECT  83.52 71.196 83.544 71.28 ;
    END
  END s2[299]
  PIN s2[29]
    DIRECTION OUTPUT ;
    USE SIGNAL ;
    PORT
      LAYER M5 ;
        RECT  71.712 71.196 71.736 71.28 ;
    END
  END s2[29]
  PIN s2[2]
    DIRECTION OUTPUT ;
    USE SIGNAL ;
    PORT
      LAYER M5 ;
        RECT  62.352 71.196 62.376 71.28 ;
    END
  END s2[2]
  PIN s2[300]
    DIRECTION OUTPUT ;
    USE SIGNAL ;
    PORT
      LAYER M5 ;
        RECT  83.568 71.196 83.592 71.28 ;
    END
  END s2[300]
  PIN s2[301]
    DIRECTION OUTPUT ;
    USE SIGNAL ;
    PORT
      LAYER M5 ;
        RECT  83.616 71.196 83.64 71.28 ;
    END
  END s2[301]
  PIN s2[302]
    DIRECTION OUTPUT ;
    USE SIGNAL ;
    PORT
      LAYER M5 ;
        RECT  83.664 71.196 83.688 71.28 ;
    END
  END s2[302]
  PIN s2[303]
    DIRECTION OUTPUT ;
    USE SIGNAL ;
    PORT
      LAYER M5 ;
        RECT  83.712 71.196 83.736 71.28 ;
    END
  END s2[303]
  PIN s2[304]
    DIRECTION OUTPUT ;
    USE SIGNAL ;
    PORT
      LAYER M5 ;
        RECT  83.76 71.196 83.784 71.28 ;
    END
  END s2[304]
  PIN s2[305]
    DIRECTION OUTPUT ;
    USE SIGNAL ;
    PORT
      LAYER M5 ;
        RECT  83.808 71.196 83.832 71.28 ;
    END
  END s2[305]
  PIN s2[306]
    DIRECTION OUTPUT ;
    USE SIGNAL ;
    PORT
      LAYER M5 ;
        RECT  83.856 71.196 83.88 71.28 ;
    END
  END s2[306]
  PIN s2[307]
    DIRECTION OUTPUT ;
    USE SIGNAL ;
    PORT
      LAYER M5 ;
        RECT  83.904 71.196 83.928 71.28 ;
    END
  END s2[307]
  PIN s2[308]
    DIRECTION OUTPUT ;
    USE SIGNAL ;
    PORT
      LAYER M5 ;
        RECT  83.952 71.196 83.976 71.28 ;
    END
  END s2[308]
  PIN s2[309]
    DIRECTION OUTPUT ;
    USE SIGNAL ;
    PORT
      LAYER M5 ;
        RECT  84 71.196 84.024 71.28 ;
    END
  END s2[309]
  PIN s2[30]
    DIRECTION OUTPUT ;
    USE SIGNAL ;
    PORT
      LAYER M5 ;
        RECT  71.76 71.196 71.784 71.28 ;
    END
  END s2[30]
  PIN s2[310]
    DIRECTION OUTPUT ;
    USE SIGNAL ;
    PORT
      LAYER M5 ;
        RECT  84.048 71.196 84.072 71.28 ;
    END
  END s2[310]
  PIN s2[311]
    DIRECTION OUTPUT ;
    USE SIGNAL ;
    PORT
      LAYER M5 ;
        RECT  84.096 71.196 84.12 71.28 ;
    END
  END s2[311]
  PIN s2[312]
    DIRECTION OUTPUT ;
    USE SIGNAL ;
    PORT
      LAYER M5 ;
        RECT  84.144 71.196 84.168 71.28 ;
    END
  END s2[312]
  PIN s2[313]
    DIRECTION OUTPUT ;
    USE SIGNAL ;
    PORT
      LAYER M5 ;
        RECT  84.192 71.196 84.216 71.28 ;
    END
  END s2[313]
  PIN s2[314]
    DIRECTION OUTPUT ;
    USE SIGNAL ;
    PORT
      LAYER M5 ;
        RECT  84.24 71.196 84.264 71.28 ;
    END
  END s2[314]
  PIN s2[315]
    DIRECTION OUTPUT ;
    USE SIGNAL ;
    PORT
      LAYER M5 ;
        RECT  84.288 71.196 84.312 71.28 ;
    END
  END s2[315]
  PIN s2[316]
    DIRECTION OUTPUT ;
    USE SIGNAL ;
    PORT
      LAYER M5 ;
        RECT  81.936 71.196 81.96 71.28 ;
    END
  END s2[316]
  PIN s2[317]
    DIRECTION OUTPUT ;
    USE SIGNAL ;
    PORT
      LAYER M5 ;
        RECT  81.984 71.196 82.008 71.28 ;
    END
  END s2[317]
  PIN s2[318]
    DIRECTION OUTPUT ;
    USE SIGNAL ;
    PORT
      LAYER M5 ;
        RECT  82.032 71.196 82.056 71.28 ;
    END
  END s2[318]
  PIN s2[319]
    DIRECTION OUTPUT ;
    USE SIGNAL ;
    PORT
      LAYER M5 ;
        RECT  82.08 71.196 82.104 71.28 ;
    END
  END s2[319]
  PIN s2[31]
    DIRECTION OUTPUT ;
    USE SIGNAL ;
    PORT
      LAYER M5 ;
        RECT  71.808 71.196 71.832 71.28 ;
    END
  END s2[31]
  PIN s2[320]
    DIRECTION OUTPUT ;
    USE SIGNAL ;
    PORT
      LAYER M5 ;
        RECT  82.128 71.196 82.152 71.28 ;
    END
  END s2[320]
  PIN s2[321]
    DIRECTION OUTPUT ;
    USE SIGNAL ;
    PORT
      LAYER M5 ;
        RECT  82.176 71.196 82.2 71.28 ;
    END
  END s2[321]
  PIN s2[322]
    DIRECTION OUTPUT ;
    USE SIGNAL ;
    PORT
      LAYER M5 ;
        RECT  82.224 71.196 82.248 71.28 ;
    END
  END s2[322]
  PIN s2[323]
    DIRECTION OUTPUT ;
    USE SIGNAL ;
    PORT
      LAYER M5 ;
        RECT  82.272 71.196 82.296 71.28 ;
    END
  END s2[323]
  PIN s2[324]
    DIRECTION OUTPUT ;
    USE SIGNAL ;
    PORT
      LAYER M5 ;
        RECT  82.32 71.196 82.344 71.28 ;
    END
  END s2[324]
  PIN s2[325]
    DIRECTION OUTPUT ;
    USE SIGNAL ;
    PORT
      LAYER M5 ;
        RECT  82.368 71.196 82.392 71.28 ;
    END
  END s2[325]
  PIN s2[326]
    DIRECTION OUTPUT ;
    USE SIGNAL ;
    PORT
      LAYER M5 ;
        RECT  82.416 71.196 82.44 71.28 ;
    END
  END s2[326]
  PIN s2[327]
    DIRECTION OUTPUT ;
    USE SIGNAL ;
    PORT
      LAYER M5 ;
        RECT  82.464 71.196 82.488 71.28 ;
    END
  END s2[327]
  PIN s2[328]
    DIRECTION OUTPUT ;
    USE SIGNAL ;
    PORT
      LAYER M5 ;
        RECT  82.512 71.196 82.536 71.28 ;
    END
  END s2[328]
  PIN s2[329]
    DIRECTION OUTPUT ;
    USE SIGNAL ;
    PORT
      LAYER M5 ;
        RECT  82.56 71.196 82.584 71.28 ;
    END
  END s2[329]
  PIN s2[32]
    DIRECTION OUTPUT ;
    USE SIGNAL ;
    PORT
      LAYER M5 ;
        RECT  71.856 71.196 71.88 71.28 ;
    END
  END s2[32]
  PIN s2[330]
    DIRECTION OUTPUT ;
    USE SIGNAL ;
    PORT
      LAYER M5 ;
        RECT  82.608 71.196 82.632 71.28 ;
    END
  END s2[330]
  PIN s2[331]
    DIRECTION OUTPUT ;
    USE SIGNAL ;
    PORT
      LAYER M5 ;
        RECT  82.656 71.196 82.68 71.28 ;
    END
  END s2[331]
  PIN s2[332]
    DIRECTION OUTPUT ;
    USE SIGNAL ;
    PORT
      LAYER M5 ;
        RECT  82.704 71.196 82.728 71.28 ;
    END
  END s2[332]
  PIN s2[33]
    DIRECTION OUTPUT ;
    USE SIGNAL ;
    PORT
      LAYER M5 ;
        RECT  71.904 71.196 71.928 71.28 ;
    END
  END s2[33]
  PIN s2[34]
    DIRECTION OUTPUT ;
    USE SIGNAL ;
    PORT
      LAYER M5 ;
        RECT  71.952 71.196 71.976 71.28 ;
    END
  END s2[34]
  PIN s2[35]
    DIRECTION OUTPUT ;
    USE SIGNAL ;
    PORT
      LAYER M5 ;
        RECT  72 71.196 72.024 71.28 ;
    END
  END s2[35]
  PIN s2[36]
    DIRECTION OUTPUT ;
    USE SIGNAL ;
    PORT
      LAYER M5 ;
        RECT  72.048 71.196 72.072 71.28 ;
    END
  END s2[36]
  PIN s2[37]
    DIRECTION OUTPUT ;
    USE SIGNAL ;
    PORT
      LAYER M5 ;
        RECT  72.096 71.196 72.12 71.28 ;
    END
  END s2[37]
  PIN s2[38]
    DIRECTION OUTPUT ;
    USE SIGNAL ;
    PORT
      LAYER M5 ;
        RECT  72.144 71.196 72.168 71.28 ;
    END
  END s2[38]
  PIN s2[39]
    DIRECTION OUTPUT ;
    USE SIGNAL ;
    PORT
      LAYER M5 ;
        RECT  72.192 71.196 72.216 71.28 ;
    END
  END s2[39]
  PIN s2[3]
    DIRECTION OUTPUT ;
    USE SIGNAL ;
    PORT
      LAYER M5 ;
        RECT  62.4 71.196 62.424 71.28 ;
    END
  END s2[3]
  PIN s2[40]
    DIRECTION OUTPUT ;
    USE SIGNAL ;
    PORT
      LAYER M5 ;
        RECT  72.24 71.196 72.264 71.28 ;
    END
  END s2[40]
  PIN s2[41]
    DIRECTION OUTPUT ;
    USE SIGNAL ;
    PORT
      LAYER M5 ;
        RECT  72.288 71.196 72.312 71.28 ;
    END
  END s2[41]
  PIN s2[42]
    DIRECTION OUTPUT ;
    USE SIGNAL ;
    PORT
      LAYER M5 ;
        RECT  72.336 71.196 72.36 71.28 ;
    END
  END s2[42]
  PIN s2[43]
    DIRECTION OUTPUT ;
    USE SIGNAL ;
    PORT
      LAYER M5 ;
        RECT  72.384 71.196 72.408 71.28 ;
    END
  END s2[43]
  PIN s2[44]
    DIRECTION OUTPUT ;
    USE SIGNAL ;
    PORT
      LAYER M5 ;
        RECT  72.432 71.196 72.456 71.28 ;
    END
  END s2[44]
  PIN s2[45]
    DIRECTION OUTPUT ;
    USE SIGNAL ;
    PORT
      LAYER M5 ;
        RECT  72.48 71.196 72.504 71.28 ;
    END
  END s2[45]
  PIN s2[46]
    DIRECTION OUTPUT ;
    USE SIGNAL ;
    PORT
      LAYER M5 ;
        RECT  72.528 71.196 72.552 71.28 ;
    END
  END s2[46]
  PIN s2[47]
    DIRECTION OUTPUT ;
    USE SIGNAL ;
    PORT
      LAYER M5 ;
        RECT  72.576 71.196 72.6 71.28 ;
    END
  END s2[47]
  PIN s2[48]
    DIRECTION OUTPUT ;
    USE SIGNAL ;
    PORT
      LAYER M5 ;
        RECT  72.624 71.196 72.648 71.28 ;
    END
  END s2[48]
  PIN s2[49]
    DIRECTION OUTPUT ;
    USE SIGNAL ;
    PORT
      LAYER M5 ;
        RECT  72.672 71.196 72.696 71.28 ;
    END
  END s2[49]
  PIN s2[4]
    DIRECTION OUTPUT ;
    USE SIGNAL ;
    PORT
      LAYER M5 ;
        RECT  62.448 71.196 62.472 71.28 ;
    END
  END s2[4]
  PIN s2[50]
    DIRECTION OUTPUT ;
    USE SIGNAL ;
    PORT
      LAYER M5 ;
        RECT  72.72 71.196 72.744 71.28 ;
    END
  END s2[50]
  PIN s2[51]
    DIRECTION OUTPUT ;
    USE SIGNAL ;
    PORT
      LAYER M5 ;
        RECT  72.768 71.196 72.792 71.28 ;
    END
  END s2[51]
  PIN s2[52]
    DIRECTION OUTPUT ;
    USE SIGNAL ;
    PORT
      LAYER M5 ;
        RECT  72.816 71.196 72.84 71.28 ;
    END
  END s2[52]
  PIN s2[53]
    DIRECTION OUTPUT ;
    USE SIGNAL ;
    PORT
      LAYER M5 ;
        RECT  72.864 71.196 72.888 71.28 ;
    END
  END s2[53]
  PIN s2[54]
    DIRECTION OUTPUT ;
    USE SIGNAL ;
    PORT
      LAYER M5 ;
        RECT  72.912 71.196 72.936 71.28 ;
    END
  END s2[54]
  PIN s2[55]
    DIRECTION OUTPUT ;
    USE SIGNAL ;
    PORT
      LAYER M5 ;
        RECT  72.96 71.196 72.984 71.28 ;
    END
  END s2[55]
  PIN s2[56]
    DIRECTION OUTPUT ;
    USE SIGNAL ;
    PORT
      LAYER M5 ;
        RECT  73.008 71.196 73.032 71.28 ;
    END
  END s2[56]
  PIN s2[57]
    DIRECTION OUTPUT ;
    USE SIGNAL ;
    PORT
      LAYER M5 ;
        RECT  73.056 71.196 73.08 71.28 ;
    END
  END s2[57]
  PIN s2[58]
    DIRECTION OUTPUT ;
    USE SIGNAL ;
    PORT
      LAYER M5 ;
        RECT  73.104 71.196 73.128 71.28 ;
    END
  END s2[58]
  PIN s2[59]
    DIRECTION OUTPUT ;
    USE SIGNAL ;
    PORT
      LAYER M5 ;
        RECT  73.152 71.196 73.176 71.28 ;
    END
  END s2[59]
  PIN s2[5]
    DIRECTION OUTPUT ;
    USE SIGNAL ;
    PORT
      LAYER M5 ;
        RECT  62.496 71.196 62.52 71.28 ;
    END
  END s2[5]
  PIN s2[60]
    DIRECTION OUTPUT ;
    USE SIGNAL ;
    PORT
      LAYER M5 ;
        RECT  77.808 71.196 77.832 71.28 ;
    END
  END s2[60]
  PIN s2[61]
    DIRECTION OUTPUT ;
    USE SIGNAL ;
    PORT
      LAYER M5 ;
        RECT  77.856 71.196 77.88 71.28 ;
    END
  END s2[61]
  PIN s2[62]
    DIRECTION OUTPUT ;
    USE SIGNAL ;
    PORT
      LAYER M5 ;
        RECT  77.904 71.196 77.928 71.28 ;
    END
  END s2[62]
  PIN s2[63]
    DIRECTION OUTPUT ;
    USE SIGNAL ;
    PORT
      LAYER M5 ;
        RECT  77.952 71.196 77.976 71.28 ;
    END
  END s2[63]
  PIN s2[64]
    DIRECTION OUTPUT ;
    USE SIGNAL ;
    PORT
      LAYER M5 ;
        RECT  78 71.196 78.024 71.28 ;
    END
  END s2[64]
  PIN s2[65]
    DIRECTION OUTPUT ;
    USE SIGNAL ;
    PORT
      LAYER M5 ;
        RECT  78.048 71.196 78.072 71.28 ;
    END
  END s2[65]
  PIN s2[66]
    DIRECTION OUTPUT ;
    USE SIGNAL ;
    PORT
      LAYER M5 ;
        RECT  78.096 71.196 78.12 71.28 ;
    END
  END s2[66]
  PIN s2[67]
    DIRECTION OUTPUT ;
    USE SIGNAL ;
    PORT
      LAYER M5 ;
        RECT  78.144 71.196 78.168 71.28 ;
    END
  END s2[67]
  PIN s2[68]
    DIRECTION OUTPUT ;
    USE SIGNAL ;
    PORT
      LAYER M5 ;
        RECT  78.192 71.196 78.216 71.28 ;
    END
  END s2[68]
  PIN s2[69]
    DIRECTION OUTPUT ;
    USE SIGNAL ;
    PORT
      LAYER M5 ;
        RECT  78.24 71.196 78.264 71.28 ;
    END
  END s2[69]
  PIN s2[6]
    DIRECTION OUTPUT ;
    USE SIGNAL ;
    PORT
      LAYER M5 ;
        RECT  62.544 71.196 62.568 71.28 ;
    END
  END s2[6]
  PIN s2[70]
    DIRECTION OUTPUT ;
    USE SIGNAL ;
    PORT
      LAYER M5 ;
        RECT  78.288 71.196 78.312 71.28 ;
    END
  END s2[70]
  PIN s2[71]
    DIRECTION OUTPUT ;
    USE SIGNAL ;
    PORT
      LAYER M5 ;
        RECT  78.336 71.196 78.36 71.28 ;
    END
  END s2[71]
  PIN s2[72]
    DIRECTION OUTPUT ;
    USE SIGNAL ;
    PORT
      LAYER M5 ;
        RECT  78.384 71.196 78.408 71.28 ;
    END
  END s2[72]
  PIN s2[73]
    DIRECTION OUTPUT ;
    USE SIGNAL ;
    PORT
      LAYER M5 ;
        RECT  78.432 71.196 78.456 71.28 ;
    END
  END s2[73]
  PIN s2[74]
    DIRECTION OUTPUT ;
    USE SIGNAL ;
    PORT
      LAYER M5 ;
        RECT  78.48 71.196 78.504 71.28 ;
    END
  END s2[74]
  PIN s2[75]
    DIRECTION OUTPUT ;
    USE SIGNAL ;
    PORT
      LAYER M5 ;
        RECT  78.528 71.196 78.552 71.28 ;
    END
  END s2[75]
  PIN s2[76]
    DIRECTION OUTPUT ;
    USE SIGNAL ;
    PORT
      LAYER M5 ;
        RECT  78.576 71.196 78.6 71.28 ;
    END
  END s2[76]
  PIN s2[77]
    DIRECTION OUTPUT ;
    USE SIGNAL ;
    PORT
      LAYER M5 ;
        RECT  78.624 71.196 78.648 71.28 ;
    END
  END s2[77]
  PIN s2[78]
    DIRECTION OUTPUT ;
    USE SIGNAL ;
    PORT
      LAYER M5 ;
        RECT  78.672 71.196 78.696 71.28 ;
    END
  END s2[78]
  PIN s2[79]
    DIRECTION OUTPUT ;
    USE SIGNAL ;
    PORT
      LAYER M5 ;
        RECT  78.72 71.196 78.744 71.28 ;
    END
  END s2[79]
  PIN s2[7]
    DIRECTION OUTPUT ;
    USE SIGNAL ;
    PORT
      LAYER M5 ;
        RECT  62.592 71.196 62.616 71.28 ;
    END
  END s2[7]
  PIN s2[80]
    DIRECTION OUTPUT ;
    USE SIGNAL ;
    PORT
      LAYER M5 ;
        RECT  78.768 71.196 78.792 71.28 ;
    END
  END s2[80]
  PIN s2[81]
    DIRECTION OUTPUT ;
    USE SIGNAL ;
    PORT
      LAYER M5 ;
        RECT  78.816 71.196 78.84 71.28 ;
    END
  END s2[81]
  PIN s2[82]
    DIRECTION OUTPUT ;
    USE SIGNAL ;
    PORT
      LAYER M5 ;
        RECT  78.864 71.196 78.888 71.28 ;
    END
  END s2[82]
  PIN s2[83]
    DIRECTION OUTPUT ;
    USE SIGNAL ;
    PORT
      LAYER M5 ;
        RECT  78.912 71.196 78.936 71.28 ;
    END
  END s2[83]
  PIN s2[84]
    DIRECTION OUTPUT ;
    USE SIGNAL ;
    PORT
      LAYER M5 ;
        RECT  78.96 71.196 78.984 71.28 ;
    END
  END s2[84]
  PIN s2[85]
    DIRECTION OUTPUT ;
    USE SIGNAL ;
    PORT
      LAYER M5 ;
        RECT  79.008 71.196 79.032 71.28 ;
    END
  END s2[85]
  PIN s2[86]
    DIRECTION OUTPUT ;
    USE SIGNAL ;
    PORT
      LAYER M5 ;
        RECT  79.056 71.196 79.08 71.28 ;
    END
  END s2[86]
  PIN s2[87]
    DIRECTION OUTPUT ;
    USE SIGNAL ;
    PORT
      LAYER M5 ;
        RECT  79.104 71.196 79.128 71.28 ;
    END
  END s2[87]
  PIN s2[88]
    DIRECTION OUTPUT ;
    USE SIGNAL ;
    PORT
      LAYER M5 ;
        RECT  79.152 71.196 79.176 71.28 ;
    END
  END s2[88]
  PIN s2[89]
    DIRECTION OUTPUT ;
    USE SIGNAL ;
    PORT
      LAYER M5 ;
        RECT  79.2 71.196 79.224 71.28 ;
    END
  END s2[89]
  PIN s2[8]
    DIRECTION OUTPUT ;
    USE SIGNAL ;
    PORT
      LAYER M5 ;
        RECT  62.64 71.196 62.664 71.28 ;
    END
  END s2[8]
  PIN s2[90]
    DIRECTION OUTPUT ;
    USE SIGNAL ;
    PORT
      LAYER M5 ;
        RECT  79.248 71.196 79.272 71.28 ;
    END
  END s2[90]
  PIN s2[91]
    DIRECTION OUTPUT ;
    USE SIGNAL ;
    PORT
      LAYER M5 ;
        RECT  79.296 71.196 79.32 71.28 ;
    END
  END s2[91]
  PIN s2[92]
    DIRECTION OUTPUT ;
    USE SIGNAL ;
    PORT
      LAYER M5 ;
        RECT  63.6 71.196 63.624 71.28 ;
    END
  END s2[92]
  PIN s2[93]
    DIRECTION OUTPUT ;
    USE SIGNAL ;
    PORT
      LAYER M5 ;
        RECT  63.648 71.196 63.672 71.28 ;
    END
  END s2[93]
  PIN s2[94]
    DIRECTION OUTPUT ;
    USE SIGNAL ;
    PORT
      LAYER M5 ;
        RECT  63.696 71.196 63.72 71.28 ;
    END
  END s2[94]
  PIN s2[95]
    DIRECTION OUTPUT ;
    USE SIGNAL ;
    PORT
      LAYER M5 ;
        RECT  63.744 71.196 63.768 71.28 ;
    END
  END s2[95]
  PIN s2[96]
    DIRECTION OUTPUT ;
    USE SIGNAL ;
    PORT
      LAYER M5 ;
        RECT  63.792 71.196 63.816 71.28 ;
    END
  END s2[96]
  PIN s2[97]
    DIRECTION OUTPUT ;
    USE SIGNAL ;
    PORT
      LAYER M5 ;
        RECT  63.84 71.196 63.864 71.28 ;
    END
  END s2[97]
  PIN s2[98]
    DIRECTION OUTPUT ;
    USE SIGNAL ;
    PORT
      LAYER M5 ;
        RECT  63.888 71.196 63.912 71.28 ;
    END
  END s2[98]
  PIN s2[99]
    DIRECTION OUTPUT ;
    USE SIGNAL ;
    PORT
      LAYER M5 ;
        RECT  63.936 71.196 63.96 71.28 ;
    END
  END s2[99]
  PIN s2[9]
    DIRECTION OUTPUT ;
    USE SIGNAL ;
    PORT
      LAYER M5 ;
        RECT  62.688 71.196 62.712 71.28 ;
    END
  END s2[9]
  PIN s2_v
    DIRECTION OUTPUT ;
    USE SIGNAL ;
    PORT
      LAYER M5 ;
        RECT  82.752 71.196 82.776 71.28 ;
    END
  END s2_v
  PIN VDD
    DIRECTION INOUT ;
    USE POWER ;
    PORT
      LAYER M5 ;
        RECT  126.792 2.151 126.912 69.129 ;
        RECT  121.392 2.151 121.512 69.129 ;
        RECT  115.992 2.151 116.112 69.129 ;
        RECT  110.592 2.151 110.712 69.129 ;
        RECT  105.192 2.151 105.312 69.129 ;
        RECT  99.792 2.151 99.912 69.129 ;
        RECT  94.392 2.151 94.512 69.129 ;
        RECT  88.992 2.151 89.112 69.129 ;
        RECT  83.592 2.151 83.712 69.129 ;
        RECT  78.192 2.151 78.312 69.129 ;
        RECT  72.792 2.151 72.912 69.129 ;
        RECT  67.392 2.151 67.512 69.129 ;
        RECT  61.992 2.151 62.112 69.129 ;
        RECT  56.592 2.151 56.712 69.129 ;
        RECT  51.192 2.151 51.312 69.129 ;
        RECT  45.792 2.151 45.912 69.129 ;
        RECT  40.392 2.151 40.512 69.129 ;
        RECT  34.992 2.151 35.112 69.129 ;
        RECT  29.592 2.151 29.712 69.129 ;
        RECT  24.192 2.151 24.312 69.129 ;
        RECT  18.792 2.151 18.912 69.129 ;
        RECT  13.392 2.151 13.512 69.129 ;
        RECT  7.992 2.151 8.112 69.129 ;
        RECT  2.592 2.151 2.712 69.129 ;
    END
  END VDD
  PIN VSS
    DIRECTION INOUT ;
    USE GROUND ;
    PORT
      LAYER M5 ;
        RECT  126.6 2.137 126.72 69.143 ;
        RECT  121.2 2.137 121.32 69.143 ;
        RECT  115.8 2.137 115.92 69.143 ;
        RECT  110.4 2.137 110.52 69.143 ;
        RECT  105 2.137 105.12 69.143 ;
        RECT  99.6 2.137 99.72 69.143 ;
        RECT  94.2 2.137 94.32 69.143 ;
        RECT  88.8 2.137 88.92 69.143 ;
        RECT  83.4 2.137 83.52 69.143 ;
        RECT  78 2.137 78.12 69.143 ;
        RECT  72.6 2.137 72.72 69.143 ;
        RECT  67.2 2.137 67.32 69.143 ;
        RECT  61.8 2.137 61.92 69.143 ;
        RECT  56.4 2.137 56.52 69.143 ;
        RECT  51 2.137 51.12 69.143 ;
        RECT  45.6 2.137 45.72 69.143 ;
        RECT  40.2 2.137 40.32 69.143 ;
        RECT  34.8 2.137 34.92 69.143 ;
        RECT  29.4 2.137 29.52 69.143 ;
        RECT  24 2.137 24.12 69.143 ;
        RECT  18.6 2.137 18.72 69.143 ;
        RECT  13.2 2.137 13.32 69.143 ;
        RECT  7.8 2.137 7.92 69.143 ;
        RECT  2.4 2.137 2.52 69.143 ;
    END
  END VSS
  # OT_OBS_CLOSED layer=M5 d_um=1.536 added=127
  OBS
    LAYER RVTN ;
     RECT  2.16 2.16 127.44 2.295 ;
     RECT  2.16 2.565 127.44 2.835 ;
     RECT  2.16 3.105 127.44 3.375 ;
     RECT  2.16 3.645 127.44 3.915 ;
     RECT  2.16 4.185 127.44 4.455 ;
     RECT  2.16 4.725 127.44 4.995 ;
     RECT  2.16 5.265 127.44 5.535 ;
     RECT  2.16 5.805 127.44 6.075 ;
     RECT  2.16 6.345 127.44 6.615 ;
     RECT  2.16 6.885 127.44 7.155 ;
     RECT  2.16 7.425 127.44 7.695 ;
     RECT  2.16 7.965 127.44 8.235 ;
     RECT  2.16 8.505 127.44 8.775 ;
     RECT  2.16 9.045 127.44 9.315 ;
     RECT  2.16 9.585 127.44 9.855 ;
     RECT  2.16 10.125 127.44 10.395 ;
     RECT  2.16 10.665 127.44 10.935 ;
     RECT  2.16 11.205 127.44 11.475 ;
     RECT  2.16 11.745 127.44 12.015 ;
     RECT  2.16 12.285 127.44 12.555 ;
     RECT  2.16 12.825 127.44 13.095 ;
     RECT  2.16 13.365 127.44 13.635 ;
     RECT  2.16 13.905 127.44 14.175 ;
     RECT  2.16 14.445 127.44 14.715 ;
     RECT  2.16 14.985 127.44 15.255 ;
     RECT  2.16 15.525 127.44 15.795 ;
     RECT  2.16 16.065 127.44 16.335 ;
     RECT  2.16 16.605 127.44 16.875 ;
     RECT  2.16 17.145 127.44 17.415 ;
     RECT  2.16 17.685 127.44 17.955 ;
     RECT  2.16 18.225 127.44 18.495 ;
     RECT  2.16 18.765 127.44 19.035 ;
     RECT  2.16 19.305 127.44 19.575 ;
     RECT  2.16 19.845 127.44 20.115 ;
     RECT  2.16 20.385 127.44 20.655 ;
     RECT  2.16 20.925 127.44 21.195 ;
     RECT  2.16 21.465 127.44 21.735 ;
     RECT  2.16 22.005 127.44 22.275 ;
     RECT  2.16 22.545 127.44 22.815 ;
     RECT  2.16 23.085 127.44 23.355 ;
     RECT  2.16 23.625 127.44 23.895 ;
     RECT  2.16 24.165 127.44 24.435 ;
     RECT  2.16 24.705 127.44 24.975 ;
     RECT  2.16 25.245 127.44 25.515 ;
     RECT  2.16 25.785 127.44 26.055 ;
     RECT  2.16 26.325 127.44 26.595 ;
     RECT  2.16 26.865 127.44 27.135 ;
     RECT  2.16 27.405 127.44 27.675 ;
     RECT  2.16 27.945 127.44 28.215 ;
     RECT  2.16 28.485 127.44 28.755 ;
     RECT  2.16 29.025 127.44 29.295 ;
     RECT  2.16 29.565 127.44 29.835 ;
     RECT  2.16 30.105 127.44 30.375 ;
     RECT  2.16 30.645 127.44 30.915 ;
     RECT  2.16 31.185 127.44 31.455 ;
     RECT  2.16 31.725 127.44 31.995 ;
     RECT  2.16 32.265 127.44 32.535 ;
     RECT  2.16 32.805 127.44 33.075 ;
     RECT  2.16 33.345 127.44 33.615 ;
     RECT  2.16 33.885 127.44 34.155 ;
     RECT  2.16 34.425 127.44 34.695 ;
     RECT  2.16 34.965 127.44 35.235 ;
     RECT  2.16 35.505 127.44 35.775 ;
     RECT  2.16 36.045 127.44 36.315 ;
     RECT  2.16 36.585 127.44 36.855 ;
     RECT  2.16 37.125 127.44 37.395 ;
     RECT  2.16 37.665 127.44 37.935 ;
     RECT  2.16 38.205 127.44 38.475 ;
     RECT  2.16 38.745 127.44 39.015 ;
     RECT  2.16 39.285 127.44 39.555 ;
     RECT  2.16 39.825 127.44 40.095 ;
     RECT  2.16 40.365 127.44 40.635 ;
     RECT  2.16 40.905 127.44 41.175 ;
     RECT  2.16 41.445 127.44 41.715 ;
     RECT  2.16 41.985 127.44 42.255 ;
     RECT  2.16 42.525 127.44 42.795 ;
     RECT  2.16 43.065 127.44 43.335 ;
     RECT  2.16 43.605 127.44 43.875 ;
     RECT  2.16 44.145 127.44 44.415 ;
     RECT  2.16 44.685 127.44 44.955 ;
     RECT  2.16 45.225 127.44 45.495 ;
     RECT  2.16 45.765 127.44 46.035 ;
     RECT  2.16 46.305 127.44 46.575 ;
     RECT  2.16 46.845 127.44 47.115 ;
     RECT  2.16 47.385 127.44 47.655 ;
     RECT  2.16 47.925 127.44 48.195 ;
     RECT  2.16 48.465 127.44 48.735 ;
     RECT  2.16 49.005 127.44 49.275 ;
     RECT  2.16 49.545 127.44 49.815 ;
     RECT  2.16 50.085 127.44 50.355 ;
     RECT  2.16 50.625 127.44 50.895 ;
     RECT  2.16 51.165 127.44 51.435 ;
     RECT  2.16 51.705 127.44 51.975 ;
     RECT  2.16 52.245 127.44 52.515 ;
     RECT  2.16 52.785 127.44 53.055 ;
     RECT  2.16 53.325 127.44 53.595 ;
     RECT  2.16 53.865 127.44 54.135 ;
     RECT  2.16 54.405 127.44 54.675 ;
     RECT  2.16 54.945 127.44 55.215 ;
     RECT  2.16 55.485 127.44 55.755 ;
     RECT  2.16 56.025 127.44 56.295 ;
     RECT  2.16 56.565 127.44 56.835 ;
     RECT  2.16 57.105 127.44 57.375 ;
     RECT  2.16 57.645 127.44 57.915 ;
     RECT  2.16 58.185 127.44 58.455 ;
     RECT  2.16 58.725 127.44 58.995 ;
     RECT  2.16 59.265 127.44 59.535 ;
     RECT  2.16 59.805 127.44 60.075 ;
     RECT  2.16 60.345 127.44 60.615 ;
     RECT  2.16 60.885 127.44 61.155 ;
     RECT  2.16 61.425 127.44 61.695 ;
     RECT  2.16 61.965 127.44 62.235 ;
     RECT  2.16 62.505 127.44 62.775 ;
     RECT  2.16 63.045 127.44 63.315 ;
     RECT  2.16 63.585 127.44 63.855 ;
     RECT  2.16 64.125 127.44 64.395 ;
     RECT  2.16 64.665 127.44 64.935 ;
     RECT  2.16 65.205 127.44 65.475 ;
     RECT  2.16 65.745 127.44 66.015 ;
     RECT  2.16 66.285 127.44 66.555 ;
     RECT  2.16 66.825 127.44 67.095 ;
     RECT  2.16 67.365 127.44 67.635 ;
     RECT  2.16 67.905 127.44 68.175 ;
     RECT  2.16 68.445 127.44 68.715 ;
     RECT  2.16 68.985 127.44 69.12 ;
    LAYER RVTP ;
     RECT  2.16 2.295 127.44 2.565 ;
     RECT  2.16 2.835 127.44 3.105 ;
     RECT  2.16 3.375 127.44 3.645 ;
     RECT  2.16 3.915 127.44 4.185 ;
     RECT  2.16 4.455 127.44 4.725 ;
     RECT  2.16 4.995 127.44 5.265 ;
     RECT  2.16 5.535 127.44 5.805 ;
     RECT  2.16 6.075 127.44 6.345 ;
     RECT  2.16 6.615 127.44 6.885 ;
     RECT  2.16 7.155 127.44 7.425 ;
     RECT  2.16 7.695 127.44 7.965 ;
     RECT  2.16 8.235 127.44 8.505 ;
     RECT  2.16 8.775 127.44 9.045 ;
     RECT  2.16 9.315 127.44 9.585 ;
     RECT  2.16 9.855 127.44 10.125 ;
     RECT  2.16 10.395 127.44 10.665 ;
     RECT  2.16 10.935 127.44 11.205 ;
     RECT  2.16 11.475 127.44 11.745 ;
     RECT  2.16 12.015 127.44 12.285 ;
     RECT  2.16 12.555 127.44 12.825 ;
     RECT  2.16 13.095 127.44 13.365 ;
     RECT  2.16 13.635 127.44 13.905 ;
     RECT  2.16 14.175 127.44 14.445 ;
     RECT  2.16 14.715 127.44 14.985 ;
     RECT  2.16 15.255 127.44 15.525 ;
     RECT  2.16 15.795 127.44 16.065 ;
     RECT  2.16 16.335 127.44 16.605 ;
     RECT  2.16 16.875 127.44 17.145 ;
     RECT  2.16 17.415 127.44 17.685 ;
     RECT  2.16 17.955 127.44 18.225 ;
     RECT  2.16 18.495 127.44 18.765 ;
     RECT  2.16 19.035 127.44 19.305 ;
     RECT  2.16 19.575 127.44 19.845 ;
     RECT  2.16 20.115 127.44 20.385 ;
     RECT  2.16 20.655 127.44 20.925 ;
     RECT  2.16 21.195 127.44 21.465 ;
     RECT  2.16 21.735 127.44 22.005 ;
     RECT  2.16 22.275 127.44 22.545 ;
     RECT  2.16 22.815 127.44 23.085 ;
     RECT  2.16 23.355 127.44 23.625 ;
     RECT  2.16 23.895 127.44 24.165 ;
     RECT  2.16 24.435 127.44 24.705 ;
     RECT  2.16 24.975 127.44 25.245 ;
     RECT  2.16 25.515 127.44 25.785 ;
     RECT  2.16 26.055 127.44 26.325 ;
     RECT  2.16 26.595 127.44 26.865 ;
     RECT  2.16 27.135 127.44 27.405 ;
     RECT  2.16 27.675 127.44 27.945 ;
     RECT  2.16 28.215 127.44 28.485 ;
     RECT  2.16 28.755 127.44 29.025 ;
     RECT  2.16 29.295 127.44 29.565 ;
     RECT  2.16 29.835 127.44 30.105 ;
     RECT  2.16 30.375 127.44 30.645 ;
     RECT  2.16 30.915 127.44 31.185 ;
     RECT  2.16 31.455 127.44 31.725 ;
     RECT  2.16 31.995 127.44 32.265 ;
     RECT  2.16 32.535 127.44 32.805 ;
     RECT  2.16 33.075 127.44 33.345 ;
     RECT  2.16 33.615 127.44 33.885 ;
     RECT  2.16 34.155 127.44 34.425 ;
     RECT  2.16 34.695 127.44 34.965 ;
     RECT  2.16 35.235 127.44 35.505 ;
     RECT  2.16 35.775 127.44 36.045 ;
     RECT  2.16 36.315 127.44 36.585 ;
     RECT  2.16 36.855 127.44 37.125 ;
     RECT  2.16 37.395 127.44 37.665 ;
     RECT  2.16 37.935 127.44 38.205 ;
     RECT  2.16 38.475 127.44 38.745 ;
     RECT  2.16 39.015 127.44 39.285 ;
     RECT  2.16 39.555 127.44 39.825 ;
     RECT  2.16 40.095 127.44 40.365 ;
     RECT  2.16 40.635 127.44 40.905 ;
     RECT  2.16 41.175 127.44 41.445 ;
     RECT  2.16 41.715 127.44 41.985 ;
     RECT  2.16 42.255 127.44 42.525 ;
     RECT  2.16 42.795 127.44 43.065 ;
     RECT  2.16 43.335 127.44 43.605 ;
     RECT  2.16 43.875 127.44 44.145 ;
     RECT  2.16 44.415 127.44 44.685 ;
     RECT  2.16 44.955 127.44 45.225 ;
     RECT  2.16 45.495 127.44 45.765 ;
     RECT  2.16 46.035 127.44 46.305 ;
     RECT  2.16 46.575 127.44 46.845 ;
     RECT  2.16 47.115 127.44 47.385 ;
     RECT  2.16 47.655 127.44 47.925 ;
     RECT  2.16 48.195 127.44 48.465 ;
     RECT  2.16 48.735 127.44 49.005 ;
     RECT  2.16 49.275 127.44 49.545 ;
     RECT  2.16 49.815 127.44 50.085 ;
     RECT  2.16 50.355 127.44 50.625 ;
     RECT  2.16 50.895 127.44 51.165 ;
     RECT  2.16 51.435 127.44 51.705 ;
     RECT  2.16 51.975 127.44 52.245 ;
     RECT  2.16 52.515 127.44 52.785 ;
     RECT  2.16 53.055 127.44 53.325 ;
     RECT  2.16 53.595 127.44 53.865 ;
     RECT  2.16 54.135 127.44 54.405 ;
     RECT  2.16 54.675 127.44 54.945 ;
     RECT  2.16 55.215 127.44 55.485 ;
     RECT  2.16 55.755 127.44 56.025 ;
     RECT  2.16 56.295 127.44 56.565 ;
     RECT  2.16 56.835 127.44 57.105 ;
     RECT  2.16 57.375 127.44 57.645 ;
     RECT  2.16 57.915 127.44 58.185 ;
     RECT  2.16 58.455 127.44 58.725 ;
     RECT  2.16 58.995 127.44 59.265 ;
     RECT  2.16 59.535 127.44 59.805 ;
     RECT  2.16 60.075 127.44 60.345 ;
     RECT  2.16 60.615 127.44 60.885 ;
     RECT  2.16 61.155 127.44 61.425 ;
     RECT  2.16 61.695 127.44 61.965 ;
     RECT  2.16 62.235 127.44 62.505 ;
     RECT  2.16 62.775 127.44 63.045 ;
     RECT  2.16 63.315 127.44 63.585 ;
     RECT  2.16 63.855 127.44 64.125 ;
     RECT  2.16 64.395 127.44 64.665 ;
     RECT  2.16 64.935 127.44 65.205 ;
     RECT  2.16 65.475 127.44 65.745 ;
     RECT  2.16 66.015 127.44 66.285 ;
     RECT  2.16 66.555 127.44 66.825 ;
     RECT  2.16 67.095 127.44 67.365 ;
     RECT  2.16 67.635 127.44 67.905 ;
     RECT  2.16 68.175 127.44 68.445 ;
     RECT  2.16 68.715 127.44 68.985 ;
    LAYER M1 ;
     RECT  2.16 2.151 127.44 69.129 ;
    LAYER M2 ;
     RECT  2.16 2.151 45.031 69.129 ;
     RECT  45.031 2.106 46.211 69.129 ;
     RECT  46.211 2.151 51.727 69.129 ;
     RECT  51.727 2.106 52.223 69.129 ;
     RECT  52.223 2.151 63.643 69.129 ;
     RECT  63.643 2.151 63.743 69.669 ;
     RECT  64.183 70.65 64.391 70.668 ;
     RECT  65.875 70.578 65.983 70.596 ;
     RECT  65.983 70.578 66.487 70.668 ;
     RECT  66.487 70.542 66.551 70.668 ;
     RECT  66.551 70.542 66.659 70.56 ;
     RECT  69.367 1.152 69.439 1.17 ;
     RECT  69.439 1.152 69.467 1.242 ;
     RECT  69.467 1.224 69.539 1.242 ;
     RECT  71.347 1.152 71.447 1.17 ;
     RECT  63.743 2.151 72.211 69.129 ;
     RECT  72.211 2.106 72.959 69.129 ;
     RECT  72.959 2.151 74.911 69.129 ;
     RECT  74.911 2.106 75.587 69.129 ;
     RECT  77.683 70.65 77.783 70.668 ;
     RECT  75.587 2.151 78.655 69.129 ;
     RECT  78.655 2.151 79.223 69.318 ;
     RECT  78.043 71.226 81.023 71.244 ;
     RECT  82.219 70.65 82.571 70.668 ;
     RECT  79.223 2.151 83.011 69.129 ;
     RECT  83.011 2.151 83.147 69.588 ;
     RECT  84.523 70.65 84.623 70.668 ;
     RECT  83.147 2.151 127.44 69.129 ;
    LAYER M3 ;
     RECT  52.272 0.091 52.29 0.139 ;
     RECT  53.712 0.139 53.73 0.187 ;
     RECT  55.008 0.139 55.026 0.187 ;
     RECT  59.724 0.139 59.742 0.187 ;
     RECT  69.516 0.139 69.534 0.187 ;
     RECT  70.308 0.139 70.47 0.187 ;
     RECT  71.388 0.139 72.054 0.187 ;
     RECT  45.864 0.139 47.142 0.235 ;
     RECT  48.096 0.139 48.294 0.235 ;
     RECT  56.844 0.139 56.862 0.235 ;
     RECT  69.516 0.187 72.054 0.235 ;
     RECT  58.5 0.139 58.518 0.427 ;
     RECT  53.208 0.187 53.73 0.475 ;
     RECT  69.516 0.235 72.198 0.475 ;
     RECT  45.432 0.235 47.142 0.523 ;
     RECT  48.096 0.235 48.51 0.523 ;
     RECT  50.004 0.475 50.022 0.523 ;
     RECT  57.996 0.427 58.518 0.523 ;
     RECT  59.508 0.187 59.742 0.523 ;
     RECT  60.948 0.139 61.542 0.523 ;
     RECT  44.208 0.523 44.226 0.571 ;
     RECT  45.432 0.523 48.51 0.571 ;
     RECT  56.844 0.235 56.934 0.571 ;
     RECT  57.996 0.523 58.59 0.571 ;
     RECT  59.4 0.523 59.778 0.571 ;
     RECT  60.516 0.523 61.542 0.571 ;
     RECT  56.844 0.571 59.778 0.619 ;
     RECT  60.516 0.571 61.578 0.619 ;
     RECT  56.844 0.619 61.578 0.667 ;
     RECT  45.324 0.571 48.51 0.701 ;
     RECT  29.232 0.523 29.25 1.003 ;
     RECT  29.232 1.003 29.394 1.051 ;
     RECT  29.16 1.051 29.394 1.099 ;
     RECT  43.92 0.571 44.226 1.099 ;
     RECT  45.324 0.701 45.558 1.099 ;
     RECT  50.004 0.523 50.886 1.099 ;
     RECT  75.564 0.139 76.41 1.147 ;
     RECT  49.86 1.099 50.886 1.675 ;
     RECT  29.16 1.099 29.79 1.723 ;
     RECT  30.96 1.099 30.978 1.723 ;
     RECT  43.92 1.099 45.558 1.723 ;
     RECT  46.296 0.701 48.51 1.723 ;
     RECT  49.86 1.675 50.922 1.723 ;
     RECT  52.092 0.139 52.29 1.723 ;
     RECT  53.208 0.475 53.982 1.723 ;
     RECT  54.936 0.187 55.026 1.723 ;
     RECT  56.844 0.667 61.65 1.723 ;
     RECT  69.012 0.475 72.198 1.723 ;
     RECT  75.528 1.147 76.41 1.723 ;
     RECT  29.16 1.723 29.826 1.771 ;
     RECT  43.668 1.723 48.51 1.771 ;
     RECT  53.208 1.723 55.026 1.771 ;
     RECT  75.528 1.723 77.49 1.771 ;
     RECT  30.96 1.723 31.482 1.819 ;
     RECT  53.208 1.771 55.278 1.819 ;
     RECT  62.82 1.723 62.838 1.819 ;
     RECT  29.16 1.771 29.97 1.867 ;
     RECT  30.816 1.819 31.914 1.867 ;
     RECT  69.012 1.723 72.522 2.101 ;
     RECT  75.348 1.771 77.49 2.101 ;
     RECT  56.304 1.723 61.794 2.143 ;
     RECT  74.916 2.101 77.49 2.143 ;
     RECT  29.16 1.867 31.914 2.255 ;
     RECT  43.38 1.771 48.51 2.255 ;
     RECT  74.916 2.143 78.105 2.255 ;
     RECT  43.668 2.255 48.51 2.263 ;
     RECT  56.304 2.143 61.905 2.263 ;
     RECT  62.82 1.819 62.874 2.263 ;
     RECT  43.668 2.263 48.582 2.299 ;
     RECT  32.652 1.723 32.67 2.371 ;
     RECT  34.815 2.143 34.905 2.371 ;
     RECT  43.668 2.299 48.654 2.371 ;
     RECT  49.86 1.723 52.29 2.371 ;
     RECT  53.1 1.819 55.278 2.371 ;
     RECT  56.304 2.263 62.874 2.371 ;
     RECT  69.012 2.101 72.954 2.371 ;
     RECT  2.415 2.143 2.505 2.413 ;
     RECT  7.815 2.143 7.905 2.413 ;
     RECT  13.215 2.143 13.305 2.413 ;
     RECT  18.615 2.143 18.705 2.413 ;
     RECT  24.015 2.143 24.105 2.413 ;
     RECT  34.236 2.371 34.905 2.413 ;
     RECT  40.215 2.143 40.305 2.413 ;
     RECT  67.215 2.143 67.305 2.413 ;
     RECT  74.988 2.255 78.105 2.413 ;
     RECT  83.415 2.143 83.505 2.413 ;
     RECT  88.815 2.143 88.905 2.413 ;
     RECT  94.215 2.143 94.305 2.413 ;
     RECT  99.615 2.143 99.705 2.413 ;
     RECT  105.015 2.143 105.105 2.413 ;
     RECT  110.415 2.143 110.505 2.413 ;
     RECT  115.815 2.143 115.905 2.413 ;
     RECT  121.215 2.143 121.305 2.413 ;
     RECT  126.615 2.143 126.705 2.413 ;
     RECT  43.668 2.371 49.05 2.525 ;
     RECT  30.816 2.255 31.914 2.641 ;
     RECT  32.652 2.371 32.742 2.641 ;
     RECT  43.704 2.525 49.05 2.641 ;
     RECT  49.824 2.371 55.314 2.641 ;
     RECT  56.304 2.371 62.91 2.641 ;
     RECT  69.012 2.371 73.242 2.803 ;
     RECT  29.16 2.255 30.078 2.911 ;
     RECT  43.704 2.641 63.162 2.911 ;
     RECT  28.98 2.911 30.078 3.001 ;
     RECT  30.816 2.641 32.742 3.001 ;
     RECT  43.704 2.911 63.198 3.181 ;
     RECT  74.988 2.413 78.297 3.181 ;
     RECT  43.704 3.181 63.702 3.403 ;
     RECT  69.012 2.803 73.314 3.403 ;
     RECT  43.56 3.403 63.702 3.451 ;
     RECT  43.488 3.451 63.702 3.499 ;
     RECT  43.344 3.499 63.702 3.605 ;
     RECT  74.988 3.181 78.462 3.749 ;
     RECT  43.56 3.605 63.702 3.875 ;
     RECT  68.976 3.403 73.314 3.875 ;
     RECT  69.012 3.875 73.314 3.883 ;
     RECT  28.98 3.001 32.742 4.289 ;
     RECT  69.012 3.883 73.422 4.649 ;
     RECT  69.012 4.649 73.386 4.757 ;
     RECT  75.06 3.749 78.462 4.801 ;
     RECT  69.048 4.757 73.386 5.729 ;
     RECT  43.668 3.875 63.702 5.881 ;
     RECT  67.215 2.413 67.497 5.881 ;
     RECT  74.124 5.881 74.142 6.079 ;
     RECT  74.988 4.801 78.462 6.079 ;
     RECT  43.668 5.881 63.882 6.115 ;
     RECT  43.668 6.115 64.026 6.151 ;
     RECT  29.415 4.289 32.742 6.421 ;
     RECT  29.415 6.421 32.922 6.691 ;
     RECT  64.908 6.079 64.926 6.691 ;
     RECT  69.048 5.729 73.314 6.691 ;
     RECT  74.124 6.079 78.462 6.691 ;
     RECT  29.415 6.691 33.246 6.781 ;
     RECT  34.236 2.413 35.097 6.781 ;
     RECT  43.668 6.151 64.17 6.781 ;
     RECT  64.908 6.691 65.646 6.781 ;
     RECT  43.668 6.781 65.646 6.809 ;
     RECT  29.415 6.781 35.097 6.845 ;
     RECT  69.048 6.691 78.462 6.853 ;
     RECT  67.215 5.881 68.022 6.961 ;
     RECT  69.048 6.853 78.606 6.961 ;
     RECT  34.236 6.845 35.097 7.087 ;
     RECT  65.736 7.195 65.754 7.231 ;
     RECT  34.236 7.087 35.37 7.393 ;
     RECT  34.236 7.393 36.09 7.735 ;
     RECT  29.415 6.845 33.462 7.771 ;
     RECT  34.236 7.735 36.594 7.771 ;
     RECT  29.415 7.771 36.594 7.889 ;
     RECT  43.668 6.809 64.926 8.401 ;
     RECT  36.468 7.889 36.594 8.539 ;
     RECT  43.452 8.401 64.926 8.581 ;
     RECT  30.78 7.889 35.37 8.671 ;
     RECT  40.215 2.413 40.497 8.683 ;
     RECT  36.468 8.539 37.062 8.699 ;
     RECT  30.78 8.671 35.514 8.717 ;
     RECT  30.78 8.717 35.37 8.735 ;
     RECT  42.768 8.581 64.926 8.735 ;
     RECT  40.104 8.683 40.497 8.813 ;
     RECT  42.804 8.735 64.926 8.851 ;
     RECT  65.736 7.231 65.826 8.851 ;
     RECT  36.468 8.699 36.486 8.861 ;
     RECT  42.804 8.851 65.826 8.879 ;
     RECT  43.668 8.879 65.826 8.941 ;
     RECT  67.215 6.961 78.606 8.941 ;
     RECT  38.844 8.635 38.862 8.969 ;
     RECT  31.176 8.735 35.37 9.005 ;
     RECT  31.248 9.005 35.37 9.239 ;
     RECT  43.668 8.941 66.078 9.391 ;
     RECT  43.668 9.391 66.438 9.581 ;
     RECT  42.804 8.879 42.822 9.589 ;
     RECT  31.32 9.239 35.37 9.787 ;
     RECT  41.76 9.739 41.778 9.787 ;
     RECT  41.436 9.787 41.778 9.824 ;
     RECT  31.32 9.787 35.802 9.931 ;
     RECT  38.736 9.859 38.754 10.021 ;
     RECT  31.32 9.931 35.874 10.049 ;
     RECT  43.668 9.581 66.078 10.075 ;
     RECT  43.596 10.075 66.078 10.121 ;
     RECT  42.768 9.589 42.822 10.129 ;
     RECT  38.736 10.021 38.826 10.157 ;
     RECT  67.215 8.941 79.182 10.157 ;
     RECT  31.356 10.049 35.874 10.201 ;
     RECT  36.936 10.021 36.954 10.201 ;
     RECT  38.808 10.157 38.826 10.229 ;
     RECT  42.768 10.129 42.858 10.229 ;
     RECT  41.76 9.824 41.778 10.253 ;
     RECT  31.356 10.201 36.954 10.391 ;
     RECT  31.356 10.391 36.234 10.589 ;
     RECT  67.215 10.157 79.038 10.859 ;
     RECT  31.356 10.589 35.097 10.877 ;
     RECT  31.932 10.877 35.097 11.129 ;
     RECT  37.152 10.435 37.17 11.129 ;
     RECT  43.668 10.121 66.078 11.129 ;
     RECT  32.4 11.129 35.097 11.165 ;
     RECT  45.396 11.129 66.078 11.173 ;
     RECT  34.488 11.165 35.097 11.237 ;
     RECT  43.668 11.129 44.55 11.273 ;
     RECT  35.856 10.589 36.234 11.281 ;
     RECT  45.396 11.173 66.114 11.371 ;
     RECT  32.4 11.165 33.75 11.399 ;
     RECT  43.668 11.273 44.442 11.399 ;
     RECT  45.396 11.371 66.294 11.551 ;
     RECT  32.4 11.399 33.714 11.669 ;
     RECT  43.668 11.399 43.722 11.669 ;
     RECT  32.4 11.669 32.634 11.705 ;
     RECT  45.396 11.551 66.402 11.749 ;
     RECT  67.215 10.859 78.93 11.749 ;
     RECT  32.4 11.705 32.418 11.777 ;
     RECT  33.696 11.669 33.714 11.813 ;
     RECT  43.668 11.669 43.686 11.849 ;
     RECT  45.396 11.749 78.93 11.939 ;
     RECT  47.736 11.939 78.93 11.975 ;
     RECT  45.396 11.939 46.926 12.245 ;
     RECT  45.396 12.245 46.566 12.389 ;
     RECT  45.396 12.389 46.314 12.479 ;
     RECT  45.396 12.479 46.206 12.623 ;
     RECT  47.736 11.975 68.814 12.721 ;
     RECT  47.448 12.721 68.814 12.749 ;
     RECT  47.448 12.749 68.67 12.797 ;
     RECT  47.7 12.797 68.67 13.517 ;
     RECT  48.024 13.517 68.67 13.618 ;
     RECT  48.024 13.618 51.714 13.829 ;
     RECT  45.396 12.623 45.897 14.071 ;
     RECT  48.024 13.829 51.606 14.135 ;
     RECT  45.288 14.071 45.897 14.189 ;
     RECT  46.98 14.155 46.998 14.251 ;
     RECT  52.488 13.618 68.67 14.405 ;
     RECT  52.488 14.405 68.634 14.485 ;
     RECT  46.692 14.251 46.998 14.639 ;
     RECT  48.132 14.135 51.606 14.719 ;
     RECT  52.344 14.485 68.634 14.719 ;
     RECT  48.132 14.719 68.634 14.819 ;
     RECT  48.132 14.819 51.642 14.909 ;
     RECT  52.596 14.819 68.634 14.909 ;
     RECT  48.456 14.909 51.642 15.101 ;
     RECT  46.692 14.639 46.962 15.151 ;
     RECT  46.62 15.151 46.962 15.179 ;
     RECT  46.62 15.179 46.638 15.197 ;
     RECT  48.744 15.101 51.642 15.485 ;
     RECT  48.78 15.485 51.642 15.565 ;
     RECT  52.668 14.909 68.634 15.691 ;
     RECT  48.78 15.565 51.786 15.719 ;
     RECT  52.524 15.691 68.634 16.295 ;
     RECT  48.78 15.719 51.57 16.501 ;
     RECT  52.74 16.295 68.634 16.645 ;
     RECT  69.768 11.975 78.93 16.645 ;
     RECT  48.78 16.501 51.894 16.799 ;
     RECT  49.104 16.799 51.894 17.581 ;
     RECT  52.74 16.645 78.93 17.581 ;
     RECT  80.64 16.411 80.658 17.923 ;
     RECT  49.104 17.581 78.93 18.535 ;
     RECT  79.956 17.923 80.658 18.535 ;
     RECT  49.104 18.535 80.658 23.315 ;
     RECT  49.104 23.315 52.038 24.935 ;
     RECT  53.172 23.315 80.658 25.475 ;
     RECT  49.716 24.935 52.038 32.801 ;
     RECT  53.172 25.475 54.522 33.809 ;
     RECT  53.172 33.809 54.414 34.799 ;
     RECT  49.716 32.801 51.57 37.319 ;
     RECT  49.752 37.319 51.57 37.471 ;
     RECT  53.172 34.799 54.198 37.471 ;
     RECT  55.44 25.475 80.658 37.471 ;
     RECT  53.172 37.471 80.658 37.589 ;
     RECT  54.18 37.589 80.658 37.859 ;
     RECT  49.752 37.471 51.642 38.011 ;
     RECT  49.752 38.011 51.93 38.129 ;
     RECT  50.364 38.129 51.642 38.669 ;
     RECT  53.172 37.589 53.334 38.939 ;
     RECT  54.612 37.859 80.658 38.939 ;
     RECT  50.904 38.669 51.642 38.975 ;
     RECT  50.94 38.975 51.642 39.047 ;
     RECT  50.976 39.047 51.642 39.209 ;
     RECT  54.72 38.939 80.658 39.479 ;
     RECT  35.856 11.281 36.306 39.659 ;
     RECT  54.72 39.479 54.738 39.659 ;
     RECT  51.015 39.209 51.642 39.929 ;
     RECT  55.62 39.479 80.658 40.171 ;
     RECT  81.576 39.631 81.594 40.171 ;
     RECT  55.62 40.171 81.594 47.893 ;
     RECT  55.62 47.893 81.918 47.921 ;
     RECT  55.62 47.921 80.406 49.003 ;
     RECT  81.252 47.921 81.918 49.351 ;
     RECT  55.548 49.003 80.406 49.441 ;
     RECT  81.252 49.351 82.134 49.441 ;
     RECT  55.548 49.441 82.134 49.469 ;
     RECT  55.548 49.469 55.566 49.505 ;
     RECT  56.415 49.469 82.134 51.511 ;
     RECT  56.415 51.511 82.17 51.673 ;
     RECT  56.415 51.673 82.35 51.745 ;
     RECT  56.415 51.745 82.422 51.781 ;
     RECT  83.415 2.413 83.697 51.781 ;
     RECT  56.415 51.781 83.697 51.907 ;
     RECT  56.415 51.907 83.754 51.943 ;
     RECT  56.415 51.943 83.898 52.051 ;
     RECT  56.415 52.051 83.934 52.141 ;
     RECT  56.415 52.141 83.97 52.177 ;
     RECT  56.415 52.177 84.402 52.979 ;
     RECT  57.528 52.979 84.402 53.131 ;
     RECT  85.212 52.861 85.23 53.131 ;
     RECT  57.528 53.131 85.23 53.221 ;
     RECT  57.528 53.221 85.266 53.365 ;
     RECT  57.528 53.365 85.482 53.401 ;
     RECT  57.528 53.401 85.806 53.635 ;
     RECT  57.528 53.635 85.95 53.897 ;
     RECT  57.708 53.897 85.95 54.509 ;
     RECT  57.816 54.509 85.95 55.147 ;
     RECT  57.816 55.147 86.094 56.255 ;
     RECT  57.816 56.255 85.95 56.561 ;
     RECT  57.816 56.561 85.518 56.597 ;
     RECT  57.816 56.597 85.482 56.831 ;
     RECT  57.816 56.831 85.41 57.271 ;
     RECT  57.744 57.271 85.41 57.811 ;
     RECT  57.744 57.811 85.662 58.109 ;
     RECT  45.396 14.189 45.897 58.123 ;
     RECT  57.744 58.109 85.374 58.145 ;
     RECT  45.252 58.123 45.897 58.351 ;
     RECT  46.656 58.123 46.674 58.351 ;
     RECT  45.252 58.351 46.674 58.495 ;
     RECT  45.252 58.495 46.818 58.531 ;
     RECT  47.988 58.495 48.006 58.531 ;
     RECT  45.252 58.531 48.114 58.649 ;
     RECT  45.576 58.649 46.602 58.721 ;
     RECT  47.412 58.649 48.114 58.765 ;
     RECT  45.615 58.721 46.602 58.919 ;
     RECT  45.615 58.919 46.53 58.955 ;
     RECT  57.816 58.145 85.374 58.991 ;
     RECT  51.015 39.929 51.57 59.027 ;
     RECT  47.412 58.765 48.69 59.099 ;
     RECT  47.952 59.099 48.69 59.189 ;
     RECT  48.06 59.189 48.69 59.225 ;
     RECT  48.06 59.225 48.51 59.261 ;
     RECT  59.544 58.991 85.374 59.297 ;
     RECT  48.06 59.261 48.222 59.459 ;
     RECT  48.06 59.459 48.078 59.495 ;
     RECT  49.644 59.233 49.662 59.495 ;
     RECT  57.816 58.991 58.734 59.639 ;
     RECT  36.288 39.659 36.306 60.143 ;
     RECT  57.816 59.639 57.834 60.719 ;
     RECT  53.316 38.939 53.334 61.727 ;
     RECT  59.976 59.297 85.374 61.997 ;
     RECT  58.716 61.699 58.734 62.069 ;
     RECT  60.264 61.997 85.374 62.581 ;
     RECT  86.22 62.155 86.238 62.581 ;
     RECT  60.264 62.581 86.238 62.635 ;
     RECT  60.264 62.635 86.526 62.699 ;
     RECT  60.264 62.699 86.058 63.041 ;
     RECT  60.264 63.041 85.374 64.291 ;
     RECT  60.264 64.291 85.482 64.939 ;
     RECT  60.264 64.939 85.626 65.281 ;
     RECT  60.264 65.281 85.806 65.371 ;
     RECT  60.264 65.371 86.202 65.443 ;
     RECT  60.12 65.443 86.202 67.441 ;
     RECT  60.12 67.441 86.598 67.981 ;
     RECT  59.868 67.981 86.598 68.449 ;
     RECT  59.364 68.449 86.67 68.521 ;
     RECT  2.415 2.413 2.697 68.867 ;
     RECT  7.815 2.413 8.097 68.867 ;
     RECT  13.215 2.413 13.497 68.867 ;
     RECT  18.615 2.413 18.897 68.867 ;
     RECT  24.015 2.413 24.297 68.867 ;
     RECT  29.415 7.889 29.697 68.867 ;
     RECT  34.815 11.237 35.097 68.867 ;
     RECT  40.215 8.813 40.497 68.867 ;
     RECT  45.615 58.955 45.897 68.867 ;
     RECT  51.015 59.027 51.297 68.867 ;
     RECT  56.415 52.979 56.697 68.867 ;
     RECT  88.815 2.413 89.097 68.867 ;
     RECT  94.215 2.413 94.497 68.867 ;
     RECT  99.615 2.413 99.897 68.867 ;
     RECT  105.015 2.413 105.297 68.867 ;
     RECT  110.415 2.413 110.697 68.867 ;
     RECT  115.815 2.413 116.097 68.867 ;
     RECT  121.215 2.413 121.497 68.867 ;
     RECT  126.615 2.413 126.897 68.867 ;
     RECT  59.364 68.521 86.706 68.945 ;
     RECT  59.724 68.945 67.374 68.957 ;
     RECT  59.976 68.957 67.374 68.981 ;
     RECT  68.976 68.945 86.706 69.005 ;
     RECT  59.976 68.981 67.305 69.089 ;
     RECT  2.415 68.867 2.505 69.137 ;
     RECT  7.815 68.867 7.905 69.137 ;
     RECT  13.215 68.867 13.305 69.137 ;
     RECT  18.615 68.867 18.705 69.137 ;
     RECT  24.015 68.867 24.105 69.137 ;
     RECT  29.415 68.867 29.505 69.137 ;
     RECT  34.815 68.867 34.905 69.137 ;
     RECT  40.215 68.867 40.305 69.137 ;
     RECT  45.615 68.867 45.705 69.137 ;
     RECT  51.015 68.867 51.105 69.137 ;
     RECT  56.415 68.867 56.505 69.137 ;
     RECT  61.815 69.089 67.305 69.137 ;
     RECT  88.815 68.867 88.905 69.137 ;
     RECT  94.215 68.867 94.305 69.137 ;
     RECT  99.615 68.867 99.705 69.137 ;
     RECT  105.015 68.867 105.105 69.137 ;
     RECT  110.415 68.867 110.505 69.137 ;
     RECT  115.815 68.867 115.905 69.137 ;
     RECT  121.215 68.867 121.305 69.137 ;
     RECT  126.615 68.867 126.705 69.137 ;
     RECT  62.136 69.137 66.654 69.197 ;
     RECT  62.136 69.197 66.582 69.293 ;
     RECT  62.136 69.293 66.546 69.533 ;
     RECT  62.136 69.533 66.51 69.581 ;
     RECT  69.408 69.005 86.706 70.157 ;
     RECT  69.408 70.157 84.906 70.301 ;
     RECT  62.172 69.581 66.51 70.537 ;
     RECT  70.128 70.301 84.906 70.685 ;
     RECT  59.976 69.089 60.966 70.733 ;
     RECT  62.172 70.537 66.654 70.733 ;
     RECT  70.128 70.685 84.546 70.733 ;
     RECT  59.976 70.733 59.994 70.781 ;
     RECT  62.172 70.733 62.874 70.781 ;
     RECT  70.236 70.733 75.618 70.781 ;
     RECT  76.392 70.733 84.546 70.781 ;
     RECT  60.912 70.733 60.966 70.829 ;
     RECT  70.956 70.781 75.618 70.829 ;
     RECT  77.076 70.781 81.882 70.829 ;
     RECT  62.172 70.781 62.658 70.877 ;
     RECT  85.788 70.157 86.706 70.877 ;
     RECT  60.948 70.829 60.966 70.925 ;
     RECT  62.172 70.877 62.478 70.925 ;
     RECT  70.956 70.829 71.37 70.925 ;
     RECT  70.956 70.925 71.082 70.973 ;
     RECT  83.016 70.781 84.546 70.973 ;
     RECT  62.172 70.925 62.19 71.021 ;
     RECT  72.216 70.829 75.618 71.021 ;
     RECT  77.688 70.829 81.882 71.021 ;
     RECT  83.016 70.973 84.294 71.021 ;
     RECT  63.612 70.733 66.654 71.069 ;
     RECT  70.992 70.973 71.082 71.069 ;
     RECT  72.216 71.021 74.358 71.069 ;
     RECT  75.168 71.021 75.618 71.069 ;
     RECT  77.688 71.021 81.774 71.069 ;
     RECT  83.016 71.021 83.754 71.069 ;
     RECT  86.112 70.877 86.706 71.069 ;
     RECT  63.792 71.069 64.35 71.117 ;
     RECT  65.232 71.069 65.79 71.117 ;
     RECT  66.528 71.069 66.546 71.117 ;
     RECT  72.216 71.069 73.386 71.117 ;
     RECT  75.6 71.069 75.618 71.117 ;
     RECT  77.688 71.069 81.018 71.117 ;
     RECT  81.756 71.069 81.774 71.117 ;
     RECT  83.304 71.069 83.466 71.117 ;
     RECT  86.112 71.069 86.13 71.117 ;
     RECT  70.992 71.069 71.01 71.165 ;
     RECT  73.08 71.117 73.386 71.165 ;
     RECT  78.048 71.117 79.146 71.165 ;
     RECT  80.388 71.117 81.018 71.165 ;
     RECT  78.048 71.165 78.066 71.249 ;
     RECT  81 71.165 81.018 71.249 ;
     RECT  73.368 71.165 73.386 71.261 ;
    LAYER M4 ;
     RECT  2.408 2.148 2.512 69.132 ;
     RECT  2.512 2.418 2.704 68.862 ;
     RECT  7.808 2.148 7.912 69.132 ;
     RECT  7.912 2.418 8.104 68.862 ;
     RECT  13.208 2.148 13.312 69.132 ;
     RECT  13.312 2.418 13.504 68.862 ;
     RECT  18.608 2.148 18.712 69.132 ;
     RECT  18.712 2.418 18.904 68.862 ;
     RECT  24.008 2.148 24.112 69.132 ;
     RECT  24.112 2.418 24.304 68.862 ;
     RECT  29.149 1.056 29.185 1.08 ;
     RECT  29.185 1.056 29.221 1.944 ;
     RECT  29.221 0.528 29.293 1.944 ;
     RECT  29.293 0.528 29.408 2.04 ;
     RECT  29.408 0.528 29.512 69.132 ;
     RECT  29.512 0.528 29.704 68.862 ;
     RECT  29.704 5.616 29.765 6.12 ;
     RECT  29.704 0.528 29.795 1.896 ;
     RECT  29.795 1.056 29.891 1.896 ;
     RECT  29.891 1.776 29.981 1.896 ;
     RECT  29.765 5.616 30.377 5.784 ;
     RECT  29.981 1.824 30.949 1.896 ;
     RECT  31.052 7.728 31.093 7.752 ;
     RECT  30.949 1.104 31.129 1.896 ;
     RECT  31.129 1.104 31.187 2.28 ;
     RECT  31.093 7.728 31.196 8.568 ;
     RECT  31.196 7.728 31.237 9.192 ;
     RECT  31.237 7.2 31.285 9.192 ;
     RECT  31.285 7.2 31.331 9.48 ;
     RECT  31.331 7.584 31.34 9.48 ;
     RECT  31.34 7.584 31.345 10.344 ;
     RECT  31.345 7.584 31.372 10.872 ;
     RECT  31.372 7.584 31.421 9.096 ;
     RECT  31.187 1.728 31.427 2.28 ;
     RECT  31.372 10.32 31.427 10.872 ;
     RECT  31.427 1.728 31.493 1.944 ;
     RECT  31.493 1.824 31.529 1.944 ;
     RECT  30.377 5.616 31.537 5.688 ;
     RECT  31.537 5.664 31.637 5.688 ;
     RECT  31.427 10.848 31.921 10.872 ;
     RECT  31.529 1.824 31.925 1.848 ;
     RECT  31.421 8.352 32.485 9.096 ;
     RECT  31.921 10.848 32.531 10.92 ;
     RECT  32.531 10.848 32.537 10.872 ;
     RECT  32.485 8.352 32.641 9.432 ;
     RECT  32.597 1.728 32.681 1.752 ;
     RECT  32.641 7.968 33.397 9.432 ;
     RECT  33.397 7.968 33.587 9.528 ;
     RECT  33.577 6.816 33.589 6.84 ;
     RECT  33.589 6.816 33.661 7.464 ;
     RECT  33.661 7.44 34.808 7.464 ;
     RECT  33.587 8.544 34.808 9.528 ;
     RECT  34.405 10.704 34.808 10.728 ;
     RECT  32.581 30.576 34.808 30.6 ;
     RECT  34.808 2.148 34.912 69.132 ;
     RECT  34.912 2.418 35.104 68.862 ;
     RECT  35.104 7.44 35.165 7.464 ;
     RECT  35.104 10.704 35.363 10.872 ;
     RECT  35.363 10.848 36.245 10.872 ;
     RECT  35.104 8.544 37.073 9 ;
     RECT  36.925 10.032 38.761 10.056 ;
     RECT  38.761 10.032 38.801 10.152 ;
     RECT  37.073 8.64 38.873 9 ;
     RECT  38.873 8.688 40.208 9 ;
     RECT  38.801 10.128 40.208 10.152 ;
     RECT  35.104 30.576 40.208 30.6 ;
     RECT  40.208 2.148 40.312 69.132 ;
     RECT  40.312 2.418 40.504 68.862 ;
     RECT  40.504 8.784 41.747 10.152 ;
     RECT  41.747 8.832 41.749 10.152 ;
     RECT  41.749 8.832 41.833 10.248 ;
     RECT  43.333 3.504 43.549 3.528 ;
     RECT  43.369 1.776 43.657 1.8 ;
     RECT  43.549 3.408 43.859 3.528 ;
     RECT  43.693 11.184 43.907 11.208 ;
     RECT  43.909 0.576 43.945 0.6 ;
     RECT  43.657 1.728 43.964 1.8 ;
     RECT  43.964 1.728 44.125 2.28 ;
     RECT  43.945 0.576 44.197 0.696 ;
     RECT  44.149 3.984 44.237 4.008 ;
     RECT  44.197 0.528 44.291 0.696 ;
     RECT  44.233 7.776 44.377 7.8 ;
     RECT  41.833 8.832 44.377 10.152 ;
     RECT  44.377 7.776 44.521 10.152 ;
     RECT  44.521 7.776 44.605 10.872 ;
     RECT  44.125 1.728 44.809 3 ;
     RECT  44.809 1.104 45.097 3 ;
     RECT  45.253 14.112 45.277 14.136 ;
     RECT  44.605 7.776 45.301 10.152 ;
     RECT  45.277 14.112 45.301 14.184 ;
     RECT  45.097 1.104 45.313 3.912 ;
     RECT  45.313 0.576 45.349 3.912 ;
     RECT  45.349 0.576 45.421 4.008 ;
     RECT  45.421 0.24 45.608 4.008 ;
     RECT  45.277 5.136 45.608 5.16 ;
     RECT  44.588 6.192 45.608 6.216 ;
     RECT  45.301 7.392 45.608 10.152 ;
     RECT  41.749 12.768 45.608 12.792 ;
     RECT  45.301 14.112 45.608 14.232 ;
     RECT  40.504 30.576 45.608 30.6 ;
     RECT  45.241 58.128 45.608 58.152 ;
     RECT  45.608 0.24 45.683 69.132 ;
     RECT  45.683 1.728 45.712 69.132 ;
     RECT  45.683 0.24 45.853 0.696 ;
     RECT  45.712 1.728 45.904 68.862 ;
     RECT  45.904 8.016 46.019 11.448 ;
     RECT  45.853 0.144 46.163 0.696 ;
     RECT  45.904 1.728 46.211 4.776 ;
     RECT  46.163 0.144 46.253 0.456 ;
     RECT  45.904 6.816 46.289 6.84 ;
     RECT  46.211 3.408 46.499 4.776 ;
     RECT  46.499 3.984 46.897 4.776 ;
     RECT  45.904 58.128 46.979 58.152 ;
     RECT  46.211 1.728 47.317 2.28 ;
     RECT  46.019 8.448 47.317 11.448 ;
     RECT  47.317 6.672 47.4 11.448 ;
     RECT  47.4 6.672 47.405 11.688 ;
     RECT  47.317 1.728 47.461 2.904 ;
     RECT  46.897 3.984 47.461 5.16 ;
     RECT  45.904 12.768 47.477 12.792 ;
     RECT  47.461 1.728 47.548 5.16 ;
     RECT  46.253 0.144 47.581 0.264 ;
     RECT  47.405 7.92 47.621 11.688 ;
     RECT  47.548 1.728 47.629 5.208 ;
     RECT  45.904 14.16 47.689 15.192 ;
     RECT  47.629 3.408 47.765 5.208 ;
     RECT  47.581 0.144 47.843 0.552 ;
     RECT  47.765 3.408 47.953 4.584 ;
     RECT  47.941 58.704 48.025 58.728 ;
     RECT  47.843 0.144 48.305 0.264 ;
     RECT  47.629 1.728 48.377 2.328 ;
     RECT  47.405 6.816 48.409 6.84 ;
     RECT  47.621 7.968 48.445 11.688 ;
     RECT  47.689 12.96 48.445 15.192 ;
     RECT  47.953 3.408 48.485 4.008 ;
     RECT  48.409 6.432 48.517 6.84 ;
     RECT  48.305 0.24 48.521 0.264 ;
     RECT  48.517 6.24 48.659 6.84 ;
     RECT  48.445 7.968 48.659 15.192 ;
     RECT  48.659 7.968 48.661 11.208 ;
     RECT  48.377 2.304 48.665 2.328 ;
     RECT  48.659 12.528 48.733 15.192 ;
     RECT  48.661 7.2 48.845 11.208 ;
     RECT  48.845 7.2 48.881 7.368 ;
     RECT  48.485 3.984 48.917 4.008 ;
     RECT  48.733 12.528 48.947 15.432 ;
     RECT  48.881 7.296 48.953 7.368 ;
     RECT  48.953 7.344 49.025 7.368 ;
     RECT  48.845 8.832 49.921 11.208 ;
     RECT  48.947 12.528 49.921 15.192 ;
     RECT  49.849 1.104 49.993 1.128 ;
     RECT  50.065 6.24 50.137 6.264 ;
     RECT  49.885 2.256 50.209 2.28 ;
     RECT  50.209 2.208 50.281 2.28 ;
     RECT  50.245 3.648 50.281 3.672 ;
     RECT  50.281 2.208 50.533 3.672 ;
     RECT  50.137 6.24 50.605 7.08 ;
     RECT  50.533 2.112 50.636 3.672 ;
     RECT  49.921 8.832 50.713 15.192 ;
     RECT  50.636 2.112 50.725 3.912 ;
     RECT  50.725 2.112 50.741 4.2 ;
     RECT  50.741 2.112 50.749 4.44 ;
     RECT  50.713 8.832 50.821 15.288 ;
     RECT  50.605 6.24 50.869 7.416 ;
     RECT  50.396 16.992 50.869 17.016 ;
     RECT  49.993 0.48 50.876 1.128 ;
     RECT  50.749 2.112 50.876 5.16 ;
     RECT  50.437 37.056 50.965 37.08 ;
     RECT  50.876 0.48 51.008 5.16 ;
     RECT  50.869 6.24 51.008 7.8 ;
     RECT  50.821 8.832 51.008 16.008 ;
     RECT  50.869 16.992 51.008 17.4 ;
     RECT  45.904 30.576 51.008 30.6 ;
     RECT  50.965 37.056 51.008 37.992 ;
     RECT  51.008 0.48 51.107 69.132 ;
     RECT  51.107 1.728 51.112 69.132 ;
     RECT  51.107 0.48 51.155 0.552 ;
     RECT  51.112 1.728 51.304 68.862 ;
     RECT  51.304 37.968 51.443 37.992 ;
     RECT  51.304 6.288 51.473 16.44 ;
     RECT  51.304 21.408 51.473 21.72 ;
     RECT  51.473 16.416 51.491 16.44 ;
     RECT  51.473 21.408 51.491 21.624 ;
     RECT  51.304 1.728 51.635 2.28 ;
     RECT  51.304 5.136 51.653 5.16 ;
     RECT  51.635 1.728 51.683 2.184 ;
     RECT  51.683 1.728 51.725 1.992 ;
     RECT  51.473 6.288 51.725 15.432 ;
     RECT  51.205 0.144 51.733 0.216 ;
     RECT  51.725 1.728 51.761 1.752 ;
     RECT  51.733 0.096 51.779 0.216 ;
     RECT  51.304 3.984 51.779 4.008 ;
     RECT  51.779 0.096 52.121 0.168 ;
     RECT  52.121 0.096 52.301 0.12 ;
     RECT  51.304 19.488 52.316 19.512 ;
     RECT  51.491 21.408 52.357 21.432 ;
     RECT  52.316 19.488 52.403 19.704 ;
     RECT  51.725 7.488 52.453 15.432 ;
     RECT  51.725 6.288 52.621 6.504 ;
     RECT  52.453 7.488 52.697 15.72 ;
     RECT  52.621 6.144 52.7 6.504 ;
     RECT  52.697 7.488 52.7 14.952 ;
     RECT  52.357 21.12 52.877 21.432 ;
     RECT  52.7 6.144 52.883 14.952 ;
     RECT  52.837 5.088 53.315 5.112 ;
     RECT  53.089 1.824 53.377 1.848 ;
     RECT  53.377 1.728 53.557 1.848 ;
     RECT  52.883 6.48 53.603 14.952 ;
     RECT  53.197 0.192 53.605 0.216 ;
     RECT  53.605 0.144 53.629 0.216 ;
     RECT  52.403 19.488 53.701 19.512 ;
     RECT  53.629 0.144 53.713 0.6 ;
     RECT  53.557 1.728 53.845 2.328 ;
     RECT  53.845 1.728 53.881 2.856 ;
     RECT  53.881 1.728 53.939 4.008 ;
     RECT  53.939 3.408 53.987 4.008 ;
     RECT  53.603 6.48 54.029 14.52 ;
     RECT  53.713 0.144 54.035 0.552 ;
     RECT  53.987 3.408 54.131 3.432 ;
     RECT  53.701 18.672 54.133 19.512 ;
     RECT  54.035 0.144 54.227 0.504 ;
     RECT  54.241 4.56 54.677 4.584 ;
     RECT  52.877 21.408 54.713 21.432 ;
     RECT  53.939 1.728 54.829 2.28 ;
     RECT  54.709 38.208 54.899 38.232 ;
     RECT  54.829 1.728 54.929 1.8 ;
     RECT  54.227 0.144 54.965 0.216 ;
     RECT  54.757 20.736 55.001 20.76 ;
     RECT  54.965 0.144 55.037 0.168 ;
     RECT  54.029 6.864 55.213 14.52 ;
     RECT  54.929 1.776 55.289 1.8 ;
     RECT  55.213 6.24 55.297 14.52 ;
     RECT  54.133 18.432 55.321 19.512 ;
     RECT  55.321 18.192 55.331 19.512 ;
     RECT  54.961 16.368 55.333 16.392 ;
     RECT  55.333 15.696 55.717 16.392 ;
     RECT  55.537 49.008 55.753 49.032 ;
     RECT  55.331 18.192 56.197 18.792 ;
     RECT  55.724 39.6 56.252 39.624 ;
     RECT  55.753 48.48 56.293 49.032 ;
     RECT  56.293 23.52 56.329 23.544 ;
     RECT  56.293 1.728 56.408 1.752 ;
     RECT  55.297 6.816 56.408 14.52 ;
     RECT  55.717 15.696 56.408 16.536 ;
     RECT  56.197 17.664 56.408 18.792 ;
     RECT  56.329 23.52 56.408 23.928 ;
     RECT  55.237 27.072 56.408 27.096 ;
     RECT  51.304 30.576 56.408 30.6 ;
     RECT  56.252 39.6 56.408 39.912 ;
     RECT  56.293 44.736 56.408 44.76 ;
     RECT  56.293 47.616 56.408 49.032 ;
     RECT  56.408 1.728 56.512 69.132 ;
     RECT  56.485 0.144 56.533 0.168 ;
     RECT  56.512 1.728 56.704 68.862 ;
     RECT  56.704 41.904 56.819 42.072 ;
     RECT  56.704 6.432 56.867 19.416 ;
     RECT  56.533 0.144 56.873 0.264 ;
     RECT  56.704 38.784 56.881 39.24 ;
     RECT  56.704 1.728 56.909 3.384 ;
     RECT  56.704 23.136 56.915 25.704 ;
     RECT  56.881 39.12 56.915 39.24 ;
     RECT  56.704 40.416 56.915 40.44 ;
     RECT  56.704 51.36 56.915 51.912 ;
     RECT  56.873 0.24 56.945 0.264 ;
     RECT  56.915 24.528 56.956 25.704 ;
     RECT  56.867 6.432 56.963 14.808 ;
     RECT  56.956 24.528 56.963 25.08 ;
     RECT  56.963 13.776 57.011 14.808 ;
     RECT  56.867 16.368 57.011 19.416 ;
     RECT  57.011 17.136 57.052 19.416 ;
     RECT  56.915 51.36 57.059 51.72 ;
     RECT  56.819 42.048 57.089 42.072 ;
     RECT  57.011 13.92 57.197 14.808 ;
     RECT  56.704 27.072 57.197 27.912 ;
     RECT  56.704 43.68 57.203 43.704 ;
     RECT  56.963 24.912 57.299 25.08 ;
     RECT  56.915 23.136 57.34 23.256 ;
     RECT  56.704 47.328 57.449 47.352 ;
     RECT  56.704 37.056 57.539 37.08 ;
     RECT  56.704 45.024 57.565 45.048 ;
     RECT  57.34 23.232 57.593 23.256 ;
     RECT  56.704 50.064 57.593 50.088 ;
     RECT  57.052 18.432 57.773 19.416 ;
     RECT  56.704 4.56 57.875 4.584 ;
     RECT  56.909 2.256 57.877 3.384 ;
     RECT  56.963 6.432 57.877 12.6 ;
     RECT  56.915 39.12 57.877 39.144 ;
     RECT  57.769 48.624 57.877 48.648 ;
     RECT  57.877 38.784 57.884 39.144 ;
     RECT  57.829 21.12 57.913 21.144 ;
     RECT  57.884 38.688 57.923 39.144 ;
     RECT  57.877 43.92 57.961 43.944 ;
     RECT  57.923 38.688 57.964 38.808 ;
     RECT  57.964 38.688 57.971 38.76 ;
     RECT  57.301 0.576 57.985 1.128 ;
     RECT  57.877 5.856 57.989 12.6 ;
     RECT  57.052 17.136 58.021 17.16 ;
     RECT  57.913 21.12 58.067 21.192 ;
     RECT  57.949 54.576 58.093 54.6 ;
     RECT  58.021 19.92 58.108 19.944 ;
     RECT  57.989 6.672 58.165 12.6 ;
     RECT  57.197 13.92 58.165 14.424 ;
     RECT  58.165 6.672 58.169 14.424 ;
     RECT  57.877 48.624 58.169 48.696 ;
     RECT  58.067 21.12 58.241 21.144 ;
     RECT  58.169 9.936 58.309 14.424 ;
     RECT  57.985 0.432 58.381 1.128 ;
     RECT  57.877 2.256 58.381 4.056 ;
     RECT  58.381 0.432 58.489 4.056 ;
     RECT  58.021 17.136 58.529 17.352 ;
     RECT  57.059 51.696 58.561 51.72 ;
     RECT  58.561 51.696 58.601 52.344 ;
     RECT  58.093 54.576 58.633 55.56 ;
     RECT  58.309 9.936 58.637 14.76 ;
     RECT  58.489 0.144 58.643 4.056 ;
     RECT  57.197 27.072 58.669 27.096 ;
     RECT  58.529 17.136 58.705 17.208 ;
     RECT  58.643 1.728 58.706 4.056 ;
     RECT  58.601 51.888 58.709 52.344 ;
     RECT  58.669 26.736 58.741 27.096 ;
     RECT  58.741 46.752 58.825 46.776 ;
     RECT  58.169 48.624 58.921 48.648 ;
     RECT  58.709 51.888 58.925 51.96 ;
     RECT  58.705 17.04 58.961 17.208 ;
     RECT  57.971 38.736 58.961 38.76 ;
     RECT  58.921 48.24 59.027 48.648 ;
     RECT  58.925 51.888 59.027 51.912 ;
     RECT  58.741 29.04 59.029 29.064 ;
     RECT  58.705 50.688 59.033 50.712 ;
     RECT  57.773 18.432 59.065 18.792 ;
     RECT  58.741 5.232 59.077 5.688 ;
     RECT  58.169 6.672 59.077 8.856 ;
     RECT  58.633 54.384 59.141 55.56 ;
     RECT  59.077 5.232 59.173 8.856 ;
     RECT  58.637 9.936 59.173 13.992 ;
     RECT  59.029 28.464 59.213 29.064 ;
     RECT  59.065 45.888 59.219 45.912 ;
     RECT  58.741 26.64 59.317 27.096 ;
     RECT  59.213 28.464 59.317 28.488 ;
     RECT  59.141 54.384 59.353 55.08 ;
     RECT  59.137 42.768 59.393 42.792 ;
     RECT  59.317 26.64 59.461 28.488 ;
     RECT  59.425 38.832 59.461 38.856 ;
     RECT  59.425 40.08 59.461 40.104 ;
     RECT  59.135 37.248 59.507 37.272 ;
     RECT  59.461 38.832 59.509 40.104 ;
     RECT  59.209 57.552 59.533 57.576 ;
     RECT  59.461 26.208 59.545 28.488 ;
     RECT  58.706 1.728 59.555 3.864 ;
     RECT  59.173 5.232 59.555 13.992 ;
     RECT  59.509 38.832 59.573 39.912 ;
     RECT  59.497 45.024 59.581 45.72 ;
     RECT  59.533 57.12 59.605 57.576 ;
     RECT  59.555 5.232 59.651 13.8 ;
     RECT  59.651 5.232 59.67 5.736 ;
     RECT  59.245 48.912 59.677 48.936 ;
     RECT  59.67 5.232 59.701 5.688 ;
     RECT  58.643 0.144 59.753 0.6 ;
     RECT  59.581 45.696 59.795 45.72 ;
     RECT  59.708 47.76 59.795 47.784 ;
     RECT  59.677 50.736 59.795 51.384 ;
     RECT  59.555 2.88 59.843 3.864 ;
     RECT  59.353 54.288 59.857 55.08 ;
     RECT  59.065 18.432 59.893 18.84 ;
     RECT  59.785 33.264 59.893 33.288 ;
     RECT  59.573 39.312 59.897 39.912 ;
     RECT  58.993 43.776 59.9 43.8 ;
     RECT  59.651 6.72 59.939 13.8 ;
     RECT  59.509 15.168 59.948 15.192 ;
     RECT  59.173 16.512 59.948 16.536 ;
     RECT  59.893 18.384 59.965 18.84 ;
     RECT  59.948 14.784 60.035 16.536 ;
     RECT  57.299 24.912 60.035 24.936 ;
     RECT  59.753 0.528 60.037 0.6 ;
     RECT  59.701 5.136 60.037 5.688 ;
     RECT  59.713 68.928 60.109 68.952 ;
     RECT  59.857 53.856 60.145 55.08 ;
     RECT  59.965 70.752 60.217 70.776 ;
     RECT  59.677 48.912 60.253 48.984 ;
     RECT  60.109 68.928 60.253 69 ;
     RECT  59.9 43.776 60.265 44.472 ;
     RECT  59.965 17.568 60.289 18.84 ;
     RECT  59.545 26.64 60.329 28.488 ;
     RECT  60.253 46.752 60.373 46.776 ;
     RECT  60.035 15.072 60.397 16.536 ;
     RECT  60.289 17.568 60.397 19.368 ;
     RECT  60.373 46.512 60.46 46.776 ;
     RECT  60.373 20.832 60.505 20.856 ;
     RECT  60.037 4.56 60.509 5.688 ;
     RECT  60.253 48.816 60.533 48.984 ;
     RECT  60.397 15.072 60.545 19.368 ;
     RECT  60.533 48.576 60.565 48.984 ;
     RECT  59.897 39.312 60.577 39.384 ;
     RECT  59.555 1.728 60.58 1.848 ;
     RECT  60.469 62.016 60.613 62.04 ;
     RECT  60.565 48.576 60.652 49.032 ;
     RECT  59.939 6.72 60.659 7.272 ;
     RECT  60.572 60.96 60.659 60.984 ;
     RECT  60.613 62.016 60.659 62.76 ;
     RECT  60.58 1.728 60.668 1.896 ;
     RECT  59.843 2.88 60.668 3.432 ;
     RECT  59.605 57.12 60.685 58.152 ;
     RECT  60.652 48.576 60.689 48.936 ;
     RECT  60.685 57.12 60.721 58.536 ;
     RECT  60.545 15.168 60.725 19.368 ;
     RECT  60.037 0.528 60.757 0.648 ;
     RECT  60.668 1.728 60.757 3.432 ;
     RECT  60.145 53.568 60.757 55.08 ;
     RECT  60.757 53.568 60.793 56.04 ;
     RECT  60.721 57.12 60.793 58.68 ;
     RECT  60.505 20.544 60.833 20.856 ;
     RECT  60.329 26.64 60.841 26.808 ;
     RECT  60.757 35.328 60.841 35.352 ;
     RECT  60.689 48.576 60.865 48.84 ;
     RECT  59.795 50.736 60.865 50.76 ;
     RECT  60.757 0.528 60.893 3.432 ;
     RECT  60.253 68.928 60.901 69.288 ;
     RECT  60.217 70.704 60.901 70.776 ;
     RECT  60.721 41.376 60.937 41.4 ;
     RECT  60.865 50.16 60.937 50.76 ;
     RECT  60.901 70.704 60.937 70.824 ;
     RECT  59.893 33.216 60.973 33.288 ;
     RECT  60.265 43.776 61.004 43.8 ;
     RECT  60.937 52.416 61.004 52.44 ;
     RECT  60.793 53.568 61.004 58.68 ;
     RECT  60.577 39.12 61.009 39.384 ;
     RECT  61.004 52.416 61.037 58.68 ;
     RECT  61.004 43.584 61.081 43.8 ;
     RECT  60.937 41.376 61.093 41.448 ;
     RECT  61.153 44.784 61.189 44.808 ;
     RECT  61.093 41.376 61.225 41.688 ;
     RECT  60.659 6.816 61.244 7.272 ;
     RECT  59.939 8.448 61.244 13.8 ;
     RECT  61.225 40.848 61.261 41.688 ;
     RECT  61.081 42.96 61.261 43.8 ;
     RECT  60.725 15.936 61.297 19.368 ;
     RECT  61.009 39.12 61.297 39.624 ;
     RECT  61.244 6.816 61.369 13.8 ;
     RECT  60.901 68.4 61.369 69.288 ;
     RECT  61.297 38.784 61.381 39.624 ;
     RECT  61.261 40.848 61.381 43.8 ;
     RECT  61.189 44.784 61.381 44.952 ;
     RECT  61.381 38.688 61.397 39.624 ;
     RECT  61.381 40.848 61.397 44.952 ;
     RECT  61.397 38.688 61.429 44.952 ;
     RECT  61.261 47.328 61.441 47.4 ;
     RECT  60.865 48.528 61.441 48.84 ;
     RECT  61.441 60.672 61.477 60.696 ;
     RECT  61.477 60.432 61.513 60.696 ;
     RECT  61.429 38.544 61.515 44.952 ;
     RECT  61.515 38.496 61.525 44.952 ;
     RECT  60.893 0.144 61.553 3.432 ;
     RECT  60.509 4.56 61.573 5.16 ;
     RECT  61.037 52.224 61.573 58.68 ;
     RECT  61.513 60.336 61.573 60.696 ;
     RECT  61.369 67.824 61.621 69.288 ;
     RECT  60.937 70.704 61.621 70.92 ;
     RECT  61.553 0.576 61.633 3.432 ;
     RECT  61.633 0.672 61.649 3.432 ;
     RECT  61.573 4.416 61.649 5.16 ;
     RECT  61.585 64.848 61.669 64.872 ;
     RECT  61.525 38.448 61.693 44.952 ;
     RECT  61.649 0.672 61.705 5.16 ;
     RECT  61.705 0.768 61.808 5.16 ;
     RECT  61.369 6.816 61.808 13.848 ;
     RECT  61.297 15.936 61.808 19.992 ;
     RECT  61.549 21.12 61.808 21.528 ;
     RECT  61.573 22.752 61.808 22.776 ;
     RECT  60.841 26.64 61.808 26.664 ;
     RECT  60.329 27.984 61.808 28.488 ;
     RECT  56.704 30.576 61.808 30.6 ;
     RECT  60.973 33.024 61.808 33.288 ;
     RECT  61.052 35.376 61.808 35.4 ;
     RECT  61.693 38.448 61.808 45.192 ;
     RECT  61.441 47.328 61.808 48.84 ;
     RECT  60.937 50.16 61.808 50.856 ;
     RECT  61.573 52.224 61.808 60.696 ;
     RECT  60.659 62.16 61.808 62.76 ;
     RECT  61.669 64.848 61.808 64.92 ;
     RECT  61.621 66.096 61.808 66.12 ;
     RECT  61.621 67.248 61.808 69.288 ;
     RECT  61.808 0.768 61.811 69.288 ;
     RECT  61.811 0.768 61.859 0.792 ;
     RECT  61.811 2.148 62.104 69.288 ;
     RECT  62.104 66.72 62.125 69.288 ;
     RECT  61.621 70.704 62.147 71.112 ;
     RECT  62.125 66.72 62.197 69.576 ;
     RECT  62.147 70.704 62.201 71.016 ;
     RECT  62.197 66.72 62.233 69.624 ;
     RECT  62.201 70.704 62.233 70.92 ;
     RECT  62.104 21.12 62.243 22.776 ;
     RECT  62.104 54.24 62.273 62.184 ;
     RECT  62.104 41.04 62.309 43.368 ;
     RECT  62.104 33.024 62.317 34.2 ;
     RECT  62.243 21.12 62.345 22.44 ;
     RECT  62.104 44.352 62.387 48.12 ;
     RECT  62.104 5.904 62.435 18.792 ;
     RECT  62.387 44.4 62.435 48.12 ;
     RECT  62.435 45.6 62.453 48.12 ;
     RECT  62.104 64.992 62.461 65.592 ;
     RECT  62.233 66.72 62.489 70.92 ;
     RECT  62.453 46.08 62.531 48.12 ;
     RECT  62.435 7.2 62.62 18.792 ;
     RECT  62.62 7.2 62.675 14.856 ;
     RECT  62.345 21.12 62.675 21.672 ;
     RECT  62.675 7.2 62.705 13.512 ;
     RECT  62.309 41.04 62.713 42.84 ;
     RECT  62.273 54.24 62.741 61.56 ;
     RECT  62.675 21.12 62.777 21.144 ;
     RECT  62.809 1.728 62.893 1.848 ;
     RECT  62.104 27.936 62.915 29.112 ;
     RECT  62.893 1.824 62.929 1.848 ;
     RECT  62.435 5.904 63.011 5.928 ;
     RECT  62.104 37.056 63.116 39.288 ;
     RECT  62.915 28.416 63.137 29.112 ;
     RECT  62.461 65.568 63.137 65.592 ;
     RECT  62.705 7.2 63.173 13.272 ;
     RECT  63.116 37.056 63.203 39.72 ;
     RECT  62.104 52.704 63.205 53.064 ;
     RECT  63.205 52.512 63.26 53.064 ;
     RECT  62.104 51.312 63.269 51.336 ;
     RECT  63.173 7.2 63.299 11.976 ;
     RECT  62.317 33.024 63.299 33.768 ;
     RECT  62.62 15.888 63.317 18.792 ;
     RECT  62.104 30.576 63.317 30.6 ;
     RECT  63.299 33.072 63.34 33.768 ;
     RECT  63.299 7.44 63.347 11.976 ;
     RECT  63.26 52.32 63.349 53.064 ;
     RECT  63.269 50.736 63.353 51.336 ;
     RECT  63.317 16.272 63.389 18.792 ;
     RECT  63.347 10.32 63.395 11.976 ;
     RECT  62.435 44.4 63.397 44.424 ;
     RECT  62.531 46.08 63.417 47.4 ;
     RECT  62.713 41.04 63.421 42.168 ;
     RECT  63.353 50.928 63.421 51.336 ;
     RECT  63.349 52.32 63.421 53.112 ;
     RECT  63.203 37.056 63.425 39.096 ;
     RECT  63.389 16.368 63.461 18.792 ;
     RECT  63.253 34.848 63.461 34.872 ;
     RECT  63.137 29.088 63.491 29.112 ;
     RECT  62.741 54.288 63.493 61.56 ;
     RECT  62.489 66.72 63.493 70.872 ;
     RECT  63.493 54.288 63.529 62.328 ;
     RECT  63.461 16.368 63.533 16.632 ;
     RECT  63.421 40.992 63.533 42.168 ;
     RECT  63.34 33.072 63.587 33.576 ;
     RECT  63.397 44.4 63.587 45 ;
     RECT  63.417 46.848 63.601 47.4 ;
     RECT  63.395 10.32 63.677 10.632 ;
     RECT  62.104 63.792 63.677 63.816 ;
     RECT  62.675 14.832 63.683 14.856 ;
     RECT  63.425 37.056 63.685 39.048 ;
     RECT  63.529 54.288 63.713 62.76 ;
     RECT  63.677 10.608 63.721 10.632 ;
     RECT  63.587 33.552 63.731 33.576 ;
     RECT  63.461 17.856 63.779 18.792 ;
     RECT  63.685 36.528 63.781 39.048 ;
     RECT  63.709 64.368 63.793 65.064 ;
     RECT  63.385 48.912 63.817 48.936 ;
     RECT  63.347 7.44 63.821 8.904 ;
     RECT  63.733 30.768 63.821 30.792 ;
     RECT  63.685 35.088 63.821 35.112 ;
     RECT  63.821 8.832 63.827 8.904 ;
     RECT  63.601 46.848 63.827 47.88 ;
     RECT  63.713 55.152 63.829 62.76 ;
     RECT  63.533 40.992 63.845 41.64 ;
     RECT  63.533 16.368 63.857 16.392 ;
     RECT  63.829 55.152 63.857 63.336 ;
     RECT  63.421 50.928 63.889 53.112 ;
     RECT  63.793 64.944 63.89 65.064 ;
     RECT  63.827 46.848 63.893 47.4 ;
     RECT  63.845 40.56 63.923 41.64 ;
     RECT  63.781 36.48 63.929 39.048 ;
     RECT  63.923 40.56 63.929 41.304 ;
     RECT  63.493 66.72 63.961 71.112 ;
     RECT  63.395 11.76 63.965 11.976 ;
     RECT  63.821 7.44 64.001 7.464 ;
     RECT  63.929 36.48 64.06 37.08 ;
     RECT  63.587 44.4 64.073 44.424 ;
     RECT  63.733 42.72 64.105 43.032 ;
     RECT  63.89 64.992 64.117 65.064 ;
     RECT  63.929 38.112 64.145 39.048 ;
     RECT  64.117 64.992 64.217 65.592 ;
     RECT  63.173 13.248 64.316 13.272 ;
     RECT  63.817 48.912 64.357 49.272 ;
     RECT  63.965 11.952 64.403 11.976 ;
     RECT  64.316 13.248 64.403 13.848 ;
     RECT  64.393 36.384 64.405 36.408 ;
     RECT  64.357 48.624 64.429 49.272 ;
     RECT  64.217 64.992 64.451 65.16 ;
     RECT  63.889 50.928 64.465 53.88 ;
     RECT  64.403 13.248 64.541 13.32 ;
     RECT  63.779 17.856 64.547 18.168 ;
     RECT  64.405 22.752 64.547 22.776 ;
     RECT  63.857 55.152 64.613 59.304 ;
     RECT  64.465 50.784 64.681 53.88 ;
     RECT  64.613 55.152 64.681 59.16 ;
     RECT  64.405 35.952 64.721 36.408 ;
     RECT  63.929 41.28 64.793 41.304 ;
     RECT  64.547 17.856 64.825 17.88 ;
     RECT  64.429 48.624 64.835 49.8 ;
     RECT  64.451 64.992 64.861 65.016 ;
     RECT  63.961 66.672 64.885 71.112 ;
     RECT  64.825 17.616 64.909 17.88 ;
     RECT  64.681 50.784 64.933 59.16 ;
     RECT  64.885 66.144 64.937 71.112 ;
     RECT  64.933 50.736 64.973 59.16 ;
     RECT  63.857 60.432 64.997 63.336 ;
     RECT  64.835 48.624 65.005 49.56 ;
     RECT  65.005 48.432 65.081 49.56 ;
     RECT  64.973 50.736 65.117 52.488 ;
     RECT  64.933 45.456 65.149 45.48 ;
     RECT  63.893 46.848 65.149 46.872 ;
     RECT  64.973 53.856 65.171 59.16 ;
     RECT  64.145 38.784 65.185 39.048 ;
     RECT  64.937 70.608 65.219 71.112 ;
     RECT  65.185 38.688 65.221 39.048 ;
     RECT  64.105 42.72 65.257 43.32 ;
     RECT  65.171 53.856 65.297 58.824 ;
     RECT  63.827 8.832 65.329 8.856 ;
     RECT  64.997 60.432 65.401 63.816 ;
     RECT  64.861 64.944 65.401 65.016 ;
     RECT  65.324 11.376 65.411 11.4 ;
     RECT  65.228 16.656 65.411 16.68 ;
     RECT  65.401 60.432 65.413 65.016 ;
     RECT  65.081 48.432 65.441 49.128 ;
     RECT  65.257 42.72 65.509 43.368 ;
     RECT  65.437 44.352 65.509 44.376 ;
     RECT  65.117 50.784 65.548 52.488 ;
     RECT  64.937 66.144 65.555 69.624 ;
     RECT  64.909 17.856 65.564 17.88 ;
     RECT  65.441 48.432 65.581 48.696 ;
     RECT  65.413 60.384 65.581 65.064 ;
     RECT  65.581 47.952 65.605 48.696 ;
     RECT  65.509 42.72 65.617 44.376 ;
     RECT  65.149 45.456 65.617 46.872 ;
     RECT  65.401 13.632 65.651 13.656 ;
     RECT  65.564 17.856 65.651 18.744 ;
     RECT  65.221 38.688 65.653 39.48 ;
     RECT  65.297 54.144 65.693 58.824 ;
     RECT  65.581 60.384 65.693 65.112 ;
     RECT  65.605 47.904 65.729 48.696 ;
     RECT  65.653 38.208 65.759 39.48 ;
     RECT  65.759 37.584 65.765 39.48 ;
     RECT  65.617 42.72 65.833 46.872 ;
     RECT  65.765 39.024 65.845 39.48 ;
     RECT  65.555 66.144 65.845 69.528 ;
     RECT  65.833 42 65.891 46.872 ;
     RECT  65.548 50.88 65.941 52.488 ;
     RECT  65.891 42 65.981 45.384 ;
     RECT  65.693 60.384 65.989 63.336 ;
     RECT  65.845 39.024 66.017 40.2 ;
     RECT  65.693 64.32 66.017 65.112 ;
     RECT  65.729 47.904 66.035 48.648 ;
     RECT  65.693 54.144 66.053 58.728 ;
     RECT  66.017 40.128 66.085 40.2 ;
     RECT  65.891 46.848 66.085 46.872 ;
     RECT  66.035 47.904 66.085 48.12 ;
     RECT  65.989 59.808 66.089 63.336 ;
     RECT  66.013 19.344 66.097 19.368 ;
     RECT  66.017 64.368 66.121 65.112 ;
     RECT  65.845 66.096 66.121 69.528 ;
     RECT  65.981 42 66.131 45.048 ;
     RECT  66.053 54.24 66.161 58.728 ;
     RECT  65.329 8.832 66.179 9.672 ;
     RECT  66.085 30.96 66.193 30.984 ;
     RECT  65.219 70.656 66.373 71.112 ;
     RECT  64.721 36.384 66.445 36.408 ;
     RECT  65.765 37.584 66.445 38.04 ;
     RECT  65.941 50.88 66.517 52.632 ;
     RECT  66.373 70.608 66.521 71.112 ;
     RECT  66.085 40.128 66.553 41.016 ;
     RECT  66.131 42 66.553 45 ;
     RECT  66.121 64.368 66.557 69.528 ;
     RECT  66.521 70.704 66.557 71.112 ;
     RECT  66.557 64.368 66.593 69.288 ;
     RECT  66.557 70.704 66.659 71.064 ;
     RECT  66.593 64.368 66.665 69.192 ;
     RECT  66.659 71.04 66.665 71.064 ;
     RECT  66.517 50.64 67.057 52.632 ;
     RECT  66.265 29.04 67.093 29.064 ;
     RECT  66.085 46.848 67.129 48.12 ;
     RECT  66.161 54.288 67.165 58.728 ;
     RECT  66.179 8.832 67.208 8.856 ;
     RECT  66.133 12.48 67.208 12.504 ;
     RECT  66.949 16.368 67.208 16.392 ;
     RECT  65.651 17.856 67.208 17.88 ;
     RECT  66.265 22.752 67.208 22.776 ;
     RECT  67.093 28.896 67.208 29.064 ;
     RECT  66.193 30.816 67.208 30.984 ;
     RECT  66.985 33.504 67.208 33.528 ;
     RECT  66.325 35.04 67.208 35.064 ;
     RECT  66.445 36.384 67.208 38.04 ;
     RECT  66.017 39.024 67.208 39.048 ;
     RECT  66.553 40.128 67.208 45 ;
     RECT  67.129 46.32 67.208 48.12 ;
     RECT  67.057 50.592 67.208 52.632 ;
     RECT  67.165 54.144 67.208 58.728 ;
     RECT  66.089 60.096 67.208 63.336 ;
     RECT  66.665 64.368 67.208 69.132 ;
     RECT  67.208 2.148 67.312 69.132 ;
     RECT  67.312 2.418 67.504 68.862 ;
     RECT  67.504 44.88 67.529 57.816 ;
     RECT  67.529 55.536 67.601 57.816 ;
     RECT  67.504 12.48 67.619 12.504 ;
     RECT  67.504 68.16 67.637 68.424 ;
     RECT  67.529 44.88 67.66 54.408 ;
     RECT  67.66 44.88 67.673 54.312 ;
     RECT  67.601 55.968 67.673 57.816 ;
     RECT  67.504 59.712 67.673 62.904 ;
     RECT  67.504 66.288 67.673 67.176 ;
     RECT  67.673 66.288 67.709 66.312 ;
     RECT  67.504 16.368 67.715 16.392 ;
     RECT  67.673 59.712 67.811 62.472 ;
     RECT  67.504 37.632 67.817 40.776 ;
     RECT  67.504 41.904 67.817 41.976 ;
     RECT  67.637 68.16 67.817 68.184 ;
     RECT  67.673 54.096 67.889 54.312 ;
     RECT  67.811 59.712 68.243 60.312 ;
     RECT  67.673 44.88 68.285 52.44 ;
     RECT  67.889 54.096 68.285 54.264 ;
     RECT  68.285 54.096 68.429 54.12 ;
     RECT  67.673 55.968 68.465 57.672 ;
     RECT  68.465 55.968 68.573 56.472 ;
     RECT  67.817 40.08 68.609 40.776 ;
     RECT  67.811 61.584 68.641 62.472 ;
     RECT  67.817 41.952 68.713 41.976 ;
     RECT  67.504 42.96 68.713 43.896 ;
     RECT  67.504 36.432 68.861 36.552 ;
     RECT  68.285 46.224 68.861 52.44 ;
     RECT  68.641 61.584 68.861 63 ;
     RECT  68.861 48.384 68.897 52.44 ;
     RECT  68.897 48.384 68.933 49.32 ;
     RECT  69.037 1.728 69.073 1.752 ;
     RECT  68.965 68.976 69.073 69 ;
     RECT  68.897 50.784 69.109 52.44 ;
     RECT  69.001 0.48 69.145 0.504 ;
     RECT  69.073 1.728 69.145 1.848 ;
     RECT  68.573 55.968 69.181 56.376 ;
     RECT  68.713 41.952 69.185 43.896 ;
     RECT  68.609 40.752 69.251 40.776 ;
     RECT  69.037 10.224 69.253 10.248 ;
     RECT  68.285 44.88 69.253 45.192 ;
     RECT  68.861 46.224 69.253 47.352 ;
     RECT  68.465 57.456 69.253 57.672 ;
     RECT  68.605 58.704 69.253 58.728 ;
     RECT  69.073 68.4 69.253 69 ;
     RECT  68.933 48.384 69.257 49.272 ;
     RECT  69.181 55.584 69.325 56.376 ;
     RECT  69.253 67.824 69.337 69 ;
     RECT  67.817 39.024 69.361 39.048 ;
     RECT  69.257 48.384 69.401 49.224 ;
     RECT  69.253 57.456 69.404 58.728 ;
     RECT  68.243 59.712 69.404 59.832 ;
     RECT  69.397 70.272 69.433 70.296 ;
     RECT  68.965 3.408 69.469 3.432 ;
     RECT  68.861 61.584 69.493 61.656 ;
     RECT  69.433 70.176 69.493 70.296 ;
     RECT  69.145 0.48 69.505 1.848 ;
     RECT  69.325 54.672 69.539 56.376 ;
     RECT  69.253 10.224 69.613 10.296 ;
     RECT  69.337 68.352 69.613 69 ;
     RECT  69.361 11.664 69.644 11.688 ;
     RECT  69.493 61.152 69.649 61.656 ;
     RECT  69.401 48.384 69.653 48.456 ;
     RECT  67.504 17.856 69.685 17.88 ;
     RECT  69.613 68.352 69.685 69.048 ;
     RECT  69.493 70.176 69.685 71.256 ;
     RECT  69.404 57.456 69.721 59.832 ;
     RECT  69.649 60.912 69.721 61.656 ;
     RECT  69.644 6.816 69.731 6.84 ;
     RECT  69.613 9.888 69.781 10.296 ;
     RECT  69.644 11.376 69.781 11.688 ;
     RECT  69.685 17.04 69.781 17.88 ;
     RECT  69.109 50.784 69.793 52.92 ;
     RECT  68.861 36.432 69.829 36.456 ;
     RECT  67.817 37.632 69.829 37.656 ;
     RECT  69.469 3.408 69.865 3.48 ;
     RECT  69.788 7.344 69.932 7.8 ;
     RECT  67.504 8.832 69.932 8.856 ;
     RECT  69.721 57.456 69.937 61.656 ;
     RECT  69.865 3.408 69.973 4.008 ;
     RECT  69.973 41.856 70.009 41.88 ;
     RECT  69.685 29.712 70.013 30.216 ;
     RECT  69.361 38.688 70.013 39.048 ;
     RECT  69.793 50.784 70.013 53.016 ;
     RECT  69.932 7.344 70.019 8.856 ;
     RECT  68.861 62.976 70.069 63 ;
     RECT  70.013 30.192 70.117 30.216 ;
     RECT  70.081 40.032 70.117 40.056 ;
     RECT  69.937 57.408 70.117 61.656 ;
     RECT  69.965 64.08 70.117 64.104 ;
     RECT  69.253 44.88 70.121 47.352 ;
     RECT  69.685 68.352 70.121 71.256 ;
     RECT  69.829 36.432 70.165 37.656 ;
     RECT  70.013 38.688 70.165 38.712 ;
     RECT  69.185 43.008 70.193 43.896 ;
     RECT  70.165 36.432 70.211 38.712 ;
     RECT  69.539 55.296 70.225 56.376 ;
     RECT  70.117 57.408 70.225 61.704 ;
     RECT  70.121 68.352 70.259 69.048 ;
     RECT  70.121 44.88 70.301 46.776 ;
     RECT  70.013 50.784 70.309 52.92 ;
     RECT  69.325 66.144 70.309 66.168 ;
     RECT  70.309 66.096 70.333 66.168 ;
     RECT  70.309 67.344 70.333 67.368 ;
     RECT  70.117 35.328 70.357 35.352 ;
     RECT  70.357 35.136 70.373 35.352 ;
     RECT  69.781 9.888 70.403 11.688 ;
     RECT  70.403 9.888 70.444 10.776 ;
     RECT  70.301 46.32 70.445 46.776 ;
     RECT  70.069 62.688 70.453 63 ;
     RECT  70.117 64.08 70.453 64.392 ;
     RECT  69.973 3.408 70.46 4.584 ;
     RECT  70.225 55.296 70.513 61.704 ;
     RECT  70.333 66.096 70.513 67.368 ;
     RECT  70.117 30.192 70.549 30.312 ;
     RECT  70.46 3.408 70.595 5.112 ;
     RECT  70.193 43.008 70.604 43.848 ;
     RECT  69.505 0.144 70.643 2.328 ;
     RECT  69.781 17.04 70.653 18.408 ;
     RECT  70.309 50.4 70.657 52.92 ;
     RECT  70.373 35.136 70.661 35.16 ;
     RECT  70.211 36.48 70.661 38.712 ;
     RECT  70.643 0.144 70.691 1.944 ;
     RECT  69.653 48.432 70.693 48.456 ;
     RECT  70.019 7.344 70.729 7.416 ;
     RECT  70.653 17.856 70.733 18.408 ;
     RECT  70.549 30.192 70.733 30.888 ;
     RECT  70.117 39.744 70.789 40.056 ;
     RECT  70.009 41.424 70.789 41.88 ;
     RECT  70.733 17.952 70.801 18.408 ;
     RECT  70.301 44.88 70.805 45.048 ;
     RECT  70.513 65.376 70.933 67.368 ;
     RECT  70.259 68.352 70.933 68.424 ;
     RECT  70.789 39.744 70.94 41.88 ;
     RECT  70.604 42.96 70.94 43.848 ;
     RECT  70.019 8.832 70.945 8.856 ;
     RECT  70.729 6.72 70.981 7.416 ;
     RECT  70.733 30.192 70.981 30.312 ;
     RECT  70.94 39.744 70.981 43.848 ;
     RECT  70.453 62.688 70.981 64.392 ;
     RECT  70.933 65.376 70.981 68.424 ;
     RECT  70.981 39.36 71.027 43.848 ;
     RECT  70.945 8.832 71.077 8.904 ;
     RECT  70.801 17.952 71.125 18.744 ;
     RECT  70.981 6.72 71.129 7.464 ;
     RECT  70.693 5.184 71.161 5.256 ;
     RECT  71.077 8.448 71.164 8.904 ;
     RECT  70.657 50.16 71.197 52.92 ;
     RECT  71.125 17.952 71.209 18.792 ;
     RECT  70.693 48.432 71.228 48.84 ;
     RECT  71.197 50.16 71.228 53.256 ;
     RECT  71.161 5.184 71.267 5.736 ;
     RECT  71.164 8.832 71.269 8.904 ;
     RECT  70.444 9.888 71.269 9.912 ;
     RECT  71.228 48.432 71.315 53.256 ;
     RECT  71.315 50.784 71.345 53.256 ;
     RECT  70.513 54.528 71.365 61.704 ;
     RECT  70.981 62.688 71.365 68.424 ;
     RECT  70.981 29.472 71.381 30.312 ;
     RECT  71.027 43.008 71.413 43.848 ;
     RECT  71.269 8.832 71.468 9.912 ;
     RECT  70.445 46.32 71.485 46.536 ;
     RECT  71.345 50.928 71.485 53.256 ;
     RECT  71.485 50.928 71.521 53.4 ;
     RECT  71.027 39.36 71.525 41.784 ;
     RECT  70.595 3.408 71.557 4.008 ;
     RECT  71.449 27.312 71.557 27.336 ;
     RECT  71.468 8.832 71.564 10.776 ;
     RECT  71.557 27.312 71.605 27.624 ;
     RECT  71.521 50.928 71.621 53.496 ;
     RECT  71.365 54.528 71.621 68.424 ;
     RECT  71.315 48.432 71.629 48.984 ;
     RECT  71.485 45.984 71.665 46.536 ;
     RECT  70.691 0.144 71.699 0.552 ;
     RECT  67.504 33.6 71.708 33.624 ;
     RECT  71.267 5.184 71.749 5.208 ;
     RECT  71.564 8.832 71.749 11.352 ;
     RECT  70.121 70.08 71.749 71.256 ;
     RECT  71.699 0.144 71.795 0.504 ;
     RECT  70.691 1.728 71.845 1.944 ;
     RECT  71.621 50.928 71.845 68.424 ;
     RECT  71.749 69.504 71.845 71.256 ;
     RECT  71.525 39.36 71.852 41.688 ;
     RECT  71.129 6.72 71.917 7.416 ;
     RECT  71.708 33.504 71.953 33.624 ;
     RECT  71.413 43.008 72.025 44.76 ;
     RECT  71.795 0.144 72.065 0.264 ;
     RECT  70.661 36.48 72.133 38.088 ;
     RECT  71.917 6.24 72.14 7.416 ;
     RECT  71.749 8.832 72.14 11.976 ;
     RECT  71.381 29.76 72.205 30.312 ;
     RECT  71.305 31.344 72.205 31.368 ;
     RECT  72.065 0.24 72.209 0.264 ;
     RECT  71.953 33.504 72.313 34.104 ;
     RECT  71.893 35.136 72.313 35.16 ;
     RECT  71.209 17.952 72.325 18.744 ;
     RECT  71.749 5.088 72.373 5.208 ;
     RECT  72.205 29.76 72.373 31.368 ;
     RECT  72.313 33.504 72.373 35.16 ;
     RECT  72.133 36.192 72.373 38.088 ;
     RECT  72.025 43.008 72.373 44.952 ;
     RECT  71.665 45.984 72.373 46.776 ;
     RECT  71.629 47.856 72.373 48.984 ;
     RECT  71.845 50.928 72.373 71.256 ;
     RECT  71.749 25.392 72.385 25.416 ;
     RECT  71.557 3.312 72.421 4.008 ;
     RECT  72.373 5.088 72.421 5.256 ;
     RECT  72.14 6.24 72.469 11.976 ;
     RECT  72.325 17.088 72.469 18.744 ;
     RECT  72.373 21.216 72.529 21.24 ;
     RECT  72.373 33.504 72.529 38.088 ;
     RECT  71.852 39.216 72.529 41.688 ;
     RECT  71.845 1.728 72.533 2.232 ;
     RECT  72.533 2.148 72.608 2.232 ;
     RECT  72.421 3.312 72.608 5.256 ;
     RECT  72.469 6.24 72.608 12.552 ;
     RECT  72.385 14.832 72.608 14.856 ;
     RECT  72.313 15.84 72.608 15.864 ;
     RECT  72.469 17.088 72.608 18.792 ;
     RECT  72.529 21.216 72.608 21.432 ;
     RECT  72.385 24.624 72.608 25.416 ;
     RECT  71.605 27.312 72.608 27.768 ;
     RECT  72.373 29.76 72.608 32.328 ;
     RECT  72.529 33.504 72.608 41.688 ;
     RECT  72.373 43.008 72.608 48.984 ;
     RECT  72.373 50.832 72.608 71.256 ;
     RECT  72.608 2.148 72.712 71.256 ;
     RECT  72.712 2.418 72.904 71.256 ;
     RECT  72.904 45.792 72.929 47.16 ;
     RECT  72.904 4.128 72.965 4.152 ;
     RECT  72.904 10.176 73.043 10.824 ;
     RECT  72.904 48.432 73.043 71.256 ;
     RECT  72.904 29.76 73.073 43.656 ;
     RECT  73.073 29.808 73.081 43.656 ;
     RECT  73.043 51.6 73.145 71.256 ;
     RECT  73.081 29.808 73.187 35.016 ;
     RECT  73.081 36.48 73.187 43.656 ;
     RECT  72.904 24.624 73.235 25.032 ;
     RECT  72.904 5.904 73.283 6.84 ;
     RECT  73.187 29.808 73.331 34.2 ;
     RECT  72.904 22.8 73.397 22.824 ;
     RECT  73.043 48.432 73.397 50.568 ;
     RECT  73.145 57.408 73.397 71.256 ;
     RECT  73.283 6.72 73.405 6.84 ;
     RECT  73.331 29.952 73.433 34.2 ;
     RECT  72.929 45.984 73.433 47.16 ;
     RECT  73.397 57.408 73.441 71.16 ;
     RECT  73.433 29.952 73.469 34.104 ;
     RECT  73.441 57.408 73.469 71.112 ;
     RECT  73.469 29.952 73.475 29.976 ;
     RECT  73.433 46.032 73.505 47.16 ;
     RECT  73.187 36.528 73.541 43.656 ;
     RECT  73.505 46.032 73.541 46.056 ;
     RECT  73.397 48.432 73.541 50.184 ;
     RECT  72.904 19.92 73.549 19.944 ;
     RECT  73.235 24.624 73.577 24.84 ;
     RECT  72.904 8.832 73.649 8.856 ;
     RECT  73.145 51.6 73.685 56.424 ;
     RECT  73.469 31.68 73.763 33.624 ;
     RECT  73.541 42.432 73.804 43.656 ;
     RECT  72.904 11.904 73.811 11.928 ;
     RECT  73.685 51.648 73.829 56.424 ;
     RECT  73.804 42.624 73.837 43.656 ;
     RECT  73.763 31.68 73.859 33.048 ;
     RECT  73.837 42.768 73.859 43.656 ;
     RECT  73.859 32.304 73.901 33.048 ;
     RECT  73.405 6.72 73.907 6.744 ;
     RECT  73.829 54.576 73.955 56.424 ;
     RECT  73.043 10.8 73.973 10.824 ;
     RECT  73.859 43.248 73.996 43.656 ;
     RECT  73.541 36.528 74.045 41.304 ;
     RECT  73.996 43.536 74.045 43.656 ;
     RECT  74.013 9.936 74.053 9.96 ;
     RECT  74.045 36.528 74.149 40.92 ;
     RECT  74.149 35.712 74.153 40.92 ;
     RECT  74.153 39.6 74.189 40.92 ;
     RECT  74.053 9.072 74.297 9.96 ;
     RECT  73.955 56.064 74.297 56.424 ;
     RECT  72.904 21.408 74.329 21.432 ;
     RECT  73.901 33.024 74.333 33.048 ;
     RECT  74.297 9.936 74.339 9.96 ;
     RECT  72.904 17.952 74.341 18.744 ;
     RECT  72.904 15.84 74.387 15.864 ;
     RECT  72.904 44.736 74.405 44.76 ;
     RECT  73.469 57.552 74.441 71.112 ;
     RECT  74.329 21.408 74.501 21.672 ;
     RECT  74.341 17.952 74.549 19.512 ;
     RECT  74.041 23.376 74.579 23.4 ;
     RECT  74.501 20.976 74.581 21.672 ;
     RECT  74.581 20.976 74.585 22.2 ;
     RECT  74.585 21.072 74.629 22.2 ;
     RECT  74.441 70.656 74.657 71.112 ;
     RECT  73.577 24.624 74.675 24.648 ;
     RECT  74.441 57.552 74.675 69.528 ;
     RECT  73.505 47.136 74.689 47.16 ;
     RECT  74.549 18.672 74.729 19.512 ;
     RECT  74.629 21.12 74.729 22.2 ;
     RECT  74.675 57.552 74.729 68.424 ;
     RECT  74.189 39.6 74.765 39.624 ;
     RECT  74.729 21.12 74.873 21.432 ;
     RECT  74.797 46.08 74.917 46.104 ;
     RECT  74.689 47.136 74.917 47.64 ;
     RECT  73.829 51.648 74.941 53.592 ;
     RECT  73.955 54.576 74.941 55.08 ;
     RECT  74.773 34.512 74.977 34.536 ;
     RECT  74.917 46.08 74.977 47.64 ;
     RECT  73.541 48.672 74.977 50.184 ;
     RECT  74.297 56.4 75.048 56.424 ;
     RECT  74.729 57.552 75.048 57.576 ;
     RECT  74.729 58.608 75.053 68.424 ;
     RECT  74.153 35.712 75.193 38.088 ;
     RECT  74.977 46.08 75.193 50.184 ;
     RECT  74.941 51.648 75.193 55.08 ;
     RECT  75.193 45.936 75.203 50.184 ;
     RECT  75.053 62.976 75.205 68.424 ;
     RECT  74.675 69.504 75.233 69.528 ;
     RECT  74.729 18.672 75.251 18.84 ;
     RECT  75.301 2.304 75.337 2.328 ;
     RECT  74.977 34.32 75.409 34.536 ;
     RECT  75.193 35.712 75.409 38.232 ;
     RECT  75.337 1.776 75.445 2.328 ;
     RECT  75.193 51.648 75.445 55.128 ;
     RECT  75.048 56.4 75.445 57.576 ;
     RECT  75.013 44.688 75.481 44.712 ;
     RECT  75.203 45.936 75.485 47.928 ;
     RECT  74.629 23.328 75.493 23.352 ;
     RECT  75.409 34.32 75.493 38.232 ;
     RECT  75.445 1.776 75.517 2.376 ;
     RECT  75.493 34.32 75.539 38.568 ;
     RECT  75.445 51.648 75.557 57.576 ;
     RECT  75.493 22.944 75.593 23.352 ;
     RECT  75.485 45.936 75.593 47.736 ;
     RECT  75.593 45.936 75.625 47.688 ;
     RECT  74.657 71.04 75.629 71.112 ;
     RECT  75.517 1.152 75.635 2.376 ;
     RECT  75.553 0.144 75.661 0.168 ;
     RECT  74.732 11.28 75.661 11.304 ;
     RECT  75.539 37.632 75.683 38.568 ;
     RECT  75.205 62.976 75.683 67.944 ;
     RECT  74.941 6.72 75.779 6.744 ;
     RECT  75.692 10.032 75.779 10.056 ;
     RECT  75.661 11.28 75.779 11.832 ;
     RECT  74.045 43.536 75.781 43.56 ;
     RECT  75.481 44.688 75.805 44.76 ;
     RECT  75.625 45.744 75.805 47.688 ;
     RECT  75.781 43.296 75.827 43.56 ;
     RECT  75.517 40.8 75.829 40.824 ;
     RECT  75.829 39.888 75.875 40.824 ;
     RECT  75.779 11.28 75.881 11.304 ;
     RECT  75.203 49.2 75.98 50.184 ;
     RECT  75.557 51.648 75.98 55.704 ;
     RECT  75.557 56.88 75.98 57.576 ;
     RECT  75.053 58.608 75.98 61.8 ;
     RECT  75.661 0.144 76.019 0.552 ;
     RECT  75.539 34.32 76.021 36.552 ;
     RECT  75.805 44.688 76.025 47.688 ;
     RECT  76.025 44.688 76.061 47.016 ;
     RECT  75.98 8.88 76.067 8.904 ;
     RECT  75.98 49.2 76.067 55.704 ;
     RECT  75.629 71.04 76.093 71.064 ;
     RECT  76.067 49.2 76.105 50.184 ;
     RECT  75.841 4.56 76.115 4.584 ;
     RECT  75.98 56.88 76.115 61.8 ;
     RECT  75.593 22.944 76.133 22.968 ;
     RECT  75.251 18.816 76.165 18.84 ;
     RECT  76.115 60.816 76.165 61.8 ;
     RECT  75.683 62.976 76.165 63.24 ;
     RECT  76.165 18.816 76.205 19.224 ;
     RECT  76.061 44.88 76.205 44.904 ;
     RECT  76.021 7.248 76.211 7.272 ;
     RECT  76.124 9.072 76.211 9.672 ;
     RECT  76.201 68.976 76.213 69 ;
     RECT  75.635 1.728 76.259 2.376 ;
     RECT  76.259 1.728 76.277 2.28 ;
     RECT  76.105 49.2 76.345 49.656 ;
     RECT  76.213 68.976 76.354 69.576 ;
     RECT  74.873 21.12 76.357 21.144 ;
     RECT  76.021 33.984 76.385 36.552 ;
     RECT  76.357 20.496 76.403 21.144 ;
     RECT  76.019 0.144 76.444 0.504 ;
     RECT  76.444 0.48 76.451 0.504 ;
     RECT  75.683 64.224 76.453 67.944 ;
     RECT  76.354 68.928 76.453 69.576 ;
     RECT  76.093 70.704 76.453 71.064 ;
     RECT  76.309 7.44 76.457 7.464 ;
     RECT  76.205 19.2 76.493 19.224 ;
     RECT  76.345 48.912 76.561 49.656 ;
     RECT  76.453 64.224 76.673 69.576 ;
     RECT  76.385 34.512 76.7 36.552 ;
     RECT  75.683 37.632 76.7 38.232 ;
     RECT  76.165 60.816 76.709 63.24 ;
     RECT  76.067 51.456 76.745 55.704 ;
     RECT  76.211 9.072 76.753 9.096 ;
     RECT  76.7 34.512 76.787 38.232 ;
     RECT  76.021 41.04 76.787 41.064 ;
     RECT  76.709 62.64 76.789 63.24 ;
     RECT  76.673 64.224 76.789 68.424 ;
     RECT  76.561 48.432 76.817 49.656 ;
     RECT  76.403 20.496 76.931 20.52 ;
     RECT  76.277 1.728 76.933 2.088 ;
     RECT  76.787 37.248 76.933 38.232 ;
     RECT  76.115 56.88 76.957 59.208 ;
     RECT  76.673 69.504 77.101 69.576 ;
     RECT  76.453 70.656 77.101 71.064 ;
     RECT  76.988 10.752 77.173 10.776 ;
     RECT  76.745 53.424 77.209 55.704 ;
     RECT  76.957 56.832 77.209 59.208 ;
     RECT  77.173 10.752 77.228 11.016 ;
     RECT  77.221 41.088 77.245 41.112 ;
     RECT  77.228 10.752 77.324 11.304 ;
     RECT  76.933 37.248 77.324 38.376 ;
     RECT  75.875 39.888 77.324 39.912 ;
     RECT  76.817 48.432 77.353 48.696 ;
     RECT  77.209 53.424 77.353 59.208 ;
     RECT  76.709 60.816 77.365 61.656 ;
     RECT  76.061 46.224 77.42 47.016 ;
     RECT  77.353 48.096 77.42 48.696 ;
     RECT  76.933 1.728 77.501 1.944 ;
     RECT  77.101 69.504 77.509 71.064 ;
     RECT  76.789 62.64 77.653 68.424 ;
     RECT  77.509 69.504 77.653 71.112 ;
     RECT  77.365 60.432 77.701 61.656 ;
     RECT  77.653 62.64 77.701 71.112 ;
     RECT  77.365 9.648 77.749 9.672 ;
     RECT  77.324 10.752 77.749 11.976 ;
     RECT  76.787 34.512 77.785 36.264 ;
     RECT  77.324 37.248 77.785 39.912 ;
     RECT  76.745 52.224 77.821 52.296 ;
     RECT  77.353 53.424 77.821 59.304 ;
     RECT  77.741 16.56 77.845 16.584 ;
     RECT  76.933 3.984 78.008 4.008 ;
     RECT  77.749 9.648 78.008 11.976 ;
     RECT  77.845 16.56 78.008 17.112 ;
     RECT  77.785 22.8 78.008 22.824 ;
     RECT  77.785 34.512 78.008 39.912 ;
     RECT  77.245 41.088 78.008 41.592 ;
     RECT  75.827 43.296 78.008 43.32 ;
     RECT  77.42 46.224 78.008 48.696 ;
     RECT  77.228 49.728 78.008 49.752 ;
     RECT  77.821 52.224 78.008 59.304 ;
     RECT  77.701 60.432 78.008 71.112 ;
     RECT  78.008 2.148 78.112 71.112 ;
     RECT  78.112 2.418 78.304 71.112 ;
     RECT  78.304 38.928 78.401 39.048 ;
     RECT  78.304 9.072 78.419 9.096 ;
     RECT  78.304 10.08 78.419 11.688 ;
     RECT  78.419 10.08 78.467 10.248 ;
     RECT  78.419 11.664 78.467 11.688 ;
     RECT  78.304 54.432 78.467 71.112 ;
     RECT  78.467 57.264 78.497 71.112 ;
     RECT  78.304 16.464 78.515 16.584 ;
     RECT  78.304 22.8 78.515 22.824 ;
     RECT  78.304 41.424 78.515 41.448 ;
     RECT  78.304 43.248 78.515 43.272 ;
     RECT  78.304 45.6 78.553 47.304 ;
     RECT  78.467 10.08 78.563 10.2 ;
     RECT  78.515 16.56 78.563 16.584 ;
     RECT  78.304 51.936 78.563 53.064 ;
     RECT  78.563 10.176 78.581 10.2 ;
     RECT  78.304 49.008 78.581 49.032 ;
     RECT  78.553 45.84 78.653 47.304 ;
     RECT  78.497 57.264 78.717 71.16 ;
     RECT  78.401 38.928 78.725 38.952 ;
     RECT  78.653 46.8 78.725 46.824 ;
     RECT  78.304 40.416 78.947 40.44 ;
     RECT  78.717 57.552 79.157 71.16 ;
     RECT  79.157 57.552 79.187 71.112 ;
     RECT  79.187 57.552 79.229 66.12 ;
     RECT  78.304 50.16 79.265 50.76 ;
     RECT  79.229 57.552 79.409 58.152 ;
     RECT  78.467 54.432 79.477 56.04 ;
     RECT  78.563 51.984 79.549 53.064 ;
     RECT  79.477 54.336 79.549 56.04 ;
     RECT  79.229 59.184 79.667 66.12 ;
     RECT  79.409 57.552 79.693 57.576 ;
     RECT  79.667 60.384 79.841 66.12 ;
     RECT  79.841 60.816 80.057 66.12 ;
     RECT  79.549 51.984 80.161 56.04 ;
     RECT  79.265 50.736 80.165 50.76 ;
     RECT  79.187 67.248 80.197 71.112 ;
     RECT  80.057 61.008 80.243 66.12 ;
     RECT  80.161 51.936 80.269 56.04 ;
     RECT  80.243 61.152 80.273 66.12 ;
     RECT  80.269 49.536 80.353 49.56 ;
     RECT  80.269 51.408 80.453 56.04 ;
     RECT  80.273 61.152 80.461 63.384 ;
     RECT  80.453 55.104 80.485 56.04 ;
     RECT  79.693 57.024 80.485 57.576 ;
     RECT  80.485 55.104 80.593 57.576 ;
     RECT  80.273 64.368 80.701 66.12 ;
     RECT  80.701 64.368 80.773 66.168 ;
     RECT  80.197 67.248 80.773 71.16 ;
     RECT  80.773 64.368 80.777 71.16 ;
     RECT  80.777 64.368 80.813 71.112 ;
     RECT  80.813 66.144 80.819 71.112 ;
     RECT  80.461 61.152 80.867 62.808 ;
     RECT  80.819 66.288 80.908 71.112 ;
     RECT  79.667 59.184 80.917 59.208 ;
     RECT  80.453 51.408 80.957 53.88 ;
     RECT  80.908 66.288 80.957 68.712 ;
     RECT  80.813 64.368 80.993 65.16 ;
     RECT  80.917 59.184 81.004 59.256 ;
     RECT  80.957 51.408 81.101 52.872 ;
     RECT  80.593 55.104 81.133 58.152 ;
     RECT  81.004 59.184 81.133 59.208 ;
     RECT  81.101 51.408 81.173 52.44 ;
     RECT  81.133 55.104 81.173 59.208 ;
     RECT  81.173 55.104 81.245 58.68 ;
     RECT  80.993 64.368 81.251 65.064 ;
     RECT  80.957 66.288 81.317 68.424 ;
     RECT  81.277 63.792 81.361 63.816 ;
     RECT  81.317 67.248 81.469 68.424 ;
     RECT  80.957 53.856 81.493 53.88 ;
     RECT  81.245 55.104 81.493 55.8 ;
     RECT  81.251 64.944 81.539 65.064 ;
     RECT  80.867 61.152 81.673 62.616 ;
     RECT  81.173 51.456 81.677 52.44 ;
     RECT  81.677 51.696 81.749 52.44 ;
     RECT  81.539 65.04 81.779 65.064 ;
     RECT  80.908 69.792 81.785 71.112 ;
     RECT  81.673 60.912 81.857 62.616 ;
     RECT  81.785 69.792 81.925 71.064 ;
     RECT  81.493 53.856 82.012 55.8 ;
     RECT  82.012 53.856 82.037 53.88 ;
     RECT  81.973 66.096 82.073 66.12 ;
     RECT  82.012 54.96 82.109 55.8 ;
     RECT  82.22 63.84 82.307 63.864 ;
     RECT  81.245 57.552 82.309 58.68 ;
     RECT  82.109 55.776 82.355 55.8 ;
     RECT  81.749 51.696 82.361 51.72 ;
     RECT  81.469 67.248 82.465 67.848 ;
     RECT  81.857 60.912 82.537 62.136 ;
     RECT  81.925 68.88 82.577 71.064 ;
     RECT  82.309 57.312 82.681 58.68 ;
     RECT  82.681 57.312 82.741 58.776 ;
     RECT  82.577 68.88 82.792 69.576 ;
     RECT  82.577 70.56 82.829 71.064 ;
     RECT  82.465 66.624 83.029 67.848 ;
     RECT  82.792 68.832 83.029 69.576 ;
     RECT  82.829 70.608 83.125 71.064 ;
     RECT  82.537 60.432 83.152 62.136 ;
     RECT  83.152 60.432 83.228 62.184 ;
     RECT  83.113 65.568 83.269 65.592 ;
     RECT  83.029 66.624 83.269 69.576 ;
     RECT  83.149 52.464 83.408 52.488 ;
     RECT  83.293 53.616 83.408 53.64 ;
     RECT  82.741 57.312 83.408 59.304 ;
     RECT  83.228 60.432 83.408 62.76 ;
     RECT  82.501 63.744 83.408 63.816 ;
     RECT  83.269 65.568 83.408 69.576 ;
     RECT  83.408 2.148 83.512 69.576 ;
     RECT  83.512 2.418 83.704 69.576 ;
     RECT  83.704 53.472 84.017 58.248 ;
     RECT  83.704 52.416 84.125 52.488 ;
     RECT  83.704 67.152 84.181 69.576 ;
     RECT  83.125 70.608 84.181 71.112 ;
     RECT  84.125 52.416 84.197 52.44 ;
     RECT  84.181 67.152 84.197 71.112 ;
     RECT  84.017 53.472 84.485 58.2 ;
     RECT  84.485 54.576 84.515 58.2 ;
     RECT  84.197 67.248 84.557 71.112 ;
     RECT  84.485 53.472 84.593 53.592 ;
     RECT  84.557 68.352 84.593 71.112 ;
     RECT  84.593 53.52 84.701 53.592 ;
     RECT  84.515 55.152 84.707 58.2 ;
     RECT  84.557 67.248 84.803 67.272 ;
     RECT  84.707 55.152 84.995 56.952 ;
     RECT  84.707 58.176 84.995 58.2 ;
     RECT  84.995 55.152 85.025 56.76 ;
     RECT  84.593 68.4 85.025 71.112 ;
     RECT  84.701 53.52 85.061 53.544 ;
     RECT  85.025 55.872 85.133 56.76 ;
     RECT  83.704 62.16 85.273 62.184 ;
     RECT  85.025 70.128 85.529 71.112 ;
     RECT  85.529 70.848 85.817 71.112 ;
     RECT  85.817 71.04 86.141 71.112 ;
     RECT  85.273 62.16 86.249 62.664 ;
     RECT  85.025 68.4 86.357 69.144 ;
     RECT  86.357 68.4 86.429 69.096 ;
     RECT  86.249 62.64 86.537 62.664 ;
     RECT  86.141 71.04 86.717 71.064 ;
     RECT  88.808 2.148 88.912 69.132 ;
     RECT  88.912 2.418 89.104 68.862 ;
     RECT  94.208 2.148 94.312 69.132 ;
     RECT  94.312 2.418 94.504 68.862 ;
     RECT  99.608 2.148 99.712 69.132 ;
     RECT  99.712 2.418 99.904 68.862 ;
     RECT  105.008 2.148 105.112 69.132 ;
     RECT  105.112 2.418 105.304 68.862 ;
     RECT  110.408 2.148 110.512 69.132 ;
     RECT  110.512 2.418 110.704 68.862 ;
     RECT  115.808 2.148 115.912 69.132 ;
     RECT  115.912 2.418 116.104 68.862 ;
     RECT  121.208 2.148 121.312 69.132 ;
     RECT  121.312 2.418 121.504 68.862 ;
     RECT  126.608 2.148 126.712 69.132 ;
     RECT  126.712 2.418 126.904 68.862 ;
    LAYER M5 ;
     RECT  50.256 0.016 51.768 0.611 ;
     RECT  56.4 0.016 61.848 0.803 ;
     RECT  75.6 0.016 77.112 1.187 ;
     RECT  31.056 0.016 31.512 1.763 ;
     RECT  32.592 0.016 32.664 1.763 ;
     RECT  43.728 0.016 44.328 1.763 ;
     RECT  45.36 0.016 48.312 1.763 ;
     RECT  53.424 0.016 54.84 1.763 ;
     RECT  69.456 0.016 72.504 1.763 ;
     RECT  75.648 1.187 77.112 1.763 ;
     RECT  43.776 1.763 44.328 1.811 ;
     RECT  31.104 1.763 31.512 1.859 ;
     RECT  53.472 1.763 54.792 1.859 ;
     RECT  62.832 0.016 62.904 1.859 ;
     RECT  69.504 1.763 72.504 1.859 ;
     RECT  75.696 1.763 77.112 1.859 ;
     RECT  29.52 0.016 29.976 1.907 ;
     RECT  75.84 1.859 77.112 1.955 ;
     RECT  45.36 1.763 48.216 2.005 ;
     RECT  29.52 1.907 29.712 2.137 ;
     RECT  56.4 0.803 61.8 2.137 ;
     RECT  69.648 1.859 72.504 2.137 ;
     RECT  2.4 2.137 2.52 2.151 ;
     RECT  7.8 2.137 7.92 2.151 ;
     RECT  13.2 2.137 13.32 2.151 ;
     RECT  18.6 2.137 18.72 2.151 ;
     RECT  24 2.137 24.12 2.151 ;
     RECT  34.8 2.137 34.92 2.151 ;
     RECT  40.2 2.137 40.32 2.151 ;
     RECT  67.2 2.137 67.32 2.151 ;
     RECT  69.648 2.137 72.72 2.151 ;
     RECT  78 2.137 78.12 2.151 ;
     RECT  83.4 2.137 83.52 2.151 ;
     RECT  88.8 2.137 88.92 2.151 ;
     RECT  94.2 2.137 94.32 2.151 ;
     RECT  99.6 2.137 99.72 2.151 ;
     RECT  105 2.137 105.12 2.151 ;
     RECT  110.4 2.137 110.52 2.151 ;
     RECT  115.8 2.137 115.92 2.151 ;
     RECT  121.2 2.137 121.32 2.151 ;
     RECT  126.6 2.137 126.72 2.151 ;
     RECT  43.776 1.811 44.232 2.243 ;
     RECT  31.2 1.859 31.416 2.291 ;
     RECT  53.568 1.859 54.792 2.291 ;
     RECT  53.568 2.291 54.648 2.339 ;
     RECT  75.84 1.955 76.968 2.339 ;
     RECT  45.312 2.005 48.216 2.867 ;
     RECT  50.352 0.611 51.768 2.867 ;
     RECT  53.904 2.339 54.648 2.867 ;
     RECT  56.4 2.137 62.112 3.395 ;
     RECT  43.776 2.243 44.184 3.443 ;
     RECT  69.648 2.151 72.912 3.443 ;
     RECT  69.888 3.443 72.912 3.491 ;
     RECT  43.824 3.443 44.184 3.539 ;
     RECT  50.496 2.867 51.768 3.683 ;
     RECT  50.688 3.683 51.768 3.923 ;
     RECT  44.16 3.539 44.184 4.019 ;
     RECT  45.408 2.867 48.216 4.019 ;
     RECT  50.736 3.923 51.768 4.019 ;
     RECT  53.952 2.867 54.648 4.019 ;
     RECT  69.984 3.491 72.912 4.019 ;
     RECT  76.08 2.339 76.968 4.019 ;
     RECT  50.736 4.019 51.312 4.211 ;
     RECT  50.784 4.211 51.312 4.451 ;
     RECT  50.832 4.451 51.312 4.547 ;
     RECT  45.6 4.019 47.928 4.595 ;
     RECT  54.288 4.019 54.648 4.595 ;
     RECT  57.84 3.395 62.112 4.595 ;
     RECT  69.984 4.019 71.304 4.595 ;
     RECT  76.08 4.019 76.104 4.595 ;
     RECT  45.6 4.595 46.152 4.691 ;
     RECT  45.6 4.691 46.104 4.787 ;
     RECT  70.512 4.595 71.304 5.077 ;
     RECT  72.384 4.019 72.912 5.077 ;
     RECT  58.752 4.595 62.112 5.123 ;
     RECT  70.512 5.077 72.912 5.123 ;
     RECT  47.184 4.595 47.64 5.171 ;
     RECT  58.752 5.123 60.696 5.171 ;
     RECT  71.232 5.123 72.912 5.747 ;
     RECT  58.752 5.171 59.736 5.845 ;
     RECT  61.8 5.123 62.112 5.893 ;
     RECT  71.76 5.747 72.912 5.893 ;
     RECT  53.28 5.077 53.304 6.133 ;
     RECT  45.6 4.787 46.056 6.181 ;
     RECT  51 4.547 51.312 6.229 ;
     RECT  50.112 6.229 51.312 6.277 ;
     RECT  52.848 6.133 53.304 6.709 ;
     RECT  57.888 5.845 59.736 6.709 ;
     RECT  71.76 5.893 73.272 6.709 ;
     RECT  47.328 6.661 47.352 6.805 ;
     RECT  48.624 6.229 48.648 6.805 ;
     RECT  55.248 6.229 55.272 6.805 ;
     RECT  56.4 3.395 56.712 6.805 ;
     RECT  57.888 6.709 60.648 6.805 ;
     RECT  61.8 5.893 63 6.805 ;
     RECT  71.616 6.709 73.896 6.805 ;
     RECT  52.848 6.709 53.832 6.853 ;
     RECT  55.248 6.805 56.712 6.853 ;
     RECT  52.848 6.853 56.712 7.045 ;
     RECT  52.752 7.045 56.712 7.189 ;
     RECT  57.888 6.805 63 7.189 ;
     RECT  75.744 6.709 75.768 7.237 ;
     RECT  70.992 6.805 73.896 7.475 ;
     RECT  31.248 5.605 31.512 7.717 ;
     RECT  44.64 6.181 46.056 7.765 ;
     RECT  69.696 6.805 69.72 7.765 ;
     RECT  69.696 7.765 69.864 7.861 ;
     RECT  32.592 1.763 32.616 8.197 ;
     RECT  33.6 6.805 33.624 8.197 ;
     RECT  31.104 7.717 31.512 8.387 ;
     RECT  32.592 8.197 33.624 8.437 ;
     RECT  71.616 7.475 73.896 8.437 ;
     RECT  52.752 7.189 63.288 8.485 ;
     RECT  31.104 8.387 31.416 8.579 ;
     RECT  44.448 7.765 46.056 8.579 ;
     RECT  47.328 6.805 48.648 8.579 ;
     RECT  52.752 8.485 63.624 8.869 ;
     RECT  71.088 8.437 73.896 8.869 ;
     RECT  71.04 8.869 73.896 9.061 ;
     RECT  75.744 7.237 76.2 9.061 ;
     RECT  78 2.151 78.312 9.061 ;
     RECT  31.248 8.579 31.416 9.203 ;
     RECT  32.496 8.437 33.624 9.203 ;
     RECT  50.112 6.277 51.576 9.299 ;
     RECT  31.296 9.203 31.416 9.491 ;
     RECT  33.6 9.203 33.624 9.539 ;
     RECT  47.472 8.579 48.648 9.541 ;
     RECT  44.448 8.579 45.912 9.637 ;
     RECT  75.744 9.061 76.728 9.637 ;
     RECT  78 9.061 78.408 9.637 ;
     RECT  41.712 8.773 41.736 9.779 ;
     RECT  71.04 9.061 74.088 9.925 ;
     RECT  44.448 9.637 46.008 10.069 ;
     RECT  47.472 9.541 49.224 10.069 ;
     RECT  75.744 9.637 78.408 10.069 ;
     RECT  44.448 10.069 49.224 10.117 ;
     RECT  50.688 9.299 51.576 10.165 ;
     RECT  52.752 8.869 63.816 10.165 ;
     RECT  69.696 7.861 70.008 10.213 ;
     RECT  31.392 9.491 31.416 10.355 ;
     RECT  43.872 10.117 49.224 10.355 ;
     RECT  34.8 2.151 35.112 10.693 ;
     RECT  69.072 10.213 70.008 10.741 ;
     RECT  71.04 9.925 74.328 10.741 ;
     RECT  34.8 10.693 35.352 10.883 ;
     RECT  43.872 10.355 48.648 10.883 ;
     RECT  32.496 9.203 32.616 10.931 ;
     RECT  43.872 10.883 43.896 11.219 ;
     RECT  69.072 10.741 74.328 11.269 ;
     RECT  75.744 10.069 78.552 11.269 ;
     RECT  66.144 9.637 66.168 11.365 ;
     RECT  46.944 10.883 48.648 11.699 ;
     RECT  50.688 10.165 63.816 11.941 ;
     RECT  48.288 11.699 48.648 12.035 ;
     RECT  50.688 11.941 64.392 12.227 ;
     RECT  65.376 11.365 66.168 12.469 ;
     RECT  67.2 2.151 67.512 12.469 ;
     RECT  41.76 10.213 41.784 12.803 ;
     RECT  48.288 12.035 48.552 12.949 ;
     RECT  48.096 12.949 48.552 12.997 ;
     RECT  50.688 12.227 51.312 13.093 ;
     RECT  52.464 12.227 64.392 13.139 ;
     RECT  48.096 12.997 49.032 13.477 ;
     RECT  50.448 13.093 51.312 13.573 ;
     RECT  52.464 13.139 57.864 13.573 ;
     RECT  58.944 13.139 64.392 13.811 ;
     RECT  58.944 13.811 60.504 13.955 ;
     RECT  45.312 10.883 45.912 14.101 ;
     RECT  50.448 13.573 57.864 14.531 ;
     RECT  48.096 13.477 49.08 14.819 ;
     RECT  50.448 14.531 53.592 14.819 ;
     RECT  53.472 14.819 53.592 14.915 ;
     RECT  53.568 14.915 53.592 14.963 ;
     RECT  48.096 14.819 48.936 15.061 ;
     RECT  58.992 13.955 60.504 15.107 ;
     RECT  47.952 15.061 48.936 15.443 ;
     RECT  50.448 14.819 52.488 15.443 ;
     RECT  52.368 15.443 52.488 15.731 ;
     RECT  61.584 13.811 64.392 15.925 ;
     RECT  65.376 12.469 67.608 16.357 ;
     RECT  50.448 15.443 51.312 16.405 ;
     RECT  52.368 15.731 52.392 16.405 ;
     RECT  69.072 11.269 78.552 16.595 ;
     RECT  61.44 15.925 64.392 16.645 ;
     RECT  65.376 16.357 67.704 16.645 ;
     RECT  58.992 15.107 60.408 17.557 ;
     RECT  61.44 16.645 67.704 17.557 ;
     RECT  54.768 14.531 57.864 18.709 ;
     RECT  58.992 17.557 67.704 18.709 ;
     RECT  54.768 18.709 67.704 20.771 ;
     RECT  50.448 16.405 52.392 21.155 ;
     RECT  54.864 20.771 67.704 21.203 ;
     RECT  50.448 21.155 51.48 21.635 ;
     RECT  69.072 16.595 78.504 22.835 ;
     RECT  54.864 21.203 57.96 29.029 ;
     RECT  58.992 21.203 67.704 29.029 ;
     RECT  32.592 10.931 32.616 30.611 ;
     RECT  50.448 21.635 51.432 37.091 ;
     RECT  51 37.091 51.432 38.003 ;
     RECT  54.864 29.029 67.704 38.243 ;
     RECT  69.072 22.835 78.456 40.405 ;
     RECT  69.072 40.405 78.936 40.787 ;
     RECT  55.632 38.243 67.704 43.331 ;
     RECT  55.632 43.331 67.608 43.955 ;
     RECT  55.632 43.955 57.528 45.059 ;
     RECT  58.752 43.955 67.608 46.787 ;
     RECT  55.632 45.059 57.192 47.363 ;
     RECT  59.712 46.787 67.608 47.893 ;
     RECT  69.216 40.787 78.936 47.893 ;
     RECT  59.712 47.893 78.936 48.229 ;
     RECT  55.632 47.363 57.048 49.043 ;
     RECT  58.992 48.229 78.936 49.187 ;
     RECT  68.736 49.187 78.936 50.147 ;
     RECT  69.504 50.147 78.936 50.149 ;
     RECT  58.992 49.187 67.608 50.771 ;
     RECT  56.4 49.043 57.048 51.395 ;
     RECT  58.992 50.771 59.784 51.395 ;
     RECT  60.816 50.771 67.608 51.395 ;
     RECT  56.4 51.395 56.904 51.923 ;
     RECT  58.992 51.395 59.016 51.923 ;
     RECT  80.304 49.525 80.328 52.981 ;
     RECT  60.816 51.395 67.512 53.941 ;
     RECT  60.816 53.941 67.608 54.419 ;
     RECT  83.4 2.151 83.712 54.565 ;
     RECT  69.504 50.149 79.176 54.707 ;
     RECT  59.712 54.613 59.736 54.755 ;
     RECT  81.936 54.757 81.96 55.091 ;
     RECT  69.888 54.707 79.176 55.237 ;
     RECT  80.304 52.981 80.376 55.237 ;
     RECT  69.888 55.237 79.32 55.813 ;
     RECT  80.304 55.237 80.808 55.813 ;
     RECT  60.816 54.419 67.512 55.957 ;
     RECT  69.888 55.813 80.808 55.957 ;
     RECT  83.4 54.565 84.504 56.389 ;
     RECT  69.6 55.957 80.808 56.917 ;
     RECT  83.4 56.389 84.792 56.917 ;
     RECT  69.6 56.917 81 57.445 ;
     RECT  68.784 57.445 81 57.539 ;
     RECT  82.32 55.765 82.344 57.541 ;
     RECT  82.176 57.541 82.344 57.925 ;
     RECT  83.4 56.917 84.984 57.925 ;
     RECT  45.264 14.101 45.912 58.163 ;
     RECT  46.944 11.699 46.968 58.163 ;
     RECT  82.176 57.925 84.984 58.211 ;
     RECT  77.136 57.539 79.656 58.691 ;
     RECT  47.952 15.443 47.976 58.739 ;
     RECT  77.28 58.691 79.656 58.739 ;
     RECT  60.816 55.957 67.656 58.835 ;
     RECT  60.816 58.835 65.16 59.171 ;
     RECT  68.784 57.539 76.104 59.363 ;
     RECT  68.784 59.363 72.912 59.459 ;
     RECT  77.664 58.739 79.656 59.459 ;
     RECT  66.528 58.835 67.656 59.701 ;
     RECT  68.784 59.459 69.384 59.701 ;
     RECT  66.528 59.701 69.384 59.797 ;
     RECT  73.968 59.363 76.104 59.987 ;
     RECT  60.816 59.171 64.776 60.373 ;
     RECT  66 59.797 69.384 60.373 ;
     RECT  77.664 59.459 79.464 60.421 ;
     RECT  77.376 60.421 79.464 60.661 ;
     RECT  60.816 60.373 69.384 60.949 ;
     RECT  77.376 60.661 79.56 60.997 ;
     RECT  80.784 57.539 81 60.997 ;
     RECT  60.624 60.949 69.384 61.141 ;
     RECT  70.416 59.459 72.912 61.141 ;
     RECT  77.376 60.997 81 61.141 ;
     RECT  60.624 61.141 72.912 61.477 ;
     RECT  73.968 59.987 76.008 61.477 ;
     RECT  82.176 58.211 84.792 61.525 ;
     RECT  82.08 61.525 84.792 61.619 ;
     RECT  60.624 61.477 76.008 62.149 ;
     RECT  60.624 62.149 76.2 62.195 ;
     RECT  83.184 61.619 84.792 62.195 ;
     RECT  77.376 61.141 81.048 62.581 ;
     RECT  82.08 61.619 82.104 62.581 ;
     RECT  69.264 62.195 76.2 62.677 ;
     RECT  77.376 62.581 82.104 62.677 ;
     RECT  60.624 62.195 60.648 62.771 ;
     RECT  69.264 62.677 82.104 63.733 ;
     RECT  83.232 62.195 84.792 63.733 ;
     RECT  61.68 62.195 67.656 64.931 ;
     RECT  61.8 64.931 67.656 66.085 ;
     RECT  61.68 66.085 67.656 66.803 ;
     RECT  61.68 66.803 67.512 67.283 ;
     RECT  69.264 63.733 84.792 67.283 ;
     RECT  69.264 67.283 84.504 67.859 ;
     RECT  61.8 67.283 67.512 68.341 ;
     RECT  69.312 67.859 84.12 68.435 ;
     RECT  75.792 68.435 84.12 69.061 ;
     RECT  2.4 2.151 2.712 69.129 ;
     RECT  7.8 2.151 8.112 69.129 ;
     RECT  13.2 2.151 13.512 69.129 ;
     RECT  18.6 2.151 18.912 69.129 ;
     RECT  24 2.151 24.312 69.129 ;
     RECT  29.4 2.137 29.712 69.129 ;
     RECT  34.8 10.883 35.112 69.129 ;
     RECT  40.2 2.151 40.512 69.129 ;
     RECT  45.6 58.163 45.912 69.129 ;
     RECT  51 38.003 51.312 69.129 ;
     RECT  56.4 51.923 56.712 69.129 ;
     RECT  61.632 68.341 67.512 69.129 ;
     RECT  88.8 2.151 89.112 69.129 ;
     RECT  94.2 2.151 94.512 69.129 ;
     RECT  99.6 2.151 99.912 69.129 ;
     RECT  105 2.151 105.312 69.129 ;
     RECT  110.4 2.151 110.712 69.129 ;
     RECT  115.8 2.151 116.112 69.129 ;
     RECT  121.2 2.151 121.512 69.129 ;
     RECT  126.6 2.151 126.912 69.129 ;
     RECT  2.4 69.129 2.52 69.143 ;
     RECT  7.8 69.129 7.92 69.143 ;
     RECT  13.2 69.129 13.32 69.143 ;
     RECT  18.6 69.129 18.72 69.143 ;
     RECT  24 69.129 24.12 69.143 ;
     RECT  29.4 69.129 29.52 69.143 ;
     RECT  34.8 69.129 34.92 69.143 ;
     RECT  40.2 69.129 40.32 69.143 ;
     RECT  45.6 69.129 45.72 69.143 ;
     RECT  51 69.129 51.12 69.143 ;
     RECT  56.4 69.129 56.52 69.143 ;
     RECT  61.632 69.129 67.32 69.143 ;
     RECT  88.8 69.129 88.92 69.143 ;
     RECT  94.2 69.129 94.32 69.143 ;
     RECT  99.6 69.129 99.72 69.143 ;
     RECT  105 69.129 105.12 69.143 ;
     RECT  110.4 69.129 110.52 69.143 ;
     RECT  115.8 69.129 115.92 69.143 ;
     RECT  121.2 69.129 121.32 69.143 ;
     RECT  126.6 69.129 126.72 69.143 ;
     RECT  75.792 69.061 84.168 69.157 ;
     RECT  75.792 69.157 84.264 69.397 ;
     RECT  69.504 68.435 74.664 69.493 ;
     RECT  61.632 69.143 66.6 70.693 ;
     RECT  75.792 69.397 84.312 70.739 ;
     RECT  75.792 70.739 80.856 71.075 ;
     RECT  61.632 70.693 66.648 71.123 ;
     RECT  62.064 71.123 66.648 71.248 ;
     RECT  69.504 69.493 74.712 71.248 ;
     RECT  76.272 71.075 80.856 71.248 ;
     RECT  81.936 70.739 84.312 71.248 ;
     RECT  69.504 71.248 69.528 71.267 ;
     RECT  44.376 0.016 45.216 0.132 ;
     RECT  29.976 0.132 31.056 1.763 ;
     RECT  31.512 0.132 32.592 1.859 ;
     RECT  44.328 0.132 45.36 1.811 ;
     RECT  61.848 0.132 62.832 0.803 ;
     RECT  61.8 0.803 62.832 1.859 ;
     RECT  29.976 1.763 31.104 1.859 ;
     RECT  44.232 1.811 45.36 2.005 ;
     RECT  29.976 1.859 31.2 1.907 ;
     RECT  31.416 1.859 32.592 2.291 ;
     RECT  61.8 1.859 62.112 2.137 ;
     RECT  29.712 1.907 31.2 2.291 ;
     RECT  76.968 1.955 77.112 2.137 ;
     RECT  44.232 2.005 45.312 2.243 ;
     RECT  76.968 2.137 78 4.019 ;
     RECT  44.184 2.243 45.312 2.867 ;
     RECT  44.184 2.867 45.408 4.019 ;
     RECT  56.712 3.395 57.84 4.595 ;
     RECT  71.304 4.019 72.384 5.077 ;
     RECT  46.152 4.595 47.184 4.691 ;
     RECT  56.712 4.595 58.752 5.845 ;
     RECT  46.104 4.691 47.184 4.787 ;
     RECT  46.056 4.787 47.184 5.171 ;
     RECT  60.696 5.123 61.8 5.171 ;
     RECT  46.056 5.171 47.64 6.229 ;
     RECT  31.512 5.605 32.592 8.387 ;
     RECT  71.232 5.747 71.76 6.709 ;
     RECT  56.712 5.845 57.888 7.189 ;
     RECT  46.056 6.229 48.624 6.661 ;
     RECT  48.648 6.229 50.112 9.299 ;
     RECT  55.272 6.229 56.4 6.805 ;
     RECT  51.576 6.277 52.848 7.045 ;
     RECT  46.056 6.661 47.328 8.579 ;
     RECT  47.352 6.661 48.624 6.805 ;
     RECT  53.832 6.709 55.248 6.853 ;
     RECT  60.648 6.709 61.8 6.805 ;
     RECT  71.232 6.709 71.616 6.805 ;
     RECT  32.616 6.805 33.6 8.197 ;
     RECT  33.624 6.805 34.8 9.539 ;
     RECT  69.72 6.805 70.992 7.475 ;
     RECT  51.576 7.045 52.752 10.165 ;
     RECT  69.72 7.475 71.616 7.765 ;
     RECT  29.712 7.717 31.104 8.579 ;
     RECT  69.864 7.765 71.616 7.861 ;
     RECT  70.008 7.861 71.616 8.437 ;
     RECT  31.416 8.387 32.592 8.437 ;
     RECT  31.416 8.437 32.496 10.355 ;
     RECT  70.008 8.437 71.088 8.869 ;
     RECT  45.912 8.579 47.472 9.637 ;
     RECT  40.512 8.773 41.712 9.779 ;
     RECT  70.008 8.869 71.04 10.741 ;
     RECT  76.728 9.061 78 9.637 ;
     RECT  32.616 9.203 33.6 9.539 ;
     RECT  48.648 9.299 50.688 9.541 ;
     RECT  49.224 9.541 50.688 10.355 ;
     RECT  46.008 9.637 47.472 10.069 ;
     RECT  66.168 9.637 67.2 12.469 ;
     RECT  40.512 9.779 41.736 10.213 ;
     RECT  74.328 9.925 75.744 11.269 ;
     RECT  40.512 10.213 41.76 12.803 ;
     RECT  43.896 10.883 45.312 11.219 ;
     RECT  45.912 10.883 46.944 58.163 ;
     RECT  46.968 11.699 48.288 12.949 ;
     RECT  64.392 11.941 65.376 16.645 ;
     RECT  48.552 12.035 48.648 12.997 ;
     RECT  51.312 12.227 52.464 13.573 ;
     RECT  67.608 12.469 69.072 16.357 ;
     RECT  46.968 12.949 48.096 15.061 ;
     RECT  49.032 13.093 50.448 13.477 ;
     RECT  57.864 13.139 58.944 13.955 ;
     RECT  49.08 13.477 50.448 14.819 ;
     RECT  60.504 13.811 61.584 15.107 ;
     RECT  57.864 13.955 58.992 18.709 ;
     RECT  53.592 14.531 54.768 14.963 ;
     RECT  48.936 14.819 50.448 15.443 ;
     RECT  52.488 14.819 53.472 14.915 ;
     RECT  52.488 14.915 53.568 14.963 ;
     RECT  46.968 15.061 47.952 58.163 ;
     RECT  60.408 15.107 61.584 15.925 ;
     RECT  51.312 15.443 52.368 16.405 ;
     RECT  60.408 15.925 61.44 17.557 ;
     RECT  67.704 16.357 69.072 40.787 ;
     RECT  57.96 21.203 58.992 29.029 ;
     RECT  67.704 40.787 69.216 43.331 ;
     RECT  57.528 43.955 58.752 45.059 ;
     RECT  58.992 46.787 59.712 48.229 ;
     RECT  67.608 49.187 68.736 50.147 ;
     RECT  78.936 49.525 80.304 50.149 ;
     RECT  79.176 50.149 80.304 55.237 ;
     RECT  59.784 50.771 60.816 51.395 ;
     RECT  59.736 54.613 60.816 54.755 ;
     RECT  69.6 54.707 69.888 55.957 ;
     RECT  81.96 54.757 83.4 55.091 ;
     RECT  81.936 55.091 83.4 55.237 ;
     RECT  79.32 55.237 80.304 55.813 ;
     RECT  80.808 55.237 83.4 55.765 ;
     RECT  80.808 55.765 82.32 56.917 ;
     RECT  82.344 55.765 83.4 57.925 ;
     RECT  81 56.917 82.32 57.541 ;
     RECT  67.656 57.445 68.784 59.701 ;
     RECT  76.104 57.539 77.136 58.691 ;
     RECT  79.656 57.539 80.784 59.459 ;
     RECT  81 57.541 82.176 61.141 ;
     RECT  76.104 58.691 77.28 58.739 ;
     RECT  65.16 58.835 66.528 59.171 ;
     RECT  64.776 59.171 66.528 59.797 ;
     RECT  72.912 59.363 73.968 61.477 ;
     RECT  69.384 59.459 70.416 61.141 ;
     RECT  79.464 59.459 80.784 60.661 ;
     RECT  64.776 59.797 66 60.373 ;
     RECT  76.008 59.987 76.104 60.421 ;
     RECT  76.008 60.421 77.376 62.149 ;
     RECT  79.56 60.661 80.784 60.997 ;
     RECT  81.048 61.141 82.176 61.525 ;
     RECT  81.048 61.525 82.08 62.581 ;
     RECT  82.104 61.619 83.184 62.195 ;
     RECT  76.2 62.149 77.376 62.677 ;
     RECT  60.648 62.195 61.68 62.771 ;
     RECT  82.104 62.195 83.232 63.733 ;
     RECT  61.68 64.931 61.8 66.085 ;
     RECT  61.68 67.283 61.8 68.341 ;
     RECT  84.12 67.859 84.264 69.061 ;
     RECT  74.664 68.435 75.792 69.493 ;
     RECT  84.168 69.061 84.264 69.157 ;
     RECT  74.712 69.493 75.792 71.075 ;
     RECT  80.856 70.739 81.936 71.148 ;
     RECT  80.904 71.148 81.888 71.248 ;
  END
END ot_hgi_qdq_fr_one_s2
END LIBRARY
